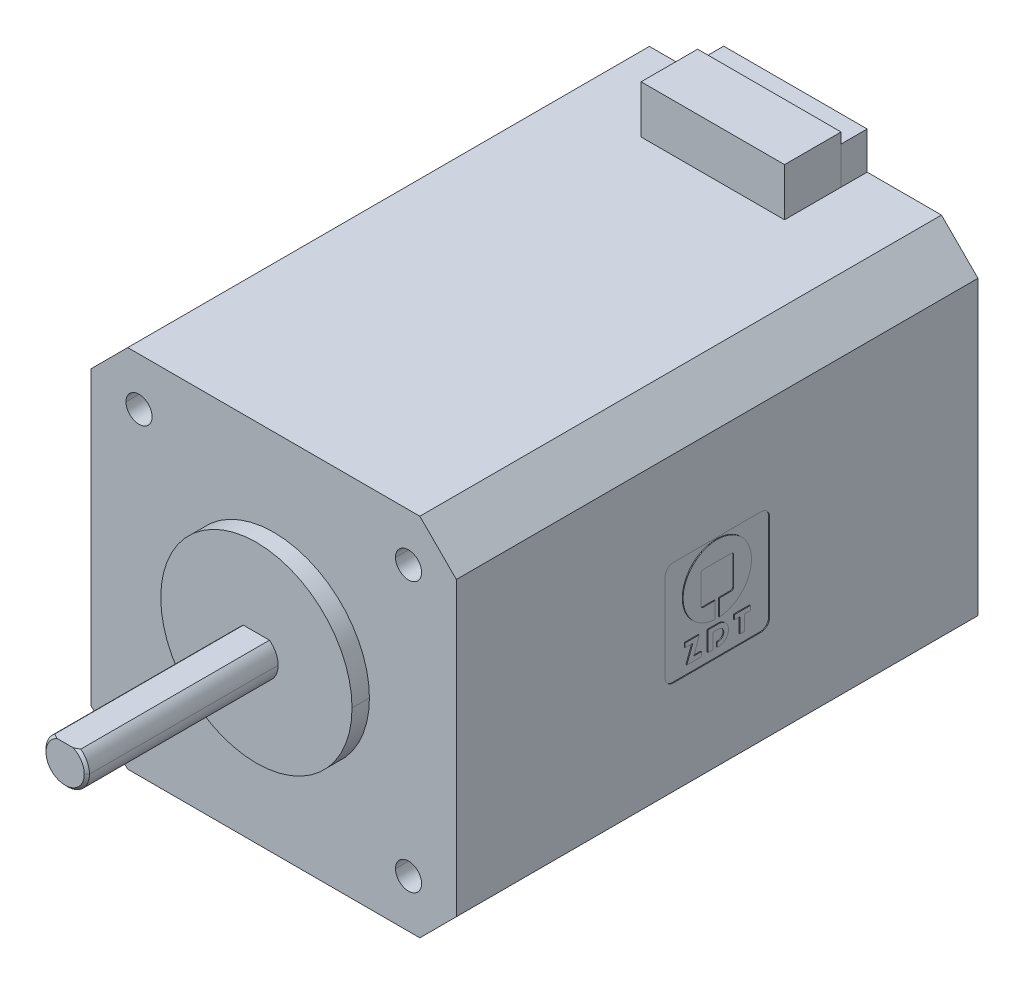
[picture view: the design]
ISO-10303-21;
HEADER;
FILE_DESCRIPTION(('STEP AP214'),'2;1');
FILE_NAME('part.step','',(''),(''),'','','');
FILE_SCHEMA(('AUTOMOTIVE_DESIGN { 1 0 10303 214 1 1 1 1 }'));
ENDSEC;
DATA;
#1=APPLICATION_CONTEXT('core data for automotive mechanical design processes');
#2=APPLICATION_PROTOCOL_DEFINITION('international standard','automotive_design',2000,#1);
#3=PRODUCT_CONTEXT('',#1,'mechanical');
#4=PRODUCT('Part','Part','',(#3));
#5=PRODUCT_RELATED_PRODUCT_CATEGORY('part','',(#4));
#6=PRODUCT_DEFINITION_FORMATION('','',#4);
#7=PRODUCT_DEFINITION_CONTEXT('part definition',#1,'design');
#8=PRODUCT_DEFINITION('design','',#6,#7);
#9=PRODUCT_DEFINITION_SHAPE('','',#8);
#10=(LENGTH_UNIT() NAMED_UNIT(*) SI_UNIT(.MILLI.,.METRE.));
#11=(NAMED_UNIT(*) PLANE_ANGLE_UNIT() SI_UNIT($,.RADIAN.));
#12=(NAMED_UNIT(*) SI_UNIT($,.STERADIAN.) SOLID_ANGLE_UNIT());
#13=UNCERTAINTY_MEASURE_WITH_UNIT(LENGTH_MEASURE(1.E-05),#10,'distance_accuracy_value','');
#14=(GEOMETRIC_REPRESENTATION_CONTEXT(3) GLOBAL_UNCERTAINTY_ASSIGNED_CONTEXT((#13)) GLOBAL_UNIT_ASSIGNED_CONTEXT((#10,
#11,#12)) REPRESENTATION_CONTEXT('',''));
#15=CARTESIAN_POINT('',(0.,0.,0.));
#16=DIRECTION('',(0.,0.,1.));
#17=DIRECTION('',(1.,0.,0.));
#18=AXIS2_PLACEMENT_3D('',#15,#16,#17);
#19=CARTESIAN_POINT('',(21.,16.8,60.));
#20=DIRECTION('',(-1.,0.,0.));
#21=DIRECTION('',(0.,1.,0.));
#22=AXIS2_PLACEMENT_3D('',#19,#20,#21);
#23=PLANE('',#22);
#24=DIRECTION('',(0.,0.,1.));
#25=VECTOR('',#24,1.);
#26=CARTESIAN_POINT('',(21.,-2.68631850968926,32.0616));
#27=LINE('',#26,#25);
#28=CARTESIAN_POINT('',(21.,-2.68631850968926,32.0616));
#29=VERTEX_POINT('',#28);
#30=CARTESIAN_POINT('',(21.,-2.68631850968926,33.6787));
#31=VERTEX_POINT('',#30);
#32=EDGE_CURVE('P0_E1623',#29,#31,#27,.T.);
#33=ORIENTED_EDGE('',*,*,#32,.T.);
#34=DIRECTION('',(0.,-1.,0.));
#35=VECTOR('',#34,1.);
#36=CARTESIAN_POINT('',(21.,-2.68631850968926,33.6787));
#37=LINE('',#36,#35);
#38=CARTESIAN_POINT('',(21.,-3.15601850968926,33.6787));
#39=VERTEX_POINT('',#38);
#40=EDGE_CURVE('P0_E11',#31,#39,#37,.T.);
#41=ORIENTED_EDGE('',*,*,#40,.T.);
#42=DIRECTION('',(0.,0.,-1.));
#43=VECTOR('',#42,1.);
#44=CARTESIAN_POINT('',(21.,-3.15601850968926,33.6787));
#45=LINE('',#44,#43);
#46=CARTESIAN_POINT('',(21.,-3.15601850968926,32.8051));
#47=VERTEX_POINT('',#46);
#48=EDGE_CURVE('P0_E48',#39,#47,#45,.T.);
#49=ORIENTED_EDGE('',*,*,#48,.T.);
#50=DIRECTION('',(0.,-0.936094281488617,0.351749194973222));
#51=VECTOR('',#50,1.);
#52=CARTESIAN_POINT('',(21.,-3.15601850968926,32.8051));
#53=LINE('',#52,#51);
#54=CARTESIAN_POINT('',(21.,-4.97551850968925,33.4888));
#55=VERTEX_POINT('',#54);
#56=EDGE_CURVE('P0_E1660',#47,#55,#53,.T.);
#57=ORIENTED_EDGE('',*,*,#56,.T.);
#58=DIRECTION('',(0.,0.,-1.));
#59=VECTOR('',#58,1.);
#60=CARTESIAN_POINT('',(21.,-4.97551850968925,33.4888));
#61=LINE('',#60,#59);
#62=CARTESIAN_POINT('',(21.,-4.97551850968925,31.8183));
#63=VERTEX_POINT('',#62);
#64=EDGE_CURVE('P0_E1654',#55,#63,#61,.T.);
#65=ORIENTED_EDGE('',*,*,#64,.T.);
#66=DIRECTION('',(0.,1.,0.));
#67=VECTOR('',#66,1.);
#68=CARTESIAN_POINT('',(21.,-4.97551850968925,31.8183));
#69=LINE('',#68,#67);
#70=CARTESIAN_POINT('',(21.,-4.48721850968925,31.8183));
#71=VERTEX_POINT('',#70);
#72=EDGE_CURVE('P0_E781',#63,#71,#69,.T.);
#73=ORIENTED_EDGE('',*,*,#72,.T.);
#74=DIRECTION('',(0.,0.,1.));
#75=VECTOR('',#74,1.);
#76=CARTESIAN_POINT('',(21.,-4.48721850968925,31.8183));
#77=LINE('',#76,#75);
#78=CARTESIAN_POINT('',(21.,-4.48721850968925,32.6607));
#79=VERTEX_POINT('',#78);
#80=EDGE_CURVE('P0_E785',#71,#79,#77,.T.);
#81=ORIENTED_EDGE('',*,*,#80,.T.);
#82=DIRECTION('',(0.,0.948882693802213,-0.315628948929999));
#83=VECTOR('',#82,1.);
#84=CARTESIAN_POINT('',(21.,-4.48721850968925,32.6607));
#85=LINE('',#84,#83);
#86=CARTESIAN_POINT('',(21.,-3.15601850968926,32.2179));
#87=VERTEX_POINT('',#86);
#88=EDGE_CURVE('P0_E752',#79,#87,#85,.T.);
#89=ORIENTED_EDGE('',*,*,#88,.T.);
#90=DIRECTION('',(0.,0.948844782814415,-0.315742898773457));
#91=VECTOR('',#90,1.);
#92=CARTESIAN_POINT('',(21.,-3.15601850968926,32.2179));
#93=LINE('',#92,#91);
#94=EDGE_CURVE('P0_E1636',#87,#29,#93,.T.);
#95=ORIENTED_EDGE('',*,*,#94,.T.);
#96=EDGE_LOOP('',(#33,#41,#49,#57,#65,#73,#81,#89,#95));
#97=FACE_BOUND('',#96,.T.);
#98=ADVANCED_FACE('P0_F18',(#97),#23,.F.);
#99=CARTESIAN_POINT('',(21.,16.8,60.));
#100=DIRECTION('',(-1.,0.,0.));
#101=DIRECTION('',(0.,1.,0.));
#102=AXIS2_PLACEMENT_3D('',#99,#100,#101);
#103=PLANE('',#102);
#104=CARTESIAN_POINT('',(21.,-3.21791850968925,29.8494));
#105=CARTESIAN_POINT('',(21.,-3.21791850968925,29.5131));
#106=CARTESIAN_POINT('',(21.,-3.49311850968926,29.2382));
#107=CARTESIAN_POINT('',(21.,-3.82921850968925,29.2382));
#108=(BOUNDED_CURVE() B_SPLINE_CURVE(3,(#104,#105,#106,#107),.UNSPECIFIED.,.F.,
.F.) B_SPLINE_CURVE_WITH_KNOTS((4,4),(0.4375,0.5),
.UNSPECIFIED.) CURVE() GEOMETRIC_REPRESENTATION_ITEM() RATIONAL_B_SPLINE_CURVE((1.,1.,1.,1.)) REPRESENTATION_ITEM(''));
#109=CARTESIAN_POINT('',(21.,-3.21791850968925,29.8494));
#110=VERTEX_POINT('',#109);
#111=CARTESIAN_POINT('',(21.,-3.82921850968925,29.2382));
#112=VERTEX_POINT('',#111);
#113=EDGE_CURVE('P0_E1344',#110,#112,#108,.T.);
#114=ORIENTED_EDGE('',*,*,#113,.T.);
#115=CARTESIAN_POINT('',(21.,-3.82921850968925,29.2382));
#116=CARTESIAN_POINT('',(21.,-4.16521850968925,29.2382));
#117=CARTESIAN_POINT('',(21.,-4.44041850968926,29.5131));
#118=CARTESIAN_POINT('',(21.,-4.44041850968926,29.8494));
#119=(BOUNDED_CURVE() B_SPLINE_CURVE(3,(#115,#116,#117,#118),.UNSPECIFIED.,.F.,
.F.) B_SPLINE_CURVE_WITH_KNOTS((4,4),(0.5,0.5625),
.UNSPECIFIED.) CURVE() GEOMETRIC_REPRESENTATION_ITEM() RATIONAL_B_SPLINE_CURVE((1.,1.,1.,1.)) REPRESENTATION_ITEM(''));
#120=CARTESIAN_POINT('',(21.,-4.44041850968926,29.8494));
#121=VERTEX_POINT('',#120);
#122=EDGE_CURVE('P0_E1440',#112,#121,#119,.T.);
#123=ORIENTED_EDGE('',*,*,#122,.T.);
#124=DIRECTION('',(0.,0.,1.));
#125=VECTOR('',#124,1.);
#126=CARTESIAN_POINT('',(21.,-4.44041850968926,29.8494));
#127=LINE('',#126,#125);
#128=CARTESIAN_POINT('',(21.,-4.44041850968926,30.));
#129=VERTEX_POINT('',#128);
#130=EDGE_CURVE('P0_E1434',#121,#129,#127,.T.);
#131=ORIENTED_EDGE('',*,*,#130,.T.);
#132=DIRECTION('',(0.,-1.,0.));
#133=VECTOR('',#132,1.);
#134=CARTESIAN_POINT('',(21.,-4.44041850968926,30.));
#135=LINE('',#134,#133);
#136=CARTESIAN_POINT('',(21.,-4.96361850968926,30.));
#137=VERTEX_POINT('',#136);
#138=EDGE_CURVE('P0_E1426',#129,#137,#135,.T.);
#139=ORIENTED_EDGE('',*,*,#138,.T.);
#140=DIRECTION('',(0.,0.,-1.));
#141=VECTOR('',#140,1.);
#142=CARTESIAN_POINT('',(21.,-4.96361850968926,30.));
#143=LINE('',#142,#141);
#144=CARTESIAN_POINT('',(21.,-4.96361850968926,29.8307));
#145=VERTEX_POINT('',#144);
#146=EDGE_CURVE('P0_E1417',#137,#145,#143,.T.);
#147=ORIENTED_EDGE('',*,*,#146,.T.);
#148=CARTESIAN_POINT('',(21.,-4.96361850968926,29.8307));
#149=CARTESIAN_POINT('',(21.,-4.96361850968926,29.2067));
#150=CARTESIAN_POINT('',(21.,-4.45321850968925,28.6962));
#151=CARTESIAN_POINT('',(21.,-3.82921850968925,28.6962));
#152=(BOUNDED_CURVE() B_SPLINE_CURVE(3,(#148,#149,#150,#151),.UNSPECIFIED.,.F.,
.F.) B_SPLINE_CURVE_WITH_KNOTS((4,4),(0.75,0.8125),
.UNSPECIFIED.) CURVE() GEOMETRIC_REPRESENTATION_ITEM() RATIONAL_B_SPLINE_CURVE((1.,1.,1.,1.)) REPRESENTATION_ITEM(''));
#153=CARTESIAN_POINT('',(21.,-3.82921850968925,28.6962));
#154=VERTEX_POINT('',#153);
#155=EDGE_CURVE('P0_E1407',#145,#154,#152,.T.);
#156=ORIENTED_EDGE('',*,*,#155,.T.);
#157=CARTESIAN_POINT('',(21.,-3.82921850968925,28.6962));
#158=CARTESIAN_POINT('',(21.,-3.20521850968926,28.6962));
#159=CARTESIAN_POINT('',(21.,-2.69471850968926,29.2067));
#160=CARTESIAN_POINT('',(21.,-2.69471850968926,29.8307));
#161=(BOUNDED_CURVE() B_SPLINE_CURVE(3,(#157,#158,#159,#160),.UNSPECIFIED.,.F.,
.F.) B_SPLINE_CURVE_WITH_KNOTS((4,4),(0.875,0.9375),
.UNSPECIFIED.) CURVE() GEOMETRIC_REPRESENTATION_ITEM() RATIONAL_B_SPLINE_CURVE((1.,1.,1.,1.)) REPRESENTATION_ITEM(''));
#162=CARTESIAN_POINT('',(21.,-2.69471850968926,29.8307));
#163=VERTEX_POINT('',#162);
#164=EDGE_CURVE('P0_E1394',#154,#163,#161,.T.);
#165=ORIENTED_EDGE('',*,*,#164,.T.);
#166=DIRECTION('',(0.,0.,1.));
#167=VECTOR('',#166,1.);
#168=CARTESIAN_POINT('',(21.,-2.69471850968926,29.8307));
#169=LINE('',#168,#167);
#170=CARTESIAN_POINT('',(21.,-2.69471850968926,31.0456));
#171=VERTEX_POINT('',#170);
#172=EDGE_CURVE('P0_E1388',#163,#171,#169,.T.);
#173=ORIENTED_EDGE('',*,*,#172,.T.);
#174=DIRECTION('',(0.,-1.,0.));
#175=VECTOR('',#174,1.);
#176=CARTESIAN_POINT('',(21.,-2.69471850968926,31.0456));
#177=LINE('',#176,#175);
#178=CARTESIAN_POINT('',(21.,-4.96361850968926,31.0456));
#179=VERTEX_POINT('',#178);
#180=EDGE_CURVE('P0_E1381',#171,#179,#177,.T.);
#181=ORIENTED_EDGE('',*,*,#180,.T.);
#182=DIRECTION('',(0.,0.,-1.));
#183=VECTOR('',#182,1.);
#184=CARTESIAN_POINT('',(21.,-4.96361850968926,31.0456));
#185=LINE('',#184,#183);
#186=CARTESIAN_POINT('',(21.,-4.96361850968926,30.5036));
#187=VERTEX_POINT('',#186);
#188=EDGE_CURVE('P0_E1373',#179,#187,#185,.T.);
#189=ORIENTED_EDGE('',*,*,#188,.T.);
#190=DIRECTION('',(0.,1.,0.));
#191=VECTOR('',#190,1.);
#192=CARTESIAN_POINT('',(21.,-4.05351850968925,30.5036));
#193=LINE('',#192,#191);
#194=CARTESIAN_POINT('',(21.,-3.21791850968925,30.5036));
#195=VERTEX_POINT('',#194);
#196=EDGE_CURVE('P0_E1370',#187,#195,#193,.T.);
#197=ORIENTED_EDGE('',*,*,#196,.T.);
#198=DIRECTION('',(0.,0.,-1.));
#199=VECTOR('',#198,1.);
#200=CARTESIAN_POINT('',(21.,-3.21791850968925,30.5036));
#201=LINE('',#200,#199);
#202=EDGE_CURVE('P0_E956',#195,#110,#201,.T.);
#203=ORIENTED_EDGE('',*,*,#202,.T.);
#204=EDGE_LOOP('',(#114,#123,#131,#139,#147,#156,#165,#173,#181,#189,#197,#203));
#205=FACE_BOUND('',#204,.T.);
#206=ADVANCED_FACE('P0_F20',(#205),#103,.F.);
#207=CARTESIAN_POINT('',(21.,16.8,60.));
#208=DIRECTION('',(-1.,0.,0.));
#209=DIRECTION('',(0.,1.,0.));
#210=AXIS2_PLACEMENT_3D('',#207,#208,#209);
#211=PLANE('',#210);
#212=CARTESIAN_POINT('',(21.,-2.06441850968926,29.7418));
#213=CARTESIAN_POINT('',(21.,-1.93761850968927,27.6866));
#214=CARTESIAN_POINT('',(21.,-0.231118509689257,26.0587));
#215=CARTESIAN_POINT('',(21.,1.85608149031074,26.0587));
#216=(BOUNDED_CURVE() B_SPLINE_CURVE(3,(#212,#213,#214,#215),.UNSPECIFIED.,.F.,
.F.) B_SPLINE_CURVE_WITH_KNOTS((4,4),(0.125,0.1875),
.UNSPECIFIED.) CURVE() GEOMETRIC_REPRESENTATION_ITEM() RATIONAL_B_SPLINE_CURVE((1.,1.,1.,1.)) REPRESENTATION_ITEM(''));
#217=CARTESIAN_POINT('',(21.,-2.06441850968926,29.7418));
#218=VERTEX_POINT('',#217);
#219=CARTESIAN_POINT('',(21.,1.85608149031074,26.0587));
#220=VERTEX_POINT('',#219);
#221=EDGE_CURVE('P0_E1444',#218,#220,#216,.T.);
#222=ORIENTED_EDGE('',*,*,#221,.T.);
#223=CARTESIAN_POINT('',(21.,1.85608149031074,26.0587));
#224=CARTESIAN_POINT('',(21.,4.02578149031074,26.0587));
#225=CARTESIAN_POINT('',(21.,5.78458149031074,27.8178));
#226=CARTESIAN_POINT('',(21.,5.78458149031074,29.9874));
#227=(BOUNDED_CURVE() B_SPLINE_CURVE(3,(#223,#224,#225,#226),.UNSPECIFIED.,.F.,
.F.) B_SPLINE_CURVE_WITH_KNOTS((4,4),(0.1875,0.25),
.UNSPECIFIED.) CURVE() GEOMETRIC_REPRESENTATION_ITEM() RATIONAL_B_SPLINE_CURVE((1.,1.,1.,1.)) REPRESENTATION_ITEM(''));
#228=CARTESIAN_POINT('',(21.,5.78458149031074,29.9874));
#229=VERTEX_POINT('',#228);
#230=EDGE_CURVE('P0_E1568',#220,#229,#227,.T.);
#231=ORIENTED_EDGE('',*,*,#230,.T.);
#232=CARTESIAN_POINT('',(21.,5.78458149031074,29.9874));
#233=CARTESIAN_POINT('',(21.,5.78458149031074,32.1568));
#234=CARTESIAN_POINT('',(21.,4.02578149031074,33.9159));
#235=CARTESIAN_POINT('',(21.,1.85608149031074,33.9159));
#236=(BOUNDED_CURVE() B_SPLINE_CURVE(3,(#232,#233,#234,#235),.UNSPECIFIED.,.F.,
.F.) B_SPLINE_CURVE_WITH_KNOTS((4,4),(0.25,0.3125),
.UNSPECIFIED.) CURVE() GEOMETRIC_REPRESENTATION_ITEM() RATIONAL_B_SPLINE_CURVE((1.,1.,1.,1.)) REPRESENTATION_ITEM(''));
#237=CARTESIAN_POINT('',(21.,1.85608149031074,33.9159));
#238=VERTEX_POINT('',#237);
#239=EDGE_CURVE('P0_E1558',#229,#238,#236,.T.);
#240=ORIENTED_EDGE('',*,*,#239,.T.);
#241=CARTESIAN_POINT('',(21.,1.85608149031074,33.9159));
#242=CARTESIAN_POINT('',(21.,-0.231118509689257,33.9159));
#243=CARTESIAN_POINT('',(21.,-1.93761850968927,32.288));
#244=CARTESIAN_POINT('',(21.,-2.06441850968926,30.2328));
#245=(BOUNDED_CURVE() B_SPLINE_CURVE(3,(#241,#242,#243,#244),.UNSPECIFIED.,.F.,
.F.) B_SPLINE_CURVE_WITH_KNOTS((4,4),(0.3125,0.375),
.UNSPECIFIED.) CURVE() GEOMETRIC_REPRESENTATION_ITEM() RATIONAL_B_SPLINE_CURVE((1.,1.,1.,1.)) REPRESENTATION_ITEM(''));
#246=CARTESIAN_POINT('',(21.,-2.06441850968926,30.2328));
#247=VERTEX_POINT('',#246);
#248=EDGE_CURVE('P0_E1546',#238,#247,#245,.T.);
#249=ORIENTED_EDGE('',*,*,#248,.T.);
#250=DIRECTION('',(0.,1.,0.));
#251=VECTOR('',#250,1.);
#252=CARTESIAN_POINT('',(21.,-2.06441850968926,30.2328));
#253=LINE('',#252,#251);
#254=CARTESIAN_POINT('',(21.,-0.175218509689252,30.2328));
#255=VERTEX_POINT('',#254);
#256=EDGE_CURVE('P0_E1538',#247,#255,#253,.T.);
#257=ORIENTED_EDGE('',*,*,#256,.T.);
#258=DIRECTION('',(0.,0.,1.));
#259=VECTOR('',#258,1.);
#260=CARTESIAN_POINT('',(21.,-0.175218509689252,30.2328));
#261=LINE('',#260,#259);
#262=CARTESIAN_POINT('',(21.,-0.175218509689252,31.5695));
#263=VERTEX_POINT('',#262);
#264=EDGE_CURVE('P0_E1535',#255,#263,#261,.T.);
#265=ORIENTED_EDGE('',*,*,#264,.T.);
#266=CARTESIAN_POINT('',(21.,-0.175218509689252,31.5695));
#267=CARTESIAN_POINT('',(21.,-0.175218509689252,31.7375));
#268=CARTESIAN_POINT('',(21.,-0.0379185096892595,31.8747));
#269=CARTESIAN_POINT('',(21.,0.129781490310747,31.8747));
#270=(BOUNDED_CURVE() B_SPLINE_CURVE(3,(#266,#267,#268,#269),.UNSPECIFIED.,.F.,
.F.) B_SPLINE_CURVE_WITH_KNOTS((4,4),(0.5,0.5625),
.UNSPECIFIED.) CURVE() GEOMETRIC_REPRESENTATION_ITEM() RATIONAL_B_SPLINE_CURVE((1.,1.,1.,1.)) REPRESENTATION_ITEM(''));
#271=CARTESIAN_POINT('',(21.,0.129781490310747,31.8747));
#272=VERTEX_POINT('',#271);
#273=EDGE_CURVE('P0_E1519',#263,#272,#270,.T.);
#274=ORIENTED_EDGE('',*,*,#273,.T.);
#275=DIRECTION('',(0.,1.,0.));
#276=VECTOR('',#275,1.);
#277=CARTESIAN_POINT('',(21.,0.129781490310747,31.8747));
#278=LINE('',#277,#276);
#279=CARTESIAN_POINT('',(21.,3.29448149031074,31.8747));
#280=VERTEX_POINT('',#279);
#281=EDGE_CURVE('P0_E1514',#272,#280,#278,.T.);
#282=ORIENTED_EDGE('',*,*,#281,.T.);
#283=CARTESIAN_POINT('',(21.,3.29448149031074,31.8747));
#284=CARTESIAN_POINT('',(21.,3.46218149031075,31.8747));
#285=CARTESIAN_POINT('',(21.,3.59968149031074,31.7375));
#286=CARTESIAN_POINT('',(21.,3.59968149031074,31.5695));
#287=(BOUNDED_CURVE() B_SPLINE_CURVE(3,(#283,#284,#285,#286),.UNSPECIFIED.,.F.,
.F.) B_SPLINE_CURVE_WITH_KNOTS((4,4),(0.625,0.6875),
.UNSPECIFIED.) CURVE() GEOMETRIC_REPRESENTATION_ITEM() RATIONAL_B_SPLINE_CURVE((1.,1.,1.,1.)) REPRESENTATION_ITEM(''));
#288=CARTESIAN_POINT('',(21.,3.59968149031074,31.5695));
#289=VERTEX_POINT('',#288);
#290=EDGE_CURVE('P0_E735',#280,#289,#287,.T.);
#291=ORIENTED_EDGE('',*,*,#290,.T.);
#292=DIRECTION('',(0.,0.,-1.));
#293=VECTOR('',#292,1.);
#294=CARTESIAN_POINT('',(21.,3.59968149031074,31.5695));
#295=LINE('',#294,#293);
#296=CARTESIAN_POINT('',(21.,3.59968149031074,28.4051));
#297=VERTEX_POINT('',#296);
#298=EDGE_CURVE('P0_E1028',#289,#297,#295,.T.);
#299=ORIENTED_EDGE('',*,*,#298,.T.);
#300=CARTESIAN_POINT('',(21.,3.59968149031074,28.4051));
#301=CARTESIAN_POINT('',(21.,3.59968149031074,28.2371));
#302=CARTESIAN_POINT('',(21.,3.46218149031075,28.0999));
#303=CARTESIAN_POINT('',(21.,3.29448149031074,28.0999));
#304=(BOUNDED_CURVE() B_SPLINE_CURVE(3,(#300,#301,#302,#303),.UNSPECIFIED.,.F.,
.F.) B_SPLINE_CURVE_WITH_KNOTS((4,4),(0.75,0.8125),
.UNSPECIFIED.) CURVE() GEOMETRIC_REPRESENTATION_ITEM() RATIONAL_B_SPLINE_CURVE((1.,1.,1.,1.)) REPRESENTATION_ITEM(''));
#305=CARTESIAN_POINT('',(21.,3.29448149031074,28.0999));
#306=VERTEX_POINT('',#305);
#307=EDGE_CURVE('P0_E1030',#297,#306,#304,.T.);
#308=ORIENTED_EDGE('',*,*,#307,.T.);
#309=DIRECTION('',(0.,-1.,0.));
#310=VECTOR('',#309,1.);
#311=CARTESIAN_POINT('',(21.,3.29448149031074,28.0999));
#312=LINE('',#311,#310);
#313=CARTESIAN_POINT('',(21.,0.129781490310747,28.0999));
#314=VERTEX_POINT('',#313);
#315=EDGE_CURVE('P0_E1491',#306,#314,#312,.T.);
#316=ORIENTED_EDGE('',*,*,#315,.T.);
#317=CARTESIAN_POINT('',(21.,0.129781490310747,28.0999));
#318=CARTESIAN_POINT('',(21.,-0.0379185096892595,28.0999));
#319=CARTESIAN_POINT('',(21.,-0.175218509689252,28.2371));
#320=CARTESIAN_POINT('',(21.,-0.175218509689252,28.4051));
#321=(BOUNDED_CURVE() B_SPLINE_CURVE(3,(#317,#318,#319,#320),.UNSPECIFIED.,.F.,
.F.) B_SPLINE_CURVE_WITH_KNOTS((4,4),(0.875,0.9375),
.UNSPECIFIED.) CURVE() GEOMETRIC_REPRESENTATION_ITEM() RATIONAL_B_SPLINE_CURVE((1.,1.,1.,1.)) REPRESENTATION_ITEM(''));
#322=CARTESIAN_POINT('',(21.,-0.175218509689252,28.4051));
#323=VERTEX_POINT('',#322);
#324=EDGE_CURVE('P0_E1477',#314,#323,#321,.T.);
#325=ORIENTED_EDGE('',*,*,#324,.T.);
#326=DIRECTION('',(0.,0.,1.));
#327=VECTOR('',#326,1.);
#328=CARTESIAN_POINT('',(21.,-0.175218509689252,28.4051));
#329=LINE('',#328,#327);
#330=CARTESIAN_POINT('',(21.,-0.175218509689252,29.7418));
#331=VERTEX_POINT('',#330);
#332=EDGE_CURVE('P0_E1475',#323,#331,#329,.T.);
#333=ORIENTED_EDGE('',*,*,#332,.T.);
#334=DIRECTION('',(0.,-1.,0.));
#335=VECTOR('',#334,1.);
#336=CARTESIAN_POINT('',(21.,-0.175218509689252,29.7418));
#337=LINE('',#336,#335);
#338=EDGE_CURVE('P0_E1464',#331,#218,#337,.T.);
#339=ORIENTED_EDGE('',*,*,#338,.T.);
#340=EDGE_LOOP('',(#222,#231,#240,#249,#257,#265,#274,#282,#291,#299,#308,#316,#325,#333,#339));
#341=FACE_BOUND('',#340,.T.);
#342=ADVANCED_FACE('P0_F1847',(#341),#211,.F.);
#343=CARTESIAN_POINT('',(21.,16.8,60.));
#344=DIRECTION('',(-1.,0.,0.));
#345=DIRECTION('',(0.,1.,0.));
#346=AXIS2_PLACEMENT_3D('',#343,#344,#345);
#347=PLANE('',#346);
#348=DIRECTION('',(0.,0.,1.));
#349=VECTOR('',#348,1.);
#350=CARTESIAN_POINT('',(21.,-2.69881850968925,26.1943));
#351=LINE('',#350,#349);
#352=CARTESIAN_POINT('',(21.,-2.69881850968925,26.1943));
#353=VERTEX_POINT('',#352);
#354=CARTESIAN_POINT('',(21.,-2.69881850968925,28.0146));
#355=VERTEX_POINT('',#354);
#356=EDGE_CURVE('P0_E1574',#353,#355,#351,.T.);
#357=ORIENTED_EDGE('',*,*,#356,.T.);
#358=DIRECTION('',(0.,-1.,0.));
#359=VECTOR('',#358,1.);
#360=CARTESIAN_POINT('',(21.,-2.69881850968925,28.0146));
#361=LINE('',#360,#359);
#362=CARTESIAN_POINT('',(21.,-3.21521850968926,28.0146));
#363=VERTEX_POINT('',#362);
#364=EDGE_CURVE('P0_E1625',#355,#363,#361,.T.);
#365=ORIENTED_EDGE('',*,*,#364,.T.);
#366=DIRECTION('',(0.,0.,-1.));
#367=VECTOR('',#366,1.);
#368=CARTESIAN_POINT('',(21.,-3.21521850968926,28.0146));
#369=LINE('',#368,#367);
#370=CARTESIAN_POINT('',(21.,-3.21521850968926,27.3627));
#371=VERTEX_POINT('',#370);
#372=EDGE_CURVE('P0_E1614',#363,#371,#369,.T.);
#373=ORIENTED_EDGE('',*,*,#372,.T.);
#374=DIRECTION('',(0.,-1.,0.));
#375=VECTOR('',#374,1.);
#376=CARTESIAN_POINT('',(21.,-3.21521850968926,27.3627));
#377=LINE('',#376,#375);
#378=CARTESIAN_POINT('',(21.,-4.94241850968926,27.3627));
#379=VERTEX_POINT('',#378);
#380=EDGE_CURVE('P0_E1335',#371,#379,#377,.T.);
#381=ORIENTED_EDGE('',*,*,#380,.T.);
#382=DIRECTION('',(0.,0.,-1.));
#383=VECTOR('',#382,1.);
#384=CARTESIAN_POINT('',(21.,-4.94241850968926,27.3627));
#385=LINE('',#384,#383);
#386=CARTESIAN_POINT('',(21.,-4.94241850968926,26.8462));
#387=VERTEX_POINT('',#386);
#388=EDGE_CURVE('P0_E1606',#379,#387,#385,.T.);
#389=ORIENTED_EDGE('',*,*,#388,.T.);
#390=DIRECTION('',(0.,1.,0.));
#391=VECTOR('',#390,1.);
#392=CARTESIAN_POINT('',(21.,-4.94241850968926,26.8462));
#393=LINE('',#392,#391);
#394=CARTESIAN_POINT('',(21.,-3.21521850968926,26.8462));
#395=VERTEX_POINT('',#394);
#396=EDGE_CURVE('P0_E1596',#387,#395,#393,.T.);
#397=ORIENTED_EDGE('',*,*,#396,.T.);
#398=DIRECTION('',(0.,0.,-1.));
#399=VECTOR('',#398,1.);
#400=CARTESIAN_POINT('',(21.,-3.21521850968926,26.8462));
#401=LINE('',#400,#399);
#402=CARTESIAN_POINT('',(21.,-3.21521850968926,26.1943));
#403=VERTEX_POINT('',#402);
#404=EDGE_CURVE('P0_E1010',#395,#403,#401,.T.);
#405=ORIENTED_EDGE('',*,*,#404,.T.);
#406=DIRECTION('',(0.,1.,0.));
#407=VECTOR('',#406,1.);
#408=CARTESIAN_POINT('',(21.,-3.21521850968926,26.1943));
#409=LINE('',#408,#407);
#410=EDGE_CURVE('P0_E1589',#403,#353,#409,.T.);
#411=ORIENTED_EDGE('',*,*,#410,.T.);
#412=EDGE_LOOP('',(#357,#365,#373,#381,#389,#397,#405,#411));
#413=FACE_BOUND('',#412,.T.);
#414=ADVANCED_FACE('P0_F2117',(#413),#347,.F.);
#415=CARTESIAN_POINT('',(20.9,-2.68631850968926,33.6787));
#416=DIRECTION('',(0.,0.,1.));
#417=DIRECTION('',(1.,0.,0.));
#418=AXIS2_PLACEMENT_3D('',#415,#416,#417);
#419=PLANE('',#418);
#420=ORIENTED_EDGE('',*,*,#40,.F.);
#421=DIRECTION('',(1.,0.,0.));
#422=VECTOR('',#421,1.);
#423=CARTESIAN_POINT('',(20.9,-2.68631850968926,33.6787));
#424=LINE('',#423,#422);
#425=CARTESIAN_POINT('',(20.9,-2.68631850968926,33.6787));
#426=VERTEX_POINT('',#425);
#427=EDGE_CURVE('P0_E1635',#426,#31,#424,.T.);
#428=ORIENTED_EDGE('',*,*,#427,.F.);
#429=DIRECTION('',(0.,-1.,0.));
#430=VECTOR('',#429,1.);
#431=CARTESIAN_POINT('',(20.9,-2.68631850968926,33.6787));
#432=LINE('',#431,#430);
#433=CARTESIAN_POINT('',(20.9,-3.15601850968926,33.6787));
#434=VERTEX_POINT('',#433);
#435=EDGE_CURVE('P0_E955',#426,#434,#432,.T.);
#436=ORIENTED_EDGE('',*,*,#435,.T.);
#437=DIRECTION('',(1.,0.,0.));
#438=VECTOR('',#437,1.);
#439=CARTESIAN_POINT('',(20.9,-3.15601850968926,33.6787));
#440=LINE('',#439,#438);
#441=EDGE_CURVE('P0_E29',#434,#39,#440,.T.);
#442=ORIENTED_EDGE('',*,*,#441,.T.);
#443=EDGE_LOOP('',(#420,#428,#436,#442));
#444=FACE_BOUND('',#443,.T.);
#445=ADVANCED_FACE('P0_F1779',(#444),#419,.T.);
#446=CARTESIAN_POINT('',(20.9,-3.15601850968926,33.6787));
#447=DIRECTION('',(0.,-1.,0.));
#448=DIRECTION('',(0.,0.,-1.));
#449=AXIS2_PLACEMENT_3D('',#446,#447,#448);
#450=PLANE('',#449);
#451=ORIENTED_EDGE('',*,*,#48,.F.);
#452=ORIENTED_EDGE('',*,*,#441,.F.);
#453=DIRECTION('',(0.,0.,-1.));
#454=VECTOR('',#453,1.);
#455=CARTESIAN_POINT('',(20.9,-3.15601850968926,33.6787));
#456=LINE('',#455,#454);
#457=CARTESIAN_POINT('',(20.9,-3.15601850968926,32.8051));
#458=VERTEX_POINT('',#457);
#459=EDGE_CURVE('P0_E954',#434,#458,#456,.T.);
#460=ORIENTED_EDGE('',*,*,#459,.T.);
#461=DIRECTION('',(1.,0.,0.));
#462=VECTOR('',#461,1.);
#463=CARTESIAN_POINT('',(20.9,-3.15601850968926,32.8051));
#464=LINE('',#463,#462);
#465=EDGE_CURVE('P0_E1210',#458,#47,#464,.T.);
#466=ORIENTED_EDGE('',*,*,#465,.T.);
#467=EDGE_LOOP('',(#451,#452,#460,#466));
#468=FACE_BOUND('',#467,.T.);
#469=ADVANCED_FACE('P0_F1780',(#468),#450,.T.);
#470=CARTESIAN_POINT('',(20.9,-3.15601850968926,32.8051));
#471=DIRECTION('',(0.,0.351749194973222,0.936094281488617));
#472=DIRECTION('',(1.,0.,0.));
#473=AXIS2_PLACEMENT_3D('',#470,#471,#472);
#474=PLANE('',#473);
#475=ORIENTED_EDGE('',*,*,#56,.F.);
#476=ORIENTED_EDGE('',*,*,#465,.F.);
#477=DIRECTION('',(0.,-0.936094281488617,0.351749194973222));
#478=VECTOR('',#477,1.);
#479=CARTESIAN_POINT('',(20.9,-3.15601850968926,32.8051));
#480=LINE('',#479,#478);
#481=CARTESIAN_POINT('',(20.9,-4.97551850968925,33.4888));
#482=VERTEX_POINT('',#481);
#483=EDGE_CURVE('P0_E931',#458,#482,#480,.T.);
#484=ORIENTED_EDGE('',*,*,#483,.T.);
#485=DIRECTION('',(1.,0.,0.));
#486=VECTOR('',#485,1.);
#487=CARTESIAN_POINT('',(20.9,-4.97551850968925,33.4888));
#488=LINE('',#487,#486);
#489=EDGE_CURVE('P0_E1656',#482,#55,#488,.T.);
#490=ORIENTED_EDGE('',*,*,#489,.T.);
#491=EDGE_LOOP('',(#475,#476,#484,#490));
#492=FACE_BOUND('',#491,.T.);
#493=ADVANCED_FACE('P0_F1777',(#492),#474,.T.);
#494=CARTESIAN_POINT('',(20.9,-4.97551850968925,33.4888));
#495=DIRECTION('',(0.,-1.,0.));
#496=DIRECTION('',(0.,0.,-1.));
#497=AXIS2_PLACEMENT_3D('',#494,#495,#496);
#498=PLANE('',#497);
#499=ORIENTED_EDGE('',*,*,#64,.F.);
#500=ORIENTED_EDGE('',*,*,#489,.F.);
#501=DIRECTION('',(0.,0.,-1.));
#502=VECTOR('',#501,1.);
#503=CARTESIAN_POINT('',(20.9,-4.97551850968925,33.4888));
#504=LINE('',#503,#502);
#505=CARTESIAN_POINT('',(20.9,-4.97551850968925,31.8183));
#506=VERTEX_POINT('',#505);
#507=EDGE_CURVE('P0_E930',#482,#506,#504,.T.);
#508=ORIENTED_EDGE('',*,*,#507,.T.);
#509=DIRECTION('',(1.,0.,0.));
#510=VECTOR('',#509,1.);
#511=CARTESIAN_POINT('',(20.9,-4.97551850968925,31.8183));
#512=LINE('',#511,#510);
#513=EDGE_CURVE('P0_E1648',#506,#63,#512,.T.);
#514=ORIENTED_EDGE('',*,*,#513,.T.);
#515=EDGE_LOOP('',(#499,#500,#508,#514));
#516=FACE_BOUND('',#515,.T.);
#517=ADVANCED_FACE('P0_F1977',(#516),#498,.T.);
#518=CARTESIAN_POINT('',(20.9,-4.97551850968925,31.8183));
#519=DIRECTION('',(0.,0.,-1.));
#520=DIRECTION('',(0.,-1.,0.));
#521=AXIS2_PLACEMENT_3D('',#518,#519,#520);
#522=PLANE('',#521);
#523=ORIENTED_EDGE('',*,*,#72,.F.);
#524=ORIENTED_EDGE('',*,*,#513,.F.);
#525=DIRECTION('',(0.,1.,0.));
#526=VECTOR('',#525,1.);
#527=CARTESIAN_POINT('',(20.9,-4.97551850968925,31.8183));
#528=LINE('',#527,#526);
#529=CARTESIAN_POINT('',(20.9,-4.48721850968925,31.8183));
#530=VERTEX_POINT('',#529);
#531=EDGE_CURVE('P0_E935',#506,#530,#528,.T.);
#532=ORIENTED_EDGE('',*,*,#531,.T.);
#533=DIRECTION('',(1.,0.,0.));
#534=VECTOR('',#533,1.);
#535=CARTESIAN_POINT('',(20.9,-4.48721850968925,31.8183));
#536=LINE('',#535,#534);
#537=EDGE_CURVE('P0_E777',#530,#71,#536,.T.);
#538=ORIENTED_EDGE('',*,*,#537,.T.);
#539=EDGE_LOOP('',(#523,#524,#532,#538));
#540=FACE_BOUND('',#539,.T.);
#541=ADVANCED_FACE('P0_F1986',(#540),#522,.T.);
#542=CARTESIAN_POINT('',(20.9,-4.48721850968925,31.8183));
#543=DIRECTION('',(0.,1.,0.));
#544=DIRECTION('',(1.,0.,0.));
#545=AXIS2_PLACEMENT_3D('',#542,#543,#544);
#546=PLANE('',#545);
#547=ORIENTED_EDGE('',*,*,#80,.F.);
#548=ORIENTED_EDGE('',*,*,#537,.F.);
#549=DIRECTION('',(0.,0.,1.));
#550=VECTOR('',#549,1.);
#551=CARTESIAN_POINT('',(20.9,-4.48721850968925,31.8183));
#552=LINE('',#551,#550);
#553=CARTESIAN_POINT('',(20.9,-4.48721850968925,32.6607));
#554=VERTEX_POINT('',#553);
#555=EDGE_CURVE('P0_E1097',#530,#554,#552,.T.);
#556=ORIENTED_EDGE('',*,*,#555,.T.);
#557=DIRECTION('',(1.,0.,0.));
#558=VECTOR('',#557,1.);
#559=CARTESIAN_POINT('',(20.9,-4.48721850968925,32.6607));
#560=LINE('',#559,#558);
#561=EDGE_CURVE('P0_E758',#554,#79,#560,.T.);
#562=ORIENTED_EDGE('',*,*,#561,.T.);
#563=EDGE_LOOP('',(#547,#548,#556,#562));
#564=FACE_BOUND('',#563,.T.);
#565=ADVANCED_FACE('P0_F2103',(#564),#546,.T.);
#566=CARTESIAN_POINT('',(20.9,-4.48721850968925,32.6607));
#567=DIRECTION('',(0.,-0.315628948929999,-0.948882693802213));
#568=DIRECTION('',(0.,-0.948882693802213,0.315628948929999));
#569=AXIS2_PLACEMENT_3D('',#566,#567,#568);
#570=PLANE('',#569);
#571=ORIENTED_EDGE('',*,*,#88,.F.);
#572=ORIENTED_EDGE('',*,*,#561,.F.);
#573=DIRECTION('',(0.,0.948882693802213,-0.315628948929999));
#574=VECTOR('',#573,1.);
#575=CARTESIAN_POINT('',(20.9,-4.48721850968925,32.6607));
#576=LINE('',#575,#574);
#577=CARTESIAN_POINT('',(20.9,-3.15601850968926,32.2179));
#578=VERTEX_POINT('',#577);
#579=EDGE_CURVE('P0_E1092',#554,#578,#576,.T.);
#580=ORIENTED_EDGE('',*,*,#579,.T.);
#581=DIRECTION('',(1.,0.,0.));
#582=VECTOR('',#581,1.);
#583=CARTESIAN_POINT('',(20.9,-3.15601850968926,32.2179));
#584=LINE('',#583,#582);
#585=EDGE_CURVE('P0_E757',#578,#87,#584,.T.);
#586=ORIENTED_EDGE('',*,*,#585,.T.);
#587=EDGE_LOOP('',(#571,#572,#580,#586));
#588=FACE_BOUND('',#587,.T.);
#589=ADVANCED_FACE('P0_F1807',(#588),#570,.T.);
#590=CARTESIAN_POINT('',(20.9,-3.15601850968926,32.2179));
#591=DIRECTION('',(0.,-0.315742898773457,-0.948844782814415));
#592=DIRECTION('',(0.,-0.948844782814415,0.315742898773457));
#593=AXIS2_PLACEMENT_3D('',#590,#591,#592);
#594=PLANE('',#593);
#595=ORIENTED_EDGE('',*,*,#94,.F.);
#596=ORIENTED_EDGE('',*,*,#585,.F.);
#597=DIRECTION('',(0.,0.948844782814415,-0.315742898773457));
#598=VECTOR('',#597,1.);
#599=CARTESIAN_POINT('',(20.9,-3.15601850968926,32.2179));
#600=LINE('',#599,#598);
#601=CARTESIAN_POINT('',(20.9,-2.68631850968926,32.0616));
#602=VERTEX_POINT('',#601);
#603=EDGE_CURVE('P0_E1052',#578,#602,#600,.T.);
#604=ORIENTED_EDGE('',*,*,#603,.T.);
#605=DIRECTION('',(1.,0.,0.));
#606=VECTOR('',#605,1.);
#607=CARTESIAN_POINT('',(20.9,-2.68631850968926,32.0616));
#608=LINE('',#607,#606);
#609=EDGE_CURVE('P0_E1626',#602,#29,#608,.T.);
#610=ORIENTED_EDGE('',*,*,#609,.T.);
#611=EDGE_LOOP('',(#595,#596,#604,#610));
#612=FACE_BOUND('',#611,.T.);
#613=ADVANCED_FACE('P0_F1804',(#612),#594,.T.);
#614=CARTESIAN_POINT('',(20.9,-2.68631850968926,32.0616));
#615=DIRECTION('',(0.,1.,0.));
#616=DIRECTION('',(1.,0.,0.));
#617=AXIS2_PLACEMENT_3D('',#614,#615,#616);
#618=PLANE('',#617);
#619=ORIENTED_EDGE('',*,*,#32,.F.);
#620=ORIENTED_EDGE('',*,*,#609,.F.);
#621=DIRECTION('',(0.,0.,1.));
#622=VECTOR('',#621,1.);
#623=CARTESIAN_POINT('',(20.9,-2.68631850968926,32.0616));
#624=LINE('',#623,#622);
#625=EDGE_CURVE('P0_E843',#602,#426,#624,.T.);
#626=ORIENTED_EDGE('',*,*,#625,.T.);
#627=ORIENTED_EDGE('',*,*,#427,.T.);
#628=EDGE_LOOP('',(#619,#620,#626,#627));
#629=FACE_BOUND('',#628,.T.);
#630=ADVANCED_FACE('P0_F1808',(#629),#618,.T.);
#631=CARTESIAN_POINT('',(20.9,-2.69881850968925,28.0146));
#632=DIRECTION('',(0.,0.,1.));
#633=DIRECTION('',(1.,0.,0.));
#634=AXIS2_PLACEMENT_3D('',#631,#632,#633);
#635=PLANE('',#634);
#636=ORIENTED_EDGE('',*,*,#364,.F.);
#637=DIRECTION('',(1.,0.,0.));
#638=VECTOR('',#637,1.);
#639=CARTESIAN_POINT('',(20.9,-2.69881850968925,28.0146));
#640=LINE('',#639,#638);
#641=CARTESIAN_POINT('',(20.9,-2.69881850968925,28.0146));
#642=VERTEX_POINT('',#641);
#643=EDGE_CURVE('P0_E1586',#642,#355,#640,.T.);
#644=ORIENTED_EDGE('',*,*,#643,.F.);
#645=DIRECTION('',(0.,-1.,0.));
#646=VECTOR('',#645,1.);
#647=CARTESIAN_POINT('',(20.9,-2.69881850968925,28.0146));
#648=LINE('',#647,#646);
#649=CARTESIAN_POINT('',(20.9,-3.21521850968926,28.0146));
#650=VERTEX_POINT('',#649);
#651=EDGE_CURVE('P0_E1193',#642,#650,#648,.T.);
#652=ORIENTED_EDGE('',*,*,#651,.T.);
#653=DIRECTION('',(1.,0.,0.));
#654=VECTOR('',#653,1.);
#655=CARTESIAN_POINT('',(20.9,-3.21521850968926,28.0146));
#656=LINE('',#655,#654);
#657=EDGE_CURVE('P0_E1617',#650,#363,#656,.T.);
#658=ORIENTED_EDGE('',*,*,#657,.T.);
#659=EDGE_LOOP('',(#636,#644,#652,#658));
#660=FACE_BOUND('',#659,.T.);
#661=ADVANCED_FACE('P0_F1965',(#660),#635,.T.);
#662=CARTESIAN_POINT('',(20.9,-3.21521850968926,28.0146));
#663=DIRECTION('',(0.,-1.,0.));
#664=DIRECTION('',(0.,0.,-1.));
#665=AXIS2_PLACEMENT_3D('',#662,#663,#664);
#666=PLANE('',#665);
#667=ORIENTED_EDGE('',*,*,#372,.F.);
#668=ORIENTED_EDGE('',*,*,#657,.F.);
#669=DIRECTION('',(0.,0.,-1.));
#670=VECTOR('',#669,1.);
#671=CARTESIAN_POINT('',(20.9,-3.21521850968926,28.0146));
#672=LINE('',#671,#670);
#673=CARTESIAN_POINT('',(20.9,-3.21521850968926,27.3627));
#674=VERTEX_POINT('',#673);
#675=EDGE_CURVE('P0_E1187',#650,#674,#672,.T.);
#676=ORIENTED_EDGE('',*,*,#675,.T.);
#677=DIRECTION('',(1.,0.,0.));
#678=VECTOR('',#677,1.);
#679=CARTESIAN_POINT('',(20.9,-3.21521850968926,27.3627));
#680=LINE('',#679,#678);
#681=EDGE_CURVE('P0_E1338',#674,#371,#680,.T.);
#682=ORIENTED_EDGE('',*,*,#681,.T.);
#683=EDGE_LOOP('',(#667,#668,#676,#682));
#684=FACE_BOUND('',#683,.T.);
#685=ADVANCED_FACE('P0_F1962',(#684),#666,.T.);
#686=CARTESIAN_POINT('',(20.9,-3.21521850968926,27.3627));
#687=DIRECTION('',(0.,0.,1.));
#688=DIRECTION('',(1.,0.,0.));
#689=AXIS2_PLACEMENT_3D('',#686,#687,#688);
#690=PLANE('',#689);
#691=ORIENTED_EDGE('',*,*,#380,.F.);
#692=ORIENTED_EDGE('',*,*,#681,.F.);
#693=DIRECTION('',(0.,-1.,0.));
#694=VECTOR('',#693,1.);
#695=CARTESIAN_POINT('',(20.9,-3.21521850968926,27.3627));
#696=LINE('',#695,#694);
#697=CARTESIAN_POINT('',(20.9,-4.94241850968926,27.3627));
#698=VERTEX_POINT('',#697);
#699=EDGE_CURVE('P0_E1195',#674,#698,#696,.T.);
#700=ORIENTED_EDGE('',*,*,#699,.T.);
#701=DIRECTION('',(1.,0.,0.));
#702=VECTOR('',#701,1.);
#703=CARTESIAN_POINT('',(20.9,-4.94241850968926,27.3627));
#704=LINE('',#703,#702);
#705=EDGE_CURVE('P0_E1337',#698,#379,#704,.T.);
#706=ORIENTED_EDGE('',*,*,#705,.T.);
#707=EDGE_LOOP('',(#691,#692,#700,#706));
#708=FACE_BOUND('',#707,.T.);
#709=ADVANCED_FACE('P0_F1733',(#708),#690,.T.);
#710=CARTESIAN_POINT('',(20.9,-4.94241850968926,27.3627));
#711=DIRECTION('',(0.,-1.,0.));
#712=DIRECTION('',(0.,0.,-1.));
#713=AXIS2_PLACEMENT_3D('',#710,#711,#712);
#714=PLANE('',#713);
#715=ORIENTED_EDGE('',*,*,#388,.F.);
#716=ORIENTED_EDGE('',*,*,#705,.F.);
#717=DIRECTION('',(0.,0.,-1.));
#718=VECTOR('',#717,1.);
#719=CARTESIAN_POINT('',(20.9,-4.94241850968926,27.3627));
#720=LINE('',#719,#718);
#721=CARTESIAN_POINT('',(20.9,-4.94241850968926,26.8462));
#722=VERTEX_POINT('',#721);
#723=EDGE_CURVE('P0_E884',#698,#722,#720,.T.);
#724=ORIENTED_EDGE('',*,*,#723,.T.);
#725=DIRECTION('',(1.,0.,0.));
#726=VECTOR('',#725,1.);
#727=CARTESIAN_POINT('',(20.9,-4.94241850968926,26.8462));
#728=LINE('',#727,#726);
#729=EDGE_CURVE('P0_E1602',#722,#387,#728,.T.);
#730=ORIENTED_EDGE('',*,*,#729,.T.);
#731=EDGE_LOOP('',(#715,#716,#724,#730));
#732=FACE_BOUND('',#731,.T.);
#733=ADVANCED_FACE('P0_F1732',(#732),#714,.T.);
#734=CARTESIAN_POINT('',(20.9,-4.94241850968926,26.8462));
#735=DIRECTION('',(0.,0.,-1.));
#736=DIRECTION('',(0.,-1.,0.));
#737=AXIS2_PLACEMENT_3D('',#734,#735,#736);
#738=PLANE('',#737);
#739=ORIENTED_EDGE('',*,*,#396,.F.);
#740=ORIENTED_EDGE('',*,*,#729,.F.);
#741=DIRECTION('',(0.,1.,0.));
#742=VECTOR('',#741,1.);
#743=CARTESIAN_POINT('',(20.9,-4.94241850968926,26.8462));
#744=LINE('',#743,#742);
#745=CARTESIAN_POINT('',(20.9,-3.21521850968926,26.8462));
#746=VERTEX_POINT('',#745);
#747=EDGE_CURVE('P0_E878',#722,#746,#744,.T.);
#748=ORIENTED_EDGE('',*,*,#747,.T.);
#749=DIRECTION('',(1.,0.,0.));
#750=VECTOR('',#749,1.);
#751=CARTESIAN_POINT('',(20.9,-3.21521850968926,26.8462));
#752=LINE('',#751,#750);
#753=EDGE_CURVE('P0_E1007',#746,#395,#752,.T.);
#754=ORIENTED_EDGE('',*,*,#753,.T.);
#755=EDGE_LOOP('',(#739,#740,#748,#754));
#756=FACE_BOUND('',#755,.T.);
#757=ADVANCED_FACE('P0_F1731',(#756),#738,.T.);
#758=CARTESIAN_POINT('',(20.9,-3.21521850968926,26.8462));
#759=DIRECTION('',(0.,-1.,0.));
#760=DIRECTION('',(0.,0.,-1.));
#761=AXIS2_PLACEMENT_3D('',#758,#759,#760);
#762=PLANE('',#761);
#763=ORIENTED_EDGE('',*,*,#404,.F.);
#764=ORIENTED_EDGE('',*,*,#753,.F.);
#765=DIRECTION('',(0.,0.,-1.));
#766=VECTOR('',#765,1.);
#767=CARTESIAN_POINT('',(20.9,-3.21521850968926,26.8462));
#768=LINE('',#767,#766);
#769=CARTESIAN_POINT('',(20.9,-3.21521850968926,26.1943));
#770=VERTEX_POINT('',#769);
#771=EDGE_CURVE('P0_E841',#746,#770,#768,.T.);
#772=ORIENTED_EDGE('',*,*,#771,.T.);
#773=DIRECTION('',(1.,0.,0.));
#774=VECTOR('',#773,1.);
#775=CARTESIAN_POINT('',(20.9,-3.21521850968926,26.1943));
#776=LINE('',#775,#774);
#777=EDGE_CURVE('P0_E1009',#770,#403,#776,.T.);
#778=ORIENTED_EDGE('',*,*,#777,.T.);
#779=EDGE_LOOP('',(#763,#764,#772,#778));
#780=FACE_BOUND('',#779,.T.);
#781=ADVANCED_FACE('P0_F1947',(#780),#762,.T.);
#782=CARTESIAN_POINT('',(20.9,-3.21521850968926,26.1943));
#783=DIRECTION('',(0.,0.,-1.));
#784=DIRECTION('',(0.,-1.,0.));
#785=AXIS2_PLACEMENT_3D('',#782,#783,#784);
#786=PLANE('',#785);
#787=ORIENTED_EDGE('',*,*,#410,.F.);
#788=ORIENTED_EDGE('',*,*,#777,.F.);
#789=DIRECTION('',(0.,1.,0.));
#790=VECTOR('',#789,1.);
#791=CARTESIAN_POINT('',(20.9,-3.21521850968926,26.1943));
#792=LINE('',#791,#790);
#793=CARTESIAN_POINT('',(20.9,-2.69881850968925,26.1943));
#794=VERTEX_POINT('',#793);
#795=EDGE_CURVE('P0_E838',#770,#794,#792,.T.);
#796=ORIENTED_EDGE('',*,*,#795,.T.);
#797=DIRECTION('',(1.,0.,0.));
#798=VECTOR('',#797,1.);
#799=CARTESIAN_POINT('',(20.9,-2.69881850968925,26.1943));
#800=LINE('',#799,#798);
#801=EDGE_CURVE('P0_E1585',#794,#353,#800,.T.);
#802=ORIENTED_EDGE('',*,*,#801,.T.);
#803=EDGE_LOOP('',(#787,#788,#796,#802));
#804=FACE_BOUND('',#803,.T.);
#805=ADVANCED_FACE('P0_F1944',(#804),#786,.T.);
#806=CARTESIAN_POINT('',(20.9,-2.69881850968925,26.1943));
#807=DIRECTION('',(0.,1.,0.));
#808=DIRECTION('',(1.,0.,0.));
#809=AXIS2_PLACEMENT_3D('',#806,#807,#808);
#810=PLANE('',#809);
#811=ORIENTED_EDGE('',*,*,#356,.F.);
#812=ORIENTED_EDGE('',*,*,#801,.F.);
#813=DIRECTION('',(0.,0.,1.));
#814=VECTOR('',#813,1.);
#815=CARTESIAN_POINT('',(20.9,-2.69881850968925,26.1943));
#816=LINE('',#815,#814);
#817=EDGE_CURVE('P0_E1211',#794,#642,#816,.T.);
#818=ORIENTED_EDGE('',*,*,#817,.T.);
#819=ORIENTED_EDGE('',*,*,#643,.T.);
#820=EDGE_LOOP('',(#811,#812,#818,#819));
#821=FACE_BOUND('',#820,.T.);
#822=ADVANCED_FACE('P0_F1892',(#821),#810,.T.);
#823=CARTESIAN_POINT('',(20.9,1.85608149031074,26.0587));
#824=CARTESIAN_POINT('',(21.,1.85608149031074,26.0587));
#825=CARTESIAN_POINT('',(20.9,4.02578149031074,26.0587));
#826=CARTESIAN_POINT('',(21.,4.02578149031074,26.0587));
#827=CARTESIAN_POINT('',(20.9,5.78458149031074,27.8178));
#828=CARTESIAN_POINT('',(21.,5.78458149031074,27.8178));
#829=CARTESIAN_POINT('',(20.9,5.78458149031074,29.9874));
#830=CARTESIAN_POINT('',(21.,5.78458149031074,29.9874));
#831=(BOUNDED_SURFACE() B_SPLINE_SURFACE(3,1,((#823,#824),(#825,#826),(#827,#828),(#829,#830)),
.UNSPECIFIED.,.F.,.F.,.F.) B_SPLINE_SURFACE_WITH_KNOTS((4,4),(2,2),(0.1875,0.25),(0.,1.),
.UNSPECIFIED.) GEOMETRIC_REPRESENTATION_ITEM() RATIONAL_B_SPLINE_SURFACE(((1.,1.),(1.,1.),(1.,
1.),(1.,1.))) REPRESENTATION_ITEM('') SURFACE());
#832=DIRECTION('',(1.,0.,0.));
#833=VECTOR('',#832,1.);
#834=CARTESIAN_POINT('',(20.9,1.85608149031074,26.0587));
#835=LINE('',#834,#833);
#836=CARTESIAN_POINT('',(20.9,1.85608149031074,26.0587));
#837=VERTEX_POINT('',#836);
#838=EDGE_CURVE('P0_E1463',#837,#220,#835,.T.);
#839=CARTESIAN_POINT('',(20.9,1.85608149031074,26.0587));
#840=CARTESIAN_POINT('',(20.9,4.02578149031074,26.0587));
#841=CARTESIAN_POINT('',(20.9,5.78458149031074,27.8178));
#842=CARTESIAN_POINT('',(20.9,5.78458149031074,29.9874));
#843=(BOUNDED_CURVE() B_SPLINE_CURVE(3,(#839,#840,#841,#842),.UNSPECIFIED.,.F.,
.F.) B_SPLINE_CURVE_WITH_KNOTS((4,4),(0.1875,0.25),
.UNSPECIFIED.) CURVE() GEOMETRIC_REPRESENTATION_ITEM() RATIONAL_B_SPLINE_CURVE((1.,1.,1.,1.)) REPRESENTATION_ITEM(''));
#844=CARTESIAN_POINT('',(20.9,5.78458149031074,29.9874));
#845=VERTEX_POINT('',#844);
#846=EDGE_CURVE('P0_E1268',#837,#845,#843,.T.);
#847=DIRECTION('',(1.,0.,0.));
#848=VECTOR('',#847,1.);
#849=CARTESIAN_POINT('',(20.9,5.78458149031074,29.9874));
#850=LINE('',#849,#848);
#851=EDGE_CURVE('P0_E1562',#845,#229,#850,.T.);
#852=ORIENTED_EDGE('',*,*,#230,.F.);
#853=ORIENTED_EDGE('',*,*,#838,.F.);
#854=ORIENTED_EDGE('',*,*,#846,.T.);
#855=ORIENTED_EDGE('',*,*,#851,.T.);
#856=EDGE_LOOP('',(#852,#853,#854,#855));
#857=FACE_BOUND('',#856,.T.);
#858=ADVANCED_FACE('P0_F1886',(#857),#831,.T.);
#859=CARTESIAN_POINT('',(20.9,5.78458149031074,29.9874));
#860=CARTESIAN_POINT('',(21.,5.78458149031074,29.9874));
#861=CARTESIAN_POINT('',(20.9,5.78458149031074,32.1568));
#862=CARTESIAN_POINT('',(21.,5.78458149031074,32.1568));
#863=CARTESIAN_POINT('',(20.9,4.02578149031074,33.9159));
#864=CARTESIAN_POINT('',(21.,4.02578149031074,33.9159));
#865=CARTESIAN_POINT('',(20.9,1.85608149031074,33.9159));
#866=CARTESIAN_POINT('',(21.,1.85608149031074,33.9159));
#867=(BOUNDED_SURFACE() B_SPLINE_SURFACE(3,1,((#859,#860),(#861,#862),(#863,#864),(#865,#866)),
.UNSPECIFIED.,.F.,.F.,.F.) B_SPLINE_SURFACE_WITH_KNOTS((4,4),(2,2),(0.25,0.3125),(0.,1.),
.UNSPECIFIED.) GEOMETRIC_REPRESENTATION_ITEM() RATIONAL_B_SPLINE_SURFACE(((1.,1.),(1.,1.),(1.,
1.),(1.,1.))) REPRESENTATION_ITEM('') SURFACE());
#868=CARTESIAN_POINT('',(20.9,5.78458149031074,29.9874));
#869=CARTESIAN_POINT('',(20.9,5.78458149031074,32.1568));
#870=CARTESIAN_POINT('',(20.9,4.02578149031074,33.9159));
#871=CARTESIAN_POINT('',(20.9,1.85608149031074,33.9159));
#872=(BOUNDED_CURVE() B_SPLINE_CURVE(3,(#868,#869,#870,#871),.UNSPECIFIED.,.F.,
.F.) B_SPLINE_CURVE_WITH_KNOTS((4,4),(0.25,0.3125),
.UNSPECIFIED.) CURVE() GEOMETRIC_REPRESENTATION_ITEM() RATIONAL_B_SPLINE_CURVE((1.,1.,1.,1.)) REPRESENTATION_ITEM(''));
#873=CARTESIAN_POINT('',(20.9,1.85608149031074,33.9159));
#874=VERTEX_POINT('',#873);
#875=EDGE_CURVE('P0_E1261',#845,#874,#872,.T.);
#876=DIRECTION('',(1.,0.,0.));
#877=VECTOR('',#876,1.);
#878=CARTESIAN_POINT('',(20.9,1.85608149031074,33.9159));
#879=LINE('',#878,#877);
#880=EDGE_CURVE('P0_E1551',#874,#238,#879,.T.);
#881=ORIENTED_EDGE('',*,*,#239,.F.);
#882=ORIENTED_EDGE('',*,*,#851,.F.);
#883=ORIENTED_EDGE('',*,*,#875,.T.);
#884=ORIENTED_EDGE('',*,*,#880,.T.);
#885=EDGE_LOOP('',(#881,#882,#883,#884));
#886=FACE_BOUND('',#885,.T.);
#887=ADVANCED_FACE('P0_F1895',(#886),#867,.T.);
#888=CARTESIAN_POINT('',(20.9,1.85608149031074,33.9159));
#889=CARTESIAN_POINT('',(21.,1.85608149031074,33.9159));
#890=CARTESIAN_POINT('',(20.9,-0.231118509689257,33.9159));
#891=CARTESIAN_POINT('',(21.,-0.231118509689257,33.9159));
#892=CARTESIAN_POINT('',(20.9,-1.93761850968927,32.288));
#893=CARTESIAN_POINT('',(21.,-1.93761850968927,32.288));
#894=CARTESIAN_POINT('',(20.9,-2.06441850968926,30.2328));
#895=CARTESIAN_POINT('',(21.,-2.06441850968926,30.2328));
#896=(BOUNDED_SURFACE() B_SPLINE_SURFACE(3,1,((#888,#889),(#890,#891),(#892,#893),(#894,#895)),
.UNSPECIFIED.,.F.,.F.,.F.) B_SPLINE_SURFACE_WITH_KNOTS((4,4),(2,2),(0.3125,0.375),(0.,1.),
.UNSPECIFIED.) GEOMETRIC_REPRESENTATION_ITEM() RATIONAL_B_SPLINE_SURFACE(((1.,1.),(1.,1.),(1.,
1.),(1.,1.))) REPRESENTATION_ITEM('') SURFACE());
#897=CARTESIAN_POINT('',(20.9,1.85608149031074,33.9159));
#898=CARTESIAN_POINT('',(20.9,-0.231118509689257,33.9159));
#899=CARTESIAN_POINT('',(20.9,-1.93761850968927,32.288));
#900=CARTESIAN_POINT('',(20.9,-2.06441850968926,30.2328));
#901=(BOUNDED_CURVE() B_SPLINE_CURVE(3,(#897,#898,#899,#900),.UNSPECIFIED.,.F.,
.F.) B_SPLINE_CURVE_WITH_KNOTS((4,4),(0.3125,0.375),
.UNSPECIFIED.) CURVE() GEOMETRIC_REPRESENTATION_ITEM() RATIONAL_B_SPLINE_CURVE((1.,1.,1.,1.)) REPRESENTATION_ITEM(''));
#902=CARTESIAN_POINT('',(20.9,-2.06441850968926,30.2328));
#903=VERTEX_POINT('',#902);
#904=EDGE_CURVE('P0_E1254',#874,#903,#901,.T.);
#905=DIRECTION('',(1.,0.,0.));
#906=VECTOR('',#905,1.);
#907=CARTESIAN_POINT('',(20.9,-2.06441850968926,30.2328));
#908=LINE('',#907,#906);
#909=EDGE_CURVE('P0_E1545',#903,#247,#908,.T.);
#910=ORIENTED_EDGE('',*,*,#248,.F.);
#911=ORIENTED_EDGE('',*,*,#880,.F.);
#912=ORIENTED_EDGE('',*,*,#904,.T.);
#913=ORIENTED_EDGE('',*,*,#909,.T.);
#914=EDGE_LOOP('',(#910,#911,#912,#913));
#915=FACE_BOUND('',#914,.T.);
#916=ADVANCED_FACE('P0_F1922',(#915),#896,.T.);
#917=CARTESIAN_POINT('',(20.9,-2.06441850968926,30.2328));
#918=DIRECTION('',(0.,0.,-1.));
#919=DIRECTION('',(0.,-1.,0.));
#920=AXIS2_PLACEMENT_3D('',#917,#918,#919);
#921=PLANE('',#920);
#922=ORIENTED_EDGE('',*,*,#256,.F.);
#923=ORIENTED_EDGE('',*,*,#909,.F.);
#924=DIRECTION('',(0.,1.,0.));
#925=VECTOR('',#924,1.);
#926=CARTESIAN_POINT('',(20.9,-2.06441850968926,30.2328));
#927=LINE('',#926,#925);
#928=CARTESIAN_POINT('',(20.9,-0.175218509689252,30.2328));
#929=VERTEX_POINT('',#928);
#930=EDGE_CURVE('P0_E1251',#903,#929,#927,.T.);
#931=ORIENTED_EDGE('',*,*,#930,.T.);
#932=DIRECTION('',(1.,0.,0.));
#933=VECTOR('',#932,1.);
#934=CARTESIAN_POINT('',(20.9,-0.175218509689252,30.2328));
#935=LINE('',#934,#933);
#936=EDGE_CURVE('P0_E1534',#929,#255,#935,.T.);
#937=ORIENTED_EDGE('',*,*,#936,.T.);
#938=EDGE_LOOP('',(#922,#923,#931,#937));
#939=FACE_BOUND('',#938,.T.);
#940=ADVANCED_FACE('P0_F1800',(#939),#921,.T.);
#941=CARTESIAN_POINT('',(20.9,-0.175218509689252,30.2328));
#942=DIRECTION('',(0.,1.,0.));
#943=DIRECTION('',(1.,0.,0.));
#944=AXIS2_PLACEMENT_3D('',#941,#942,#943);
#945=PLANE('',#944);
#946=ORIENTED_EDGE('',*,*,#264,.F.);
#947=ORIENTED_EDGE('',*,*,#936,.F.);
#948=DIRECTION('',(0.,0.,1.));
#949=VECTOR('',#948,1.);
#950=CARTESIAN_POINT('',(20.9,-0.175218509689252,30.2328));
#951=LINE('',#950,#949);
#952=CARTESIAN_POINT('',(20.9,-0.175218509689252,31.5695));
#953=VERTEX_POINT('',#952);
#954=EDGE_CURVE('P0_E1119',#929,#953,#951,.T.);
#955=ORIENTED_EDGE('',*,*,#954,.T.);
#956=DIRECTION('',(1.,0.,0.));
#957=VECTOR('',#956,1.);
#958=CARTESIAN_POINT('',(20.9,-0.175218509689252,31.5695));
#959=LINE('',#958,#957);
#960=EDGE_CURVE('P0_E1522',#953,#263,#959,.T.);
#961=ORIENTED_EDGE('',*,*,#960,.T.);
#962=EDGE_LOOP('',(#946,#947,#955,#961));
#963=FACE_BOUND('',#962,.T.);
#964=ADVANCED_FACE('P0_F1791',(#963),#945,.T.);
#965=CARTESIAN_POINT('',(20.9,-0.175218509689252,31.5695));
#966=CARTESIAN_POINT('',(21.,-0.175218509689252,31.5695));
#967=CARTESIAN_POINT('',(20.9,-0.175218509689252,31.7375));
#968=CARTESIAN_POINT('',(21.,-0.175218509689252,31.7375));
#969=CARTESIAN_POINT('',(20.9,-0.0379185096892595,31.8747));
#970=CARTESIAN_POINT('',(21.,-0.0379185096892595,31.8747));
#971=CARTESIAN_POINT('',(20.9,0.129781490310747,31.8747));
#972=CARTESIAN_POINT('',(21.,0.129781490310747,31.8747));
#973=(BOUNDED_SURFACE() B_SPLINE_SURFACE(3,1,((#965,#966),(#967,#968),(#969,#970),(#971,#972)),
.UNSPECIFIED.,.F.,.F.,.F.) B_SPLINE_SURFACE_WITH_KNOTS((4,4),(2,2),(0.5,0.5625),(0.,1.),
.UNSPECIFIED.) GEOMETRIC_REPRESENTATION_ITEM() RATIONAL_B_SPLINE_SURFACE(((1.,1.),(1.,1.),(1.,
1.),(1.,1.))) REPRESENTATION_ITEM('') SURFACE());
#974=CARTESIAN_POINT('',(20.9,-0.175218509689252,31.5695));
#975=CARTESIAN_POINT('',(20.9,-0.175218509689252,31.7375));
#976=CARTESIAN_POINT('',(20.9,-0.0379185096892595,31.8747));
#977=CARTESIAN_POINT('',(20.9,0.129781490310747,31.8747));
#978=(BOUNDED_CURVE() B_SPLINE_CURVE(3,(#974,#975,#976,#977),.UNSPECIFIED.,.F.,
.F.) B_SPLINE_CURVE_WITH_KNOTS((4,4),(0.5,0.5625),
.UNSPECIFIED.) CURVE() GEOMETRIC_REPRESENTATION_ITEM() RATIONAL_B_SPLINE_CURVE((1.,1.,1.,1.)) REPRESENTATION_ITEM(''));
#979=CARTESIAN_POINT('',(20.9,0.129781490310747,31.8747));
#980=VERTEX_POINT('',#979);
#981=EDGE_CURVE('P0_E1112',#953,#980,#978,.T.);
#982=DIRECTION('',(1.,0.,0.));
#983=VECTOR('',#982,1.);
#984=CARTESIAN_POINT('',(20.9,0.129781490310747,31.8747));
#985=LINE('',#984,#983);
#986=EDGE_CURVE('P0_E1518',#980,#272,#985,.T.);
#987=ORIENTED_EDGE('',*,*,#273,.F.);
#988=ORIENTED_EDGE('',*,*,#960,.F.);
#989=ORIENTED_EDGE('',*,*,#981,.T.);
#990=ORIENTED_EDGE('',*,*,#986,.T.);
#991=EDGE_LOOP('',(#987,#988,#989,#990));
#992=FACE_BOUND('',#991,.T.);
#993=ADVANCED_FACE('P0_F1798',(#992),#973,.T.);
#994=CARTESIAN_POINT('',(20.9,0.129781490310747,31.8747));
#995=DIRECTION('',(0.,0.,-1.));
#996=DIRECTION('',(0.,-1.,0.));
#997=AXIS2_PLACEMENT_3D('',#994,#995,#996);
#998=PLANE('',#997);
#999=ORIENTED_EDGE('',*,*,#281,.F.);
#1000=ORIENTED_EDGE('',*,*,#986,.F.);
#1001=DIRECTION('',(0.,1.,0.));
#1002=VECTOR('',#1001,1.);
#1003=CARTESIAN_POINT('',(20.9,0.129781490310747,31.8747));
#1004=LINE('',#1003,#1002);
#1005=CARTESIAN_POINT('',(20.9,3.29448149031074,31.8747));
#1006=VERTEX_POINT('',#1005);
#1007=EDGE_CURVE('P0_E909',#980,#1006,#1004,.T.);
#1008=ORIENTED_EDGE('',*,*,#1007,.T.);
#1009=DIRECTION('',(1.,0.,0.));
#1010=VECTOR('',#1009,1.);
#1011=CARTESIAN_POINT('',(20.9,3.29448149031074,31.8747));
#1012=LINE('',#1011,#1010);
#1013=EDGE_CURVE('P0_E734',#1006,#280,#1012,.T.);
#1014=ORIENTED_EDGE('',*,*,#1013,.T.);
#1015=EDGE_LOOP('',(#999,#1000,#1008,#1014));
#1016=FACE_BOUND('',#1015,.T.);
#1017=ADVANCED_FACE('P0_F2056',(#1016),#998,.T.);
#1018=CARTESIAN_POINT('',(20.9,3.29448149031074,31.8747));
#1019=CARTESIAN_POINT('',(21.,3.29448149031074,31.8747));
#1020=CARTESIAN_POINT('',(20.9,3.46218149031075,31.8747));
#1021=CARTESIAN_POINT('',(21.,3.46218149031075,31.8747));
#1022=CARTESIAN_POINT('',(20.9,3.59968149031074,31.7375));
#1023=CARTESIAN_POINT('',(21.,3.59968149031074,31.7375));
#1024=CARTESIAN_POINT('',(20.9,3.59968149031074,31.5695));
#1025=CARTESIAN_POINT('',(21.,3.59968149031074,31.5695));
#1026=(BOUNDED_SURFACE() B_SPLINE_SURFACE(3,1,((#1018,#1019),(#1020,#1021),(#1022,#1023),(#1024,
#1025)),.UNSPECIFIED.,.F.,.F.,.F.) B_SPLINE_SURFACE_WITH_KNOTS((4,4),(2,2),(0.625,0.6875),(0.,
1.),.UNSPECIFIED.) GEOMETRIC_REPRESENTATION_ITEM() RATIONAL_B_SPLINE_SURFACE(((1.,1.),(1.,1.),
(1.,1.),(1.,1.))) REPRESENTATION_ITEM('') SURFACE());
#1027=CARTESIAN_POINT('',(20.9,3.29448149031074,31.8747));
#1028=CARTESIAN_POINT('',(20.9,3.46218149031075,31.8747));
#1029=CARTESIAN_POINT('',(20.9,3.59968149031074,31.7375));
#1030=CARTESIAN_POINT('',(20.9,3.59968149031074,31.5695));
#1031=(BOUNDED_CURVE() B_SPLINE_CURVE(3,(#1027,#1028,#1029,#1030),.UNSPECIFIED.,.F.,
.F.) B_SPLINE_CURVE_WITH_KNOTS((4,4),(0.625,0.6875),
.UNSPECIFIED.) CURVE() GEOMETRIC_REPRESENTATION_ITEM() RATIONAL_B_SPLINE_CURVE((1.,1.,1.,1.)) REPRESENTATION_ITEM(''));
#1032=CARTESIAN_POINT('',(20.9,3.59968149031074,31.5695));
#1033=VERTEX_POINT('',#1032);
#1034=EDGE_CURVE('P0_E905',#1006,#1033,#1031,.T.);
#1035=DIRECTION('',(1.,0.,0.));
#1036=VECTOR('',#1035,1.);
#1037=CARTESIAN_POINT('',(20.9,3.59968149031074,31.5695));
#1038=LINE('',#1037,#1036);
#1039=EDGE_CURVE('P0_E736',#1033,#289,#1038,.T.);
#1040=ORIENTED_EDGE('',*,*,#290,.F.);
#1041=ORIENTED_EDGE('',*,*,#1013,.F.);
#1042=ORIENTED_EDGE('',*,*,#1034,.T.);
#1043=ORIENTED_EDGE('',*,*,#1039,.T.);
#1044=EDGE_LOOP('',(#1040,#1041,#1042,#1043));
#1045=FACE_BOUND('',#1044,.T.);
#1046=ADVANCED_FACE('P0_F2049',(#1045),#1026,.T.);
#1047=CARTESIAN_POINT('',(20.9,3.59968149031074,31.5695));
#1048=DIRECTION('',(0.,-1.,0.));
#1049=DIRECTION('',(0.,0.,-1.));
#1050=AXIS2_PLACEMENT_3D('',#1047,#1048,#1049);
#1051=PLANE('',#1050);
#1052=ORIENTED_EDGE('',*,*,#298,.F.);
#1053=ORIENTED_EDGE('',*,*,#1039,.F.);
#1054=DIRECTION('',(0.,0.,-1.));
#1055=VECTOR('',#1054,1.);
#1056=CARTESIAN_POINT('',(20.9,3.59968149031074,31.5695));
#1057=LINE('',#1056,#1055);
#1058=CARTESIAN_POINT('',(20.9,3.59968149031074,28.4051));
#1059=VERTEX_POINT('',#1058);
#1060=EDGE_CURVE('P0_E906',#1033,#1059,#1057,.T.);
#1061=ORIENTED_EDGE('',*,*,#1060,.T.);
#1062=DIRECTION('',(1.,0.,0.));
#1063=VECTOR('',#1062,1.);
#1064=CARTESIAN_POINT('',(20.9,3.59968149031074,28.4051));
#1065=LINE('',#1064,#1063);
#1066=EDGE_CURVE('P0_E1022',#1059,#297,#1065,.T.);
#1067=ORIENTED_EDGE('',*,*,#1066,.T.);
#1068=EDGE_LOOP('',(#1052,#1053,#1061,#1067));
#1069=FACE_BOUND('',#1068,.T.);
#1070=ADVANCED_FACE('P0_F2050',(#1069),#1051,.T.);
#1071=CARTESIAN_POINT('',(20.9,3.59968149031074,28.4051));
#1072=CARTESIAN_POINT('',(21.,3.59968149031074,28.4051));
#1073=CARTESIAN_POINT('',(20.9,3.59968149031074,28.2371));
#1074=CARTESIAN_POINT('',(21.,3.59968149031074,28.2371));
#1075=CARTESIAN_POINT('',(20.9,3.46218149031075,28.0999));
#1076=CARTESIAN_POINT('',(21.,3.46218149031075,28.0999));
#1077=CARTESIAN_POINT('',(20.9,3.29448149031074,28.0999));
#1078=CARTESIAN_POINT('',(21.,3.29448149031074,28.0999));
#1079=(BOUNDED_SURFACE() B_SPLINE_SURFACE(3,1,((#1071,#1072),(#1073,#1074),(#1075,#1076),(#1077,
#1078)),.UNSPECIFIED.,.F.,.F.,.F.) B_SPLINE_SURFACE_WITH_KNOTS((4,4),(2,2),(0.75,0.8125),(0.,
1.),.UNSPECIFIED.) GEOMETRIC_REPRESENTATION_ITEM() RATIONAL_B_SPLINE_SURFACE(((1.,1.),(1.,1.),
(1.,1.),(1.,1.))) REPRESENTATION_ITEM('') SURFACE());
#1080=CARTESIAN_POINT('',(20.9,3.59968149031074,28.4051));
#1081=CARTESIAN_POINT('',(20.9,3.59968149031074,28.2371));
#1082=CARTESIAN_POINT('',(20.9,3.46218149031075,28.0999));
#1083=CARTESIAN_POINT('',(20.9,3.29448149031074,28.0999));
#1084=(BOUNDED_CURVE() B_SPLINE_CURVE(3,(#1080,#1081,#1082,#1083),.UNSPECIFIED.,.F.,
.F.) B_SPLINE_CURVE_WITH_KNOTS((4,4),(0.75,0.8125),
.UNSPECIFIED.) CURVE() GEOMETRIC_REPRESENTATION_ITEM() RATIONAL_B_SPLINE_CURVE((1.,1.,1.,1.)) REPRESENTATION_ITEM(''));
#1085=CARTESIAN_POINT('',(20.9,3.29448149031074,28.0999));
#1086=VERTEX_POINT('',#1085);
#1087=EDGE_CURVE('P0_E1232',#1059,#1086,#1084,.T.);
#1088=DIRECTION('',(1.,0.,0.));
#1089=VECTOR('',#1088,1.);
#1090=CARTESIAN_POINT('',(20.9,3.29448149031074,28.0999));
#1091=LINE('',#1090,#1089);
#1092=EDGE_CURVE('P0_E1493',#1086,#306,#1091,.T.);
#1093=ORIENTED_EDGE('',*,*,#307,.F.);
#1094=ORIENTED_EDGE('',*,*,#1066,.F.);
#1095=ORIENTED_EDGE('',*,*,#1087,.T.);
#1096=ORIENTED_EDGE('',*,*,#1092,.T.);
#1097=EDGE_LOOP('',(#1093,#1094,#1095,#1096));
#1098=FACE_BOUND('',#1097,.T.);
#1099=ADVANCED_FACE('P0_F1689',(#1098),#1079,.T.);
#1100=CARTESIAN_POINT('',(20.9,3.29448149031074,28.0999));
#1101=DIRECTION('',(0.,0.,1.));
#1102=DIRECTION('',(1.,0.,0.));
#1103=AXIS2_PLACEMENT_3D('',#1100,#1101,#1102);
#1104=PLANE('',#1103);
#1105=ORIENTED_EDGE('',*,*,#315,.F.);
#1106=ORIENTED_EDGE('',*,*,#1092,.F.);
#1107=DIRECTION('',(0.,-1.,0.));
#1108=VECTOR('',#1107,1.);
#1109=CARTESIAN_POINT('',(20.9,3.29448149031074,28.0999));
#1110=LINE('',#1109,#1108);
#1111=CARTESIAN_POINT('',(20.9,0.129781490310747,28.0999));
#1112=VERTEX_POINT('',#1111);
#1113=EDGE_CURVE('P0_E1230',#1086,#1112,#1110,.T.);
#1114=ORIENTED_EDGE('',*,*,#1113,.T.);
#1115=DIRECTION('',(1.,0.,0.));
#1116=VECTOR('',#1115,1.);
#1117=CARTESIAN_POINT('',(20.9,0.129781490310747,28.0999));
#1118=LINE('',#1117,#1116);
#1119=EDGE_CURVE('P0_E1483',#1112,#314,#1118,.T.);
#1120=ORIENTED_EDGE('',*,*,#1119,.T.);
#1121=EDGE_LOOP('',(#1105,#1106,#1114,#1120));
#1122=FACE_BOUND('',#1121,.T.);
#1123=ADVANCED_FACE('P0_F2040',(#1122),#1104,.T.);
#1124=CARTESIAN_POINT('',(20.9,0.129781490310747,28.0999));
#1125=CARTESIAN_POINT('',(21.,0.129781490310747,28.0999));
#1126=CARTESIAN_POINT('',(20.9,-0.0379185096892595,28.0999));
#1127=CARTESIAN_POINT('',(21.,-0.0379185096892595,28.0999));
#1128=CARTESIAN_POINT('',(20.9,-0.175218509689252,28.2371));
#1129=CARTESIAN_POINT('',(21.,-0.175218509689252,28.2371));
#1130=CARTESIAN_POINT('',(20.9,-0.175218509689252,28.4051));
#1131=CARTESIAN_POINT('',(21.,-0.175218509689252,28.4051));
#1132=(BOUNDED_SURFACE() B_SPLINE_SURFACE(3,1,((#1124,#1125),(#1126,#1127),(#1128,#1129),(#1130,
#1131)),.UNSPECIFIED.,.F.,.F.,.F.) B_SPLINE_SURFACE_WITH_KNOTS((4,4),(2,2),(0.875,0.9375),(0.,
1.),.UNSPECIFIED.) GEOMETRIC_REPRESENTATION_ITEM() RATIONAL_B_SPLINE_SURFACE(((1.,1.),(1.,1.),
(1.,1.),(1.,1.))) REPRESENTATION_ITEM('') SURFACE());
#1133=CARTESIAN_POINT('',(20.9,0.129781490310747,28.0999));
#1134=CARTESIAN_POINT('',(20.9,-0.0379185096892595,28.0999));
#1135=CARTESIAN_POINT('',(20.9,-0.175218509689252,28.2371));
#1136=CARTESIAN_POINT('',(20.9,-0.175218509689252,28.4051));
#1137=(BOUNDED_CURVE() B_SPLINE_CURVE(3,(#1133,#1134,#1135,#1136),.UNSPECIFIED.,.F.,
.F.) B_SPLINE_CURVE_WITH_KNOTS((4,4),(0.875,0.9375),
.UNSPECIFIED.) CURVE() GEOMETRIC_REPRESENTATION_ITEM() RATIONAL_B_SPLINE_CURVE((1.,1.,1.,1.)) REPRESENTATION_ITEM(''));
#1138=CARTESIAN_POINT('',(20.9,-0.175218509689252,28.4051));
#1139=VERTEX_POINT('',#1138);
#1140=EDGE_CURVE('P0_E1036',#1112,#1139,#1137,.T.);
#1141=DIRECTION('',(1.,0.,0.));
#1142=VECTOR('',#1141,1.);
#1143=CARTESIAN_POINT('',(20.9,-0.175218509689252,28.4051));
#1144=LINE('',#1143,#1142);
#1145=EDGE_CURVE('P0_E1474',#1139,#323,#1144,.T.);
#1146=ORIENTED_EDGE('',*,*,#324,.F.);
#1147=ORIENTED_EDGE('',*,*,#1119,.F.);
#1148=ORIENTED_EDGE('',*,*,#1140,.T.);
#1149=ORIENTED_EDGE('',*,*,#1145,.T.);
#1150=EDGE_LOOP('',(#1146,#1147,#1148,#1149));
#1151=FACE_BOUND('',#1150,.T.);
#1152=ADVANCED_FACE('P0_F2031',(#1151),#1132,.T.);
#1153=CARTESIAN_POINT('',(20.9,-0.175218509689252,28.4051));
#1154=DIRECTION('',(0.,1.,0.));
#1155=DIRECTION('',(1.,0.,0.));
#1156=AXIS2_PLACEMENT_3D('',#1153,#1154,#1155);
#1157=PLANE('',#1156);
#1158=ORIENTED_EDGE('',*,*,#332,.F.);
#1159=ORIENTED_EDGE('',*,*,#1145,.F.);
#1160=DIRECTION('',(0.,0.,1.));
#1161=VECTOR('',#1160,1.);
#1162=CARTESIAN_POINT('',(20.9,-0.175218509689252,28.4051));
#1163=LINE('',#1162,#1161);
#1164=CARTESIAN_POINT('',(20.9,-0.175218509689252,29.7418));
#1165=VERTEX_POINT('',#1164);
#1166=EDGE_CURVE('P0_E1035',#1139,#1165,#1163,.T.);
#1167=ORIENTED_EDGE('',*,*,#1166,.T.);
#1168=DIRECTION('',(1.,0.,0.));
#1169=VECTOR('',#1168,1.);
#1170=CARTESIAN_POINT('',(20.9,-0.175218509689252,29.7418));
#1171=LINE('',#1170,#1169);
#1172=EDGE_CURVE('P0_E1466',#1165,#331,#1171,.T.);
#1173=ORIENTED_EDGE('',*,*,#1172,.T.);
#1174=EDGE_LOOP('',(#1158,#1159,#1167,#1173));
#1175=FACE_BOUND('',#1174,.T.);
#1176=ADVANCED_FACE('P0_F2022',(#1175),#1157,.T.);
#1177=CARTESIAN_POINT('',(20.9,-0.175218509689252,29.7418));
#1178=DIRECTION('',(0.,0.,1.));
#1179=DIRECTION('',(1.,0.,0.));
#1180=AXIS2_PLACEMENT_3D('',#1177,#1178,#1179);
#1181=PLANE('',#1180);
#1182=ORIENTED_EDGE('',*,*,#338,.F.);
#1183=ORIENTED_EDGE('',*,*,#1172,.F.);
#1184=DIRECTION('',(0.,-1.,0.));
#1185=VECTOR('',#1184,1.);
#1186=CARTESIAN_POINT('',(20.9,-0.175218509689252,29.7418));
#1187=LINE('',#1186,#1185);
#1188=CARTESIAN_POINT('',(20.9,-2.06441850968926,29.7418));
#1189=VERTEX_POINT('',#1188);
#1190=EDGE_CURVE('P0_E1040',#1165,#1189,#1187,.T.);
#1191=ORIENTED_EDGE('',*,*,#1190,.T.);
#1192=DIRECTION('',(1.,0.,0.));
#1193=VECTOR('',#1192,1.);
#1194=CARTESIAN_POINT('',(20.9,-2.06441850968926,29.7418));
#1195=LINE('',#1194,#1193);
#1196=EDGE_CURVE('P0_E1453',#1189,#218,#1195,.T.);
#1197=ORIENTED_EDGE('',*,*,#1196,.T.);
#1198=EDGE_LOOP('',(#1182,#1183,#1191,#1197));
#1199=FACE_BOUND('',#1198,.T.);
#1200=ADVANCED_FACE('P0_F2014',(#1199),#1181,.T.);
#1201=CARTESIAN_POINT('',(20.9,-2.06441850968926,29.7418));
#1202=CARTESIAN_POINT('',(21.,-2.06441850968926,29.7418));
#1203=CARTESIAN_POINT('',(20.9,-1.93761850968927,27.6866));
#1204=CARTESIAN_POINT('',(21.,-1.93761850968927,27.6866));
#1205=CARTESIAN_POINT('',(20.9,-0.231118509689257,26.0587));
#1206=CARTESIAN_POINT('',(21.,-0.231118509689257,26.0587));
#1207=CARTESIAN_POINT('',(20.9,1.85608149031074,26.0587));
#1208=CARTESIAN_POINT('',(21.,1.85608149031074,26.0587));
#1209=(BOUNDED_SURFACE() B_SPLINE_SURFACE(3,1,((#1201,#1202),(#1203,#1204),(#1205,#1206),(#1207,
#1208)),.UNSPECIFIED.,.F.,.F.,.F.) B_SPLINE_SURFACE_WITH_KNOTS((4,4),(2,2),(0.125,0.1875),(0.,
1.),.UNSPECIFIED.) GEOMETRIC_REPRESENTATION_ITEM() RATIONAL_B_SPLINE_SURFACE(((1.,1.),(1.,1.),
(1.,1.),(1.,1.))) REPRESENTATION_ITEM('') SURFACE());
#1210=CARTESIAN_POINT('',(20.9,-2.06441850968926,29.7418));
#1211=CARTESIAN_POINT('',(20.9,-1.93761850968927,27.6866));
#1212=CARTESIAN_POINT('',(20.9,-0.231118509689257,26.0587));
#1213=CARTESIAN_POINT('',(20.9,1.85608149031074,26.0587));
#1214=(BOUNDED_CURVE() B_SPLINE_CURVE(3,(#1210,#1211,#1212,#1213),.UNSPECIFIED.,.F.,
.F.) B_SPLINE_CURVE_WITH_KNOTS((4,4),(0.125,0.1875),
.UNSPECIFIED.) CURVE() GEOMETRIC_REPRESENTATION_ITEM() RATIONAL_B_SPLINE_CURVE((1.,1.,1.,1.)) REPRESENTATION_ITEM(''));
#1215=EDGE_CURVE('P0_E994',#1189,#837,#1214,.T.);
#1216=ORIENTED_EDGE('',*,*,#221,.F.);
#1217=ORIENTED_EDGE('',*,*,#1196,.F.);
#1218=ORIENTED_EDGE('',*,*,#1215,.T.);
#1219=ORIENTED_EDGE('',*,*,#838,.T.);
#1220=EDGE_LOOP('',(#1216,#1217,#1218,#1219));
#1221=FACE_BOUND('',#1220,.T.);
#1222=ADVANCED_FACE('P0_F2003',(#1221),#1209,.T.);
#1223=CARTESIAN_POINT('',(20.9,-3.82921850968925,29.2382));
#1224=CARTESIAN_POINT('',(21.,-3.82921850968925,29.2382));
#1225=CARTESIAN_POINT('',(20.9,-4.16521850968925,29.2382));
#1226=CARTESIAN_POINT('',(21.,-4.16521850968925,29.2382));
#1227=CARTESIAN_POINT('',(20.9,-4.44041850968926,29.5131));
#1228=CARTESIAN_POINT('',(21.,-4.44041850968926,29.5131));
#1229=CARTESIAN_POINT('',(20.9,-4.44041850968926,29.8494));
#1230=CARTESIAN_POINT('',(21.,-4.44041850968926,29.8494));
#1231=(BOUNDED_SURFACE() B_SPLINE_SURFACE(3,1,((#1223,#1224),(#1225,#1226),(#1227,#1228),(#1229,
#1230)),.UNSPECIFIED.,.F.,.F.,.F.) B_SPLINE_SURFACE_WITH_KNOTS((4,4),(2,2),(0.5,0.5625),(0.,1.),
.UNSPECIFIED.) GEOMETRIC_REPRESENTATION_ITEM() RATIONAL_B_SPLINE_SURFACE(((1.,1.),(1.,1.),(1.,
1.),(1.,1.))) REPRESENTATION_ITEM('') SURFACE());
#1232=DIRECTION('',(1.,0.,0.));
#1233=VECTOR('',#1232,1.);
#1234=CARTESIAN_POINT('',(20.9,-3.82921850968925,29.2382));
#1235=LINE('',#1234,#1233);
#1236=CARTESIAN_POINT('',(20.9,-3.82921850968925,29.2382));
#1237=VERTEX_POINT('',#1236);
#1238=EDGE_CURVE('P0_E959',#1237,#112,#1235,.T.);
#1239=CARTESIAN_POINT('',(20.9,-3.82921850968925,29.2382));
#1240=CARTESIAN_POINT('',(20.9,-4.16521850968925,29.2382));
#1241=CARTESIAN_POINT('',(20.9,-4.44041850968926,29.5131));
#1242=CARTESIAN_POINT('',(20.9,-4.44041850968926,29.8494));
#1243=(BOUNDED_CURVE() B_SPLINE_CURVE(3,(#1239,#1240,#1241,#1242),.UNSPECIFIED.,.F.,
.F.) B_SPLINE_CURVE_WITH_KNOTS((4,4),(0.5,0.5625),
.UNSPECIFIED.) CURVE() GEOMETRIC_REPRESENTATION_ITEM() RATIONAL_B_SPLINE_CURVE((1.,1.,1.,1.)) REPRESENTATION_ITEM(''));
#1244=CARTESIAN_POINT('',(20.9,-4.44041850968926,29.8494));
#1245=VERTEX_POINT('',#1244);
#1246=EDGE_CURVE('P0_E1323',#1237,#1245,#1243,.T.);
#1247=DIRECTION('',(1.,0.,0.));
#1248=VECTOR('',#1247,1.);
#1249=CARTESIAN_POINT('',(20.9,-4.44041850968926,29.8494));
#1250=LINE('',#1249,#1248);
#1251=EDGE_CURVE('P0_E1436',#1245,#121,#1250,.T.);
#1252=ORIENTED_EDGE('',*,*,#122,.F.);
#1253=ORIENTED_EDGE('',*,*,#1238,.F.);
#1254=ORIENTED_EDGE('',*,*,#1246,.T.);
#1255=ORIENTED_EDGE('',*,*,#1251,.T.);
#1256=EDGE_LOOP('',(#1252,#1253,#1254,#1255));
#1257=FACE_BOUND('',#1256,.T.);
#1258=ADVANCED_FACE('P0_F1998',(#1257),#1231,.T.);
#1259=CARTESIAN_POINT('',(20.9,-4.44041850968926,29.8494));
#1260=DIRECTION('',(0.,1.,0.));
#1261=DIRECTION('',(1.,0.,0.));
#1262=AXIS2_PLACEMENT_3D('',#1259,#1260,#1261);
#1263=PLANE('',#1262);
#1264=ORIENTED_EDGE('',*,*,#130,.F.);
#1265=ORIENTED_EDGE('',*,*,#1251,.F.);
#1266=DIRECTION('',(0.,0.,1.));
#1267=VECTOR('',#1266,1.);
#1268=CARTESIAN_POINT('',(20.9,-4.44041850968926,29.8494));
#1269=LINE('',#1268,#1267);
#1270=CARTESIAN_POINT('',(20.9,-4.44041850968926,30.));
#1271=VERTEX_POINT('',#1270);
#1272=EDGE_CURVE('P0_E1322',#1245,#1271,#1269,.T.);
#1273=ORIENTED_EDGE('',*,*,#1272,.T.);
#1274=DIRECTION('',(1.,0.,0.));
#1275=VECTOR('',#1274,1.);
#1276=CARTESIAN_POINT('',(20.9,-4.44041850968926,30.));
#1277=LINE('',#1276,#1275);
#1278=EDGE_CURVE('P0_E1428',#1271,#129,#1277,.T.);
#1279=ORIENTED_EDGE('',*,*,#1278,.T.);
#1280=EDGE_LOOP('',(#1264,#1265,#1273,#1279));
#1281=FACE_BOUND('',#1280,.T.);
#1282=ADVANCED_FACE('P0_F1992',(#1281),#1263,.T.);
#1283=CARTESIAN_POINT('',(20.9,-4.44041850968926,30.));
#1284=DIRECTION('',(0.,0.,1.));
#1285=DIRECTION('',(1.,0.,0.));
#1286=AXIS2_PLACEMENT_3D('',#1283,#1284,#1285);
#1287=PLANE('',#1286);
#1288=ORIENTED_EDGE('',*,*,#138,.F.);
#1289=ORIENTED_EDGE('',*,*,#1278,.F.);
#1290=DIRECTION('',(0.,-1.,0.));
#1291=VECTOR('',#1290,1.);
#1292=CARTESIAN_POINT('',(20.9,-4.44041850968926,30.));
#1293=LINE('',#1292,#1291);
#1294=CARTESIAN_POINT('',(20.9,-4.96361850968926,30.));
#1295=VERTEX_POINT('',#1294);
#1296=EDGE_CURVE('P0_E1320',#1271,#1295,#1293,.T.);
#1297=ORIENTED_EDGE('',*,*,#1296,.T.);
#1298=DIRECTION('',(1.,0.,0.));
#1299=VECTOR('',#1298,1.);
#1300=CARTESIAN_POINT('',(20.9,-4.96361850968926,30.));
#1301=LINE('',#1300,#1299);
#1302=EDGE_CURVE('P0_E1425',#1295,#137,#1301,.T.);
#1303=ORIENTED_EDGE('',*,*,#1302,.T.);
#1304=EDGE_LOOP('',(#1288,#1289,#1297,#1303));
#1305=FACE_BOUND('',#1304,.T.);
#1306=ADVANCED_FACE('P0_F1990',(#1305),#1287,.T.);
#1307=CARTESIAN_POINT('',(20.9,-4.96361850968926,30.));
#1308=DIRECTION('',(0.,-1.,0.));
#1309=DIRECTION('',(0.,0.,-1.));
#1310=AXIS2_PLACEMENT_3D('',#1307,#1308,#1309);
#1311=PLANE('',#1310);
#1312=ORIENTED_EDGE('',*,*,#146,.F.);
#1313=ORIENTED_EDGE('',*,*,#1302,.F.);
#1314=DIRECTION('',(0.,0.,-1.));
#1315=VECTOR('',#1314,1.);
#1316=CARTESIAN_POINT('',(20.9,-4.96361850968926,30.));
#1317=LINE('',#1316,#1315);
#1318=CARTESIAN_POINT('',(20.9,-4.96361850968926,29.8307));
#1319=VERTEX_POINT('',#1318);
#1320=EDGE_CURVE('P0_E1309',#1295,#1319,#1317,.T.);
#1321=ORIENTED_EDGE('',*,*,#1320,.T.);
#1322=DIRECTION('',(1.,0.,0.));
#1323=VECTOR('',#1322,1.);
#1324=CARTESIAN_POINT('',(20.9,-4.96361850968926,29.8307));
#1325=LINE('',#1324,#1323);
#1326=EDGE_CURVE('P0_E1415',#1319,#145,#1325,.T.);
#1327=ORIENTED_EDGE('',*,*,#1326,.T.);
#1328=EDGE_LOOP('',(#1312,#1313,#1321,#1327));
#1329=FACE_BOUND('',#1328,.T.);
#1330=ADVANCED_FACE('P0_F1976',(#1329),#1311,.T.);
#1331=CARTESIAN_POINT('',(20.9,-4.96361850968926,29.8307));
#1332=CARTESIAN_POINT('',(21.,-4.96361850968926,29.8307));
#1333=CARTESIAN_POINT('',(20.9,-4.96361850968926,29.2067));
#1334=CARTESIAN_POINT('',(21.,-4.96361850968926,29.2067));
#1335=CARTESIAN_POINT('',(20.9,-4.45321850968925,28.6962));
#1336=CARTESIAN_POINT('',(21.,-4.45321850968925,28.6962));
#1337=CARTESIAN_POINT('',(20.9,-3.82921850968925,28.6962));
#1338=CARTESIAN_POINT('',(21.,-3.82921850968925,28.6962));
#1339=(BOUNDED_SURFACE() B_SPLINE_SURFACE(3,1,((#1331,#1332),(#1333,#1334),(#1335,#1336),(#1337,
#1338)),.UNSPECIFIED.,.F.,.F.,.F.) B_SPLINE_SURFACE_WITH_KNOTS((4,4),(2,2),(0.75,0.8125),(0.,
1.),.UNSPECIFIED.) GEOMETRIC_REPRESENTATION_ITEM() RATIONAL_B_SPLINE_SURFACE(((1.,1.),(1.,1.),
(1.,1.),(1.,1.))) REPRESENTATION_ITEM('') SURFACE());
#1340=CARTESIAN_POINT('',(20.9,-4.96361850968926,29.8307));
#1341=CARTESIAN_POINT('',(20.9,-4.96361850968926,29.2067));
#1342=CARTESIAN_POINT('',(20.9,-4.45321850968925,28.6962));
#1343=CARTESIAN_POINT('',(20.9,-3.82921850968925,28.6962));
#1344=(BOUNDED_CURVE() B_SPLINE_CURVE(3,(#1340,#1341,#1342,#1343),.UNSPECIFIED.,.F.,
.F.) B_SPLINE_CURVE_WITH_KNOTS((4,4),(0.75,0.8125),
.UNSPECIFIED.) CURVE() GEOMETRIC_REPRESENTATION_ITEM() RATIONAL_B_SPLINE_CURVE((1.,1.,1.,1.)) REPRESENTATION_ITEM(''));
#1345=CARTESIAN_POINT('',(20.9,-3.82921850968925,28.6962));
#1346=VERTEX_POINT('',#1345);
#1347=EDGE_CURVE('P0_E1303',#1319,#1346,#1344,.T.);
#1348=DIRECTION('',(1.,0.,0.));
#1349=VECTOR('',#1348,1.);
#1350=CARTESIAN_POINT('',(20.9,-3.82921850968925,28.6962));
#1351=LINE('',#1350,#1349);
#1352=EDGE_CURVE('P0_E1399',#1346,#154,#1351,.T.);
#1353=ORIENTED_EDGE('',*,*,#155,.F.);
#1354=ORIENTED_EDGE('',*,*,#1326,.F.);
#1355=ORIENTED_EDGE('',*,*,#1347,.T.);
#1356=ORIENTED_EDGE('',*,*,#1352,.T.);
#1357=EDGE_LOOP('',(#1353,#1354,#1355,#1356));
#1358=FACE_BOUND('',#1357,.T.);
#1359=ADVANCED_FACE('P0_F1971',(#1358),#1339,.T.);
#1360=CARTESIAN_POINT('',(20.9,-3.82921850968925,28.6962));
#1361=CARTESIAN_POINT('',(21.,-3.82921850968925,28.6962));
#1362=CARTESIAN_POINT('',(20.9,-3.20521850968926,28.6962));
#1363=CARTESIAN_POINT('',(21.,-3.20521850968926,28.6962));
#1364=CARTESIAN_POINT('',(20.9,-2.69471850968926,29.2067));
#1365=CARTESIAN_POINT('',(21.,-2.69471850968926,29.2067));
#1366=CARTESIAN_POINT('',(20.9,-2.69471850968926,29.8307));
#1367=CARTESIAN_POINT('',(21.,-2.69471850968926,29.8307));
#1368=(BOUNDED_SURFACE() B_SPLINE_SURFACE(3,1,((#1360,#1361),(#1362,#1363),(#1364,#1365),(#1366,
#1367)),.UNSPECIFIED.,.F.,.F.,.F.) B_SPLINE_SURFACE_WITH_KNOTS((4,4),(2,2),(0.875,0.9375),(0.,
1.),.UNSPECIFIED.) GEOMETRIC_REPRESENTATION_ITEM() RATIONAL_B_SPLINE_SURFACE(((1.,1.),(1.,1.),
(1.,1.),(1.,1.))) REPRESENTATION_ITEM('') SURFACE());
#1369=CARTESIAN_POINT('',(20.9,-3.82921850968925,28.6962));
#1370=CARTESIAN_POINT('',(20.9,-3.20521850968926,28.6962));
#1371=CARTESIAN_POINT('',(20.9,-2.69471850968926,29.2067));
#1372=CARTESIAN_POINT('',(20.9,-2.69471850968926,29.8307));
#1373=(BOUNDED_CURVE() B_SPLINE_CURVE(3,(#1369,#1370,#1371,#1372),.UNSPECIFIED.,.F.,
.F.) B_SPLINE_CURVE_WITH_KNOTS((4,4),(0.875,0.9375),
.UNSPECIFIED.) CURVE() GEOMETRIC_REPRESENTATION_ITEM() RATIONAL_B_SPLINE_CURVE((1.,1.,1.,1.)) REPRESENTATION_ITEM(''));
#1374=CARTESIAN_POINT('',(20.9,-2.69471850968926,29.8307));
#1375=VERTEX_POINT('',#1374);
#1376=EDGE_CURVE('P0_E1082',#1346,#1375,#1373,.T.);
#1377=DIRECTION('',(1.,0.,0.));
#1378=VECTOR('',#1377,1.);
#1379=CARTESIAN_POINT('',(20.9,-2.69471850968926,29.8307));
#1380=LINE('',#1379,#1378);
#1381=EDGE_CURVE('P0_E1395',#1375,#163,#1380,.T.);
#1382=ORIENTED_EDGE('',*,*,#164,.F.);
#1383=ORIENTED_EDGE('',*,*,#1352,.F.);
#1384=ORIENTED_EDGE('',*,*,#1376,.T.);
#1385=ORIENTED_EDGE('',*,*,#1381,.T.);
#1386=EDGE_LOOP('',(#1382,#1383,#1384,#1385));
#1387=FACE_BOUND('',#1386,.T.);
#1388=ADVANCED_FACE('P0_F1967',(#1387),#1368,.T.);
#1389=CARTESIAN_POINT('',(20.9,-2.69471850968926,29.8307));
#1390=DIRECTION('',(0.,1.,0.));
#1391=DIRECTION('',(1.,0.,0.));
#1392=AXIS2_PLACEMENT_3D('',#1389,#1390,#1391);
#1393=PLANE('',#1392);
#1394=ORIENTED_EDGE('',*,*,#172,.F.);
#1395=ORIENTED_EDGE('',*,*,#1381,.F.);
#1396=DIRECTION('',(0.,0.,1.));
#1397=VECTOR('',#1396,1.);
#1398=CARTESIAN_POINT('',(20.9,-2.69471850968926,29.8307));
#1399=LINE('',#1398,#1397);
#1400=CARTESIAN_POINT('',(20.9,-2.69471850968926,31.0456));
#1401=VERTEX_POINT('',#1400);
#1402=EDGE_CURVE('P0_E1083',#1375,#1401,#1399,.T.);
#1403=ORIENTED_EDGE('',*,*,#1402,.T.);
#1404=DIRECTION('',(1.,0.,0.));
#1405=VECTOR('',#1404,1.);
#1406=CARTESIAN_POINT('',(20.9,-2.69471850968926,31.0456));
#1407=LINE('',#1406,#1405);
#1408=EDGE_CURVE('P0_E1383',#1401,#171,#1407,.T.);
#1409=ORIENTED_EDGE('',*,*,#1408,.T.);
#1410=EDGE_LOOP('',(#1394,#1395,#1403,#1409));
#1411=FACE_BOUND('',#1410,.T.);
#1412=ADVANCED_FACE('P0_F1959',(#1411),#1393,.T.);
#1413=CARTESIAN_POINT('',(20.9,-2.69471850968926,31.0456));
#1414=DIRECTION('',(0.,0.,1.));
#1415=DIRECTION('',(1.,0.,0.));
#1416=AXIS2_PLACEMENT_3D('',#1413,#1414,#1415);
#1417=PLANE('',#1416);
#1418=ORIENTED_EDGE('',*,*,#180,.F.);
#1419=ORIENTED_EDGE('',*,*,#1408,.F.);
#1420=DIRECTION('',(0.,-1.,0.));
#1421=VECTOR('',#1420,1.);
#1422=CARTESIAN_POINT('',(20.9,-2.69471850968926,31.0456));
#1423=LINE('',#1422,#1421);
#1424=CARTESIAN_POINT('',(20.9,-4.96361850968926,31.0456));
#1425=VERTEX_POINT('',#1424);
#1426=EDGE_CURVE('P0_E1086',#1401,#1425,#1423,.T.);
#1427=ORIENTED_EDGE('',*,*,#1426,.T.);
#1428=DIRECTION('',(1.,0.,0.));
#1429=VECTOR('',#1428,1.);
#1430=CARTESIAN_POINT('',(20.9,-4.96361850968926,31.0456));
#1431=LINE('',#1430,#1429);
#1432=EDGE_CURVE('P0_E1380',#1425,#179,#1431,.T.);
#1433=ORIENTED_EDGE('',*,*,#1432,.T.);
#1434=EDGE_LOOP('',(#1418,#1419,#1427,#1433));
#1435=FACE_BOUND('',#1434,.T.);
#1436=ADVANCED_FACE('P0_F1958',(#1435),#1417,.T.);
#1437=CARTESIAN_POINT('',(20.9,-4.96361850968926,31.0456));
#1438=DIRECTION('',(0.,-1.,0.));
#1439=DIRECTION('',(0.,0.,-1.));
#1440=AXIS2_PLACEMENT_3D('',#1437,#1438,#1439);
#1441=PLANE('',#1440);
#1442=ORIENTED_EDGE('',*,*,#188,.F.);
#1443=ORIENTED_EDGE('',*,*,#1432,.F.);
#1444=DIRECTION('',(0.,0.,-1.));
#1445=VECTOR('',#1444,1.);
#1446=CARTESIAN_POINT('',(20.9,-4.96361850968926,31.0456));
#1447=LINE('',#1446,#1445);
#1448=CARTESIAN_POINT('',(20.9,-4.96361850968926,30.5036));
#1449=VERTEX_POINT('',#1448);
#1450=EDGE_CURVE('P0_E726',#1425,#1449,#1447,.T.);
#1451=ORIENTED_EDGE('',*,*,#1450,.T.);
#1452=DIRECTION('',(1.,0.,0.));
#1453=VECTOR('',#1452,1.);
#1454=CARTESIAN_POINT('',(20.9,-4.96361850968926,30.5036));
#1455=LINE('',#1454,#1453);
#1456=EDGE_CURVE('P0_E1369',#1449,#187,#1455,.T.);
#1457=ORIENTED_EDGE('',*,*,#1456,.T.);
#1458=EDGE_LOOP('',(#1442,#1443,#1451,#1457));
#1459=FACE_BOUND('',#1458,.T.);
#1460=ADVANCED_FACE('P0_F1955',(#1459),#1441,.T.);
#1461=CARTESIAN_POINT('',(20.9,-4.05351850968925,30.5036));
#1462=DIRECTION('',(0.,0.,-1.));
#1463=DIRECTION('',(0.,-1.,0.));
#1464=AXIS2_PLACEMENT_3D('',#1461,#1462,#1463);
#1465=PLANE('',#1464);
#1466=ORIENTED_EDGE('',*,*,#196,.F.);
#1467=ORIENTED_EDGE('',*,*,#1456,.F.);
#1468=DIRECTION('',(0.,1.,0.));
#1469=VECTOR('',#1468,1.);
#1470=CARTESIAN_POINT('',(20.9,-4.96361850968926,30.5036));
#1471=LINE('',#1470,#1469);
#1472=CARTESIAN_POINT('',(20.9,-3.21791850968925,30.5036));
#1473=VERTEX_POINT('',#1472);
#1474=EDGE_CURVE('P0_E995',#1449,#1473,#1471,.T.);
#1475=ORIENTED_EDGE('',*,*,#1474,.T.);
#1476=DIRECTION('',(1.,0.,0.));
#1477=VECTOR('',#1476,1.);
#1478=CARTESIAN_POINT('',(20.9,-3.21791850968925,30.5036));
#1479=LINE('',#1478,#1477);
#1480=EDGE_CURVE('P0_E958',#1473,#195,#1479,.T.);
#1481=ORIENTED_EDGE('',*,*,#1480,.T.);
#1482=EDGE_LOOP('',(#1466,#1467,#1475,#1481));
#1483=FACE_BOUND('',#1482,.T.);
#1484=ADVANCED_FACE('P0_F1943',(#1483),#1465,.T.);
#1485=CARTESIAN_POINT('',(20.9,-3.21791850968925,30.5036));
#1486=DIRECTION('',(0.,-1.,0.));
#1487=DIRECTION('',(0.,0.,-1.));
#1488=AXIS2_PLACEMENT_3D('',#1485,#1486,#1487);
#1489=PLANE('',#1488);
#1490=ORIENTED_EDGE('',*,*,#202,.F.);
#1491=ORIENTED_EDGE('',*,*,#1480,.F.);
#1492=DIRECTION('',(0.,0.,-1.));
#1493=VECTOR('',#1492,1.);
#1494=CARTESIAN_POINT('',(20.9,-3.21791850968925,30.5036));
#1495=LINE('',#1494,#1493);
#1496=CARTESIAN_POINT('',(20.9,-3.21791850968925,29.8494));
#1497=VERTEX_POINT('',#1496);
#1498=EDGE_CURVE('P0_E987',#1473,#1497,#1495,.T.);
#1499=ORIENTED_EDGE('',*,*,#1498,.T.);
#1500=DIRECTION('',(1.,0.,0.));
#1501=VECTOR('',#1500,1.);
#1502=CARTESIAN_POINT('',(20.9,-3.21791850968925,29.8494));
#1503=LINE('',#1502,#1501);
#1504=EDGE_CURVE('P0_E1355',#1497,#110,#1503,.T.);
#1505=ORIENTED_EDGE('',*,*,#1504,.T.);
#1506=EDGE_LOOP('',(#1490,#1491,#1499,#1505));
#1507=FACE_BOUND('',#1506,.T.);
#1508=ADVANCED_FACE('P0_F1933',(#1507),#1489,.T.);
#1509=CARTESIAN_POINT('',(20.9,-3.21791850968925,29.8494));
#1510=CARTESIAN_POINT('',(21.,-3.21791850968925,29.8494));
#1511=CARTESIAN_POINT('',(20.9,-3.21791850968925,29.5131));
#1512=CARTESIAN_POINT('',(21.,-3.21791850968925,29.5131));
#1513=CARTESIAN_POINT('',(20.9,-3.49311850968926,29.2382));
#1514=CARTESIAN_POINT('',(21.,-3.49311850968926,29.2382));
#1515=CARTESIAN_POINT('',(20.9,-3.82921850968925,29.2382));
#1516=CARTESIAN_POINT('',(21.,-3.82921850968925,29.2382));
#1517=(BOUNDED_SURFACE() B_SPLINE_SURFACE(3,1,((#1509,#1510),(#1511,#1512),(#1513,#1514),(#1515,
#1516)),.UNSPECIFIED.,.F.,.F.,.F.) B_SPLINE_SURFACE_WITH_KNOTS((4,4),(2,2),(0.4375,0.5),(0.,1.),
.UNSPECIFIED.) GEOMETRIC_REPRESENTATION_ITEM() RATIONAL_B_SPLINE_SURFACE(((1.,1.),(1.,1.),(1.,
1.),(1.,1.))) REPRESENTATION_ITEM('') SURFACE());
#1518=CARTESIAN_POINT('',(20.9,-3.21791850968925,29.8494));
#1519=CARTESIAN_POINT('',(20.9,-3.21791850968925,29.5131));
#1520=CARTESIAN_POINT('',(20.9,-3.49311850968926,29.2382));
#1521=CARTESIAN_POINT('',(20.9,-3.82921850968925,29.2382));
#1522=(BOUNDED_CURVE() B_SPLINE_CURVE(3,(#1518,#1519,#1520,#1521),.UNSPECIFIED.,.F.,
.F.) B_SPLINE_CURVE_WITH_KNOTS((4,4),(0.4375,0.5),
.UNSPECIFIED.) CURVE() GEOMETRIC_REPRESENTATION_ITEM() RATIONAL_B_SPLINE_CURVE((1.,1.,1.,1.)) REPRESENTATION_ITEM(''));
#1523=EDGE_CURVE('P0_E1331',#1497,#1237,#1522,.T.);
#1524=ORIENTED_EDGE('',*,*,#113,.F.);
#1525=ORIENTED_EDGE('',*,*,#1504,.F.);
#1526=ORIENTED_EDGE('',*,*,#1523,.T.);
#1527=ORIENTED_EDGE('',*,*,#1238,.T.);
#1528=EDGE_LOOP('',(#1524,#1525,#1526,#1527));
#1529=FACE_BOUND('',#1528,.T.);
#1530=ADVANCED_FACE('P0_F1920',(#1529),#1517,.T.);
#1531=CARTESIAN_POINT('',(20.9,5.73659399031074,24.2697125));
#1532=DIRECTION('',(1.,0.,0.));
#1533=DIRECTION('',(0.,1.,0.));
#1534=AXIS2_PLACEMENT_3D('',#1531,#1532,#1533);
#1535=PLANE('',#1534);
#1536=ORIENTED_EDGE('',*,*,#1498,.F.);
#1537=ORIENTED_EDGE('',*,*,#1474,.F.);
#1538=ORIENTED_EDGE('',*,*,#1450,.F.);
#1539=ORIENTED_EDGE('',*,*,#1426,.F.);
#1540=ORIENTED_EDGE('',*,*,#1402,.F.);
#1541=ORIENTED_EDGE('',*,*,#1376,.F.);
#1542=ORIENTED_EDGE('',*,*,#1347,.F.);
#1543=ORIENTED_EDGE('',*,*,#1320,.F.);
#1544=ORIENTED_EDGE('',*,*,#1296,.F.);
#1545=ORIENTED_EDGE('',*,*,#1272,.F.);
#1546=ORIENTED_EDGE('',*,*,#1246,.F.);
#1547=ORIENTED_EDGE('',*,*,#1523,.F.);
#1548=EDGE_LOOP('',(#1536,#1537,#1538,#1539,#1540,#1541,#1542,#1543,#1544,#1545,#1546,#1547));
#1549=FACE_BOUND('',#1548,.T.);
#1550=ORIENTED_EDGE('',*,*,#1190,.F.);
#1551=ORIENTED_EDGE('',*,*,#1166,.F.);
#1552=ORIENTED_EDGE('',*,*,#1140,.F.);
#1553=ORIENTED_EDGE('',*,*,#1113,.F.);
#1554=ORIENTED_EDGE('',*,*,#1087,.F.);
#1555=ORIENTED_EDGE('',*,*,#1060,.F.);
#1556=ORIENTED_EDGE('',*,*,#1034,.F.);
#1557=ORIENTED_EDGE('',*,*,#1007,.F.);
#1558=ORIENTED_EDGE('',*,*,#981,.F.);
#1559=ORIENTED_EDGE('',*,*,#954,.F.);
#1560=ORIENTED_EDGE('',*,*,#930,.F.);
#1561=ORIENTED_EDGE('',*,*,#904,.F.);
#1562=ORIENTED_EDGE('',*,*,#875,.F.);
#1563=ORIENTED_EDGE('',*,*,#846,.F.);
#1564=ORIENTED_EDGE('',*,*,#1215,.F.);
#1565=EDGE_LOOP('',(#1550,#1551,#1552,#1553,#1554,#1555,#1556,#1557,#1558,#1559,#1560,#1561,
#1562,#1563,#1564));
#1566=FACE_BOUND('',#1565,.T.);
#1567=ORIENTED_EDGE('',*,*,#795,.F.);
#1568=ORIENTED_EDGE('',*,*,#771,.F.);
#1569=ORIENTED_EDGE('',*,*,#747,.F.);
#1570=ORIENTED_EDGE('',*,*,#723,.F.);
#1571=ORIENTED_EDGE('',*,*,#699,.F.);
#1572=ORIENTED_EDGE('',*,*,#675,.F.);
#1573=ORIENTED_EDGE('',*,*,#651,.F.);
#1574=ORIENTED_EDGE('',*,*,#817,.F.);
#1575=EDGE_LOOP('',(#1567,#1568,#1569,#1570,#1571,#1572,#1573,#1574));
#1576=FACE_BOUND('',#1575,.T.);
#1577=ORIENTED_EDGE('',*,*,#603,.F.);
#1578=ORIENTED_EDGE('',*,*,#579,.F.);
#1579=ORIENTED_EDGE('',*,*,#555,.F.);
#1580=ORIENTED_EDGE('',*,*,#531,.F.);
#1581=ORIENTED_EDGE('',*,*,#507,.F.);
#1582=ORIENTED_EDGE('',*,*,#483,.F.);
#1583=ORIENTED_EDGE('',*,*,#459,.F.);
#1584=ORIENTED_EDGE('',*,*,#435,.F.);
#1585=ORIENTED_EDGE('',*,*,#625,.F.);
#1586=EDGE_LOOP('',(#1577,#1578,#1579,#1580,#1581,#1582,#1583,#1584,#1585));
#1587=FACE_BOUND('',#1586,.T.);
#1588=CARTESIAN_POINT('',(20.9,5.05098149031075,23.9846));
#1589=CARTESIAN_POINT('',(20.9,5.58488149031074,23.9846));
#1590=CARTESIAN_POINT('',(20.9,6.02178149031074,24.4214));
#1591=CARTESIAN_POINT('',(20.9,6.02178149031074,24.9551));
#1592=(BOUNDED_CURVE() B_SPLINE_CURVE(3,(#1588,#1589,#1590,#1591),.UNSPECIFIED.,.F.,
.F.) B_SPLINE_CURVE_WITH_KNOTS((4,4),(0.125,0.25),
.UNSPECIFIED.) CURVE() GEOMETRIC_REPRESENTATION_ITEM() RATIONAL_B_SPLINE_CURVE((1.,1.,1.,1.)) REPRESENTATION_ITEM(''));
#1593=CARTESIAN_POINT('',(20.9,5.05098149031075,23.9846));
#1594=VERTEX_POINT('',#1593);
#1595=CARTESIAN_POINT('',(20.9,6.02178149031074,24.9551));
#1596=VERTEX_POINT('',#1595);
#1597=EDGE_CURVE('P0_E1150',#1594,#1596,#1592,.T.);
#1598=ORIENTED_EDGE('',*,*,#1597,.T.);
#1599=DIRECTION('',(0.,0.,1.));
#1600=VECTOR('',#1599,1.);
#1601=CARTESIAN_POINT('',(20.9,6.02178149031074,35.0195));
#1602=LINE('',#1601,#1600);
#1603=CARTESIAN_POINT('',(20.9,6.02178149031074,35.0195));
#1604=VERTEX_POINT('',#1603);
#1605=EDGE_CURVE('P0_E1046',#1596,#1604,#1602,.T.);
#1606=ORIENTED_EDGE('',*,*,#1605,.T.);
#1607=CARTESIAN_POINT('',(20.9,6.02178149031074,35.0195));
#1608=CARTESIAN_POINT('',(20.9,6.02178149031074,35.5532));
#1609=CARTESIAN_POINT('',(20.9,5.58488149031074,35.9903));
#1610=CARTESIAN_POINT('',(20.9,5.05098149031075,35.9903));
#1611=(BOUNDED_CURVE() B_SPLINE_CURVE(3,(#1607,#1608,#1609,#1610),.UNSPECIFIED.,.F.,
.F.) B_SPLINE_CURVE_WITH_KNOTS((4,4),(0.875,1.),
.UNSPECIFIED.) CURVE() GEOMETRIC_REPRESENTATION_ITEM() RATIONAL_B_SPLINE_CURVE((1.,1.,1.,1.)) REPRESENTATION_ITEM(''));
#1612=CARTESIAN_POINT('',(20.9,5.05098149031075,35.9903));
#1613=VERTEX_POINT('',#1612);
#1614=EDGE_CURVE('P0_E1154',#1604,#1613,#1611,.T.);
#1615=ORIENTED_EDGE('',*,*,#1614,.T.);
#1616=DIRECTION('',(0.,-1.,0.));
#1617=VECTOR('',#1616,1.);
#1618=CARTESIAN_POINT('',(20.9,-5.01321850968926,35.9903));
#1619=LINE('',#1618,#1617);
#1620=CARTESIAN_POINT('',(20.9,-5.01321850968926,35.9903));
#1621=VERTEX_POINT('',#1620);
#1622=EDGE_CURVE('P0_E1018',#1613,#1621,#1619,.T.);
#1623=ORIENTED_EDGE('',*,*,#1622,.T.);
#1624=CARTESIAN_POINT('',(20.9,-5.01321850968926,35.9903));
#1625=CARTESIAN_POINT('',(20.9,-5.54711850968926,35.9903));
#1626=CARTESIAN_POINT('',(20.9,-5.98391850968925,35.5532));
#1627=CARTESIAN_POINT('',(20.9,-5.98391850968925,35.0195));
#1628=(BOUNDED_CURVE() B_SPLINE_CURVE(3,(#1624,#1625,#1626,#1627),.UNSPECIFIED.,.F.,
.F.) B_SPLINE_CURVE_WITH_KNOTS((4,4),(0.625,0.75),
.UNSPECIFIED.) CURVE() GEOMETRIC_REPRESENTATION_ITEM() RATIONAL_B_SPLINE_CURVE((1.,1.,1.,1.)) REPRESENTATION_ITEM(''));
#1629=CARTESIAN_POINT('',(20.9,-5.98391850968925,35.0195));
#1630=VERTEX_POINT('',#1629);
#1631=EDGE_CURVE('P0_E1023',#1621,#1630,#1628,.T.);
#1632=ORIENTED_EDGE('',*,*,#1631,.T.);
#1633=DIRECTION('',(0.,0.,-1.));
#1634=VECTOR('',#1633,1.);
#1635=CARTESIAN_POINT('',(20.9,-5.98391850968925,24.9551));
#1636=LINE('',#1635,#1634);
#1637=CARTESIAN_POINT('',(20.9,-5.98391850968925,24.9551));
#1638=VERTEX_POINT('',#1637);
#1639=EDGE_CURVE('P0_E1074',#1630,#1638,#1636,.T.);
#1640=ORIENTED_EDGE('',*,*,#1639,.T.);
#1641=CARTESIAN_POINT('',(20.9,-5.98391850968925,24.9551));
#1642=CARTESIAN_POINT('',(20.9,-5.98391850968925,24.4214));
#1643=CARTESIAN_POINT('',(20.9,-5.54711850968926,23.9846));
#1644=CARTESIAN_POINT('',(20.9,-5.01321850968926,23.9846));
#1645=(BOUNDED_CURVE() B_SPLINE_CURVE(3,(#1641,#1642,#1643,#1644),.UNSPECIFIED.,.F.,
.F.) B_SPLINE_CURVE_WITH_KNOTS((4,4),(0.375,0.5),
.UNSPECIFIED.) CURVE() GEOMETRIC_REPRESENTATION_ITEM() RATIONAL_B_SPLINE_CURVE((1.,1.,1.,1.)) REPRESENTATION_ITEM(''));
#1646=CARTESIAN_POINT('',(20.9,-5.01321850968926,23.9846));
#1647=VERTEX_POINT('',#1646);
#1648=EDGE_CURVE('P0_E990',#1638,#1647,#1645,.T.);
#1649=ORIENTED_EDGE('',*,*,#1648,.T.);
#1650=DIRECTION('',(0.,1.,0.));
#1651=VECTOR('',#1650,1.);
#1652=CARTESIAN_POINT('',(20.9,5.05098149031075,23.9846));
#1653=LINE('',#1652,#1651);
#1654=EDGE_CURVE('P0_E775',#1647,#1594,#1653,.T.);
#1655=ORIENTED_EDGE('',*,*,#1654,.T.);
#1656=EDGE_LOOP('',(#1598,#1606,#1615,#1623,#1632,#1640,#1649,#1655));
#1657=FACE_BOUND('',#1656,.T.);
#1658=ADVANCED_FACE('P0_F1913',(#1549,#1566,#1576,#1587,#1657),#1535,.T.);
#1659=CARTESIAN_POINT('',(20.9,6.02178149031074,35.0195));
#1660=DIRECTION('',(0.,1.,0.));
#1661=DIRECTION('',(1.,0.,0.));
#1662=AXIS2_PLACEMENT_3D('',#1659,#1660,#1661);
#1663=PLANE('',#1662);
#1664=DIRECTION('',(0.,0.,1.));
#1665=VECTOR('',#1664,1.);
#1666=CARTESIAN_POINT('',(21.,6.02178149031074,35.0195));
#1667=LINE('',#1666,#1665);
#1668=CARTESIAN_POINT('',(21.,6.02178149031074,24.9551));
#1669=VERTEX_POINT('',#1668);
#1670=CARTESIAN_POINT('',(21.,6.02178149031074,35.0195));
#1671=VERTEX_POINT('',#1670);
#1672=EDGE_CURVE('P0_E1087',#1669,#1671,#1667,.T.);
#1673=ORIENTED_EDGE('',*,*,#1672,.T.);
#1674=DIRECTION('',(1.,0.,0.));
#1675=VECTOR('',#1674,1.);
#1676=CARTESIAN_POINT('',(20.9,6.02178149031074,35.0195));
#1677=LINE('',#1676,#1675);
#1678=EDGE_CURVE('P0_E1054',#1604,#1671,#1677,.T.);
#1679=ORIENTED_EDGE('',*,*,#1678,.F.);
#1680=ORIENTED_EDGE('',*,*,#1605,.F.);
#1681=DIRECTION('',(1.,0.,0.));
#1682=VECTOR('',#1681,1.);
#1683=CARTESIAN_POINT('',(20.9,6.02178149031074,24.9551));
#1684=LINE('',#1683,#1682);
#1685=EDGE_CURVE('P0_E1134',#1596,#1669,#1684,.T.);
#1686=ORIENTED_EDGE('',*,*,#1685,.T.);
#1687=EDGE_LOOP('',(#1673,#1679,#1680,#1686));
#1688=FACE_BOUND('',#1687,.T.);
#1689=ADVANCED_FACE('P0_F1905',(#1688),#1663,.F.);
#1690=CARTESIAN_POINT('',(20.9,6.02178149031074,35.0195));
#1691=CARTESIAN_POINT('',(21.,6.02178149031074,35.0195));
#1692=CARTESIAN_POINT('',(20.9,6.02178149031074,35.5532));
#1693=CARTESIAN_POINT('',(21.,6.02178149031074,35.5532));
#1694=CARTESIAN_POINT('',(20.9,5.58488149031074,35.9903));
#1695=CARTESIAN_POINT('',(21.,5.58488149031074,35.9903));
#1696=CARTESIAN_POINT('',(20.9,5.05098149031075,35.9903));
#1697=CARTESIAN_POINT('',(21.,5.05098149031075,35.9903));
#1698=(BOUNDED_SURFACE() B_SPLINE_SURFACE(3,1,((#1690,#1691),(#1692,#1693),(#1694,#1695),(#1696,
#1697)),.UNSPECIFIED.,.F.,.F.,.F.) B_SPLINE_SURFACE_WITH_KNOTS((4,4),(2,2),(0.875,1.),(0.,1.),
.UNSPECIFIED.) GEOMETRIC_REPRESENTATION_ITEM() RATIONAL_B_SPLINE_SURFACE(((1.,1.),(1.,1.),(1.,
1.),(1.,1.))) REPRESENTATION_ITEM('') SURFACE());
#1699=CARTESIAN_POINT('',(21.,6.02178149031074,35.0195));
#1700=CARTESIAN_POINT('',(21.,6.02178149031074,35.5532));
#1701=CARTESIAN_POINT('',(21.,5.58488149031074,35.9903));
#1702=CARTESIAN_POINT('',(21.,5.05098149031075,35.9903));
#1703=(BOUNDED_CURVE() B_SPLINE_CURVE(3,(#1699,#1700,#1701,#1702),.UNSPECIFIED.,.F.,
.F.) B_SPLINE_CURVE_WITH_KNOTS((4,4),(0.875,1.),
.UNSPECIFIED.) CURVE() GEOMETRIC_REPRESENTATION_ITEM() RATIONAL_B_SPLINE_CURVE((1.,1.,1.,1.)) REPRESENTATION_ITEM(''));
#1704=CARTESIAN_POINT('',(21.,5.05098149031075,35.9903));
#1705=VERTEX_POINT('',#1704);
#1706=EDGE_CURVE('P0_E945',#1671,#1705,#1703,.T.);
#1707=DIRECTION('',(1.,0.,0.));
#1708=VECTOR('',#1707,1.);
#1709=CARTESIAN_POINT('',(20.9,5.05098149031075,35.9903));
#1710=LINE('',#1709,#1708);
#1711=EDGE_CURVE('P0_E1069',#1613,#1705,#1710,.T.);
#1712=ORIENTED_EDGE('',*,*,#1706,.T.);
#1713=ORIENTED_EDGE('',*,*,#1711,.F.);
#1714=ORIENTED_EDGE('',*,*,#1614,.F.);
#1715=ORIENTED_EDGE('',*,*,#1678,.T.);
#1716=EDGE_LOOP('',(#1712,#1713,#1714,#1715));
#1717=FACE_BOUND('',#1716,.T.);
#1718=ADVANCED_FACE('P0_F1753',(#1717),#1698,.F.);
#1719=CARTESIAN_POINT('',(20.9,-5.01321850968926,35.9903));
#1720=DIRECTION('',(0.,0.,1.));
#1721=DIRECTION('',(1.,0.,0.));
#1722=AXIS2_PLACEMENT_3D('',#1719,#1720,#1721);
#1723=PLANE('',#1722);
#1724=DIRECTION('',(0.,-1.,0.));
#1725=VECTOR('',#1724,1.);
#1726=CARTESIAN_POINT('',(21.,-5.01321850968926,35.9903));
#1727=LINE('',#1726,#1725);
#1728=CARTESIAN_POINT('',(21.,-5.01321850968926,35.9903));
#1729=VERTEX_POINT('',#1728);
#1730=EDGE_CURVE('P0_E859',#1705,#1729,#1727,.T.);
#1731=ORIENTED_EDGE('',*,*,#1730,.T.);
#1732=DIRECTION('',(1.,0.,0.));
#1733=VECTOR('',#1732,1.);
#1734=CARTESIAN_POINT('',(20.9,-5.01321850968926,35.9903));
#1735=LINE('',#1734,#1733);
#1736=EDGE_CURVE('P0_E1020',#1621,#1729,#1735,.T.);
#1737=ORIENTED_EDGE('',*,*,#1736,.F.);
#1738=ORIENTED_EDGE('',*,*,#1622,.F.);
#1739=ORIENTED_EDGE('',*,*,#1711,.T.);
#1740=EDGE_LOOP('',(#1731,#1737,#1738,#1739));
#1741=FACE_BOUND('',#1740,.T.);
#1742=ADVANCED_FACE('P0_F1747',(#1741),#1723,.F.);
#1743=CARTESIAN_POINT('',(20.9,-5.01321850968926,35.9903));
#1744=CARTESIAN_POINT('',(21.,-5.01321850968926,35.9903));
#1745=CARTESIAN_POINT('',(20.9,-5.54711850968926,35.9903));
#1746=CARTESIAN_POINT('',(21.,-5.54711850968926,35.9903));
#1747=CARTESIAN_POINT('',(20.9,-5.98391850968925,35.5532));
#1748=CARTESIAN_POINT('',(21.,-5.98391850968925,35.5532));
#1749=CARTESIAN_POINT('',(20.9,-5.98391850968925,35.0195));
#1750=CARTESIAN_POINT('',(21.,-5.98391850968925,35.0195));
#1751=(BOUNDED_SURFACE() B_SPLINE_SURFACE(3,1,((#1743,#1744),(#1745,#1746),(#1747,#1748),(#1749,
#1750)),.UNSPECIFIED.,.F.,.F.,.F.) B_SPLINE_SURFACE_WITH_KNOTS((4,4),(2,2),(0.625,0.75),(0.,1.),
.UNSPECIFIED.) GEOMETRIC_REPRESENTATION_ITEM() RATIONAL_B_SPLINE_SURFACE(((1.,1.),(1.,1.),(1.,
1.),(1.,1.))) REPRESENTATION_ITEM('') SURFACE());
#1752=CARTESIAN_POINT('',(21.,-5.01321850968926,35.9903));
#1753=CARTESIAN_POINT('',(21.,-5.54711850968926,35.9903));
#1754=CARTESIAN_POINT('',(21.,-5.98391850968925,35.5532));
#1755=CARTESIAN_POINT('',(21.,-5.98391850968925,35.0195));
#1756=(BOUNDED_CURVE() B_SPLINE_CURVE(3,(#1752,#1753,#1754,#1755),.UNSPECIFIED.,.F.,
.F.) B_SPLINE_CURVE_WITH_KNOTS((4,4),(0.625,0.75),
.UNSPECIFIED.) CURVE() GEOMETRIC_REPRESENTATION_ITEM() RATIONAL_B_SPLINE_CURVE((1.,1.,1.,1.)) REPRESENTATION_ITEM(''));
#1757=CARTESIAN_POINT('',(21.,-5.98391850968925,35.0195));
#1758=VERTEX_POINT('',#1757);
#1759=EDGE_CURVE('P0_E851',#1729,#1758,#1756,.T.);
#1760=DIRECTION('',(1.,0.,0.));
#1761=VECTOR('',#1760,1.);
#1762=CARTESIAN_POINT('',(20.9,-5.98391850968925,35.0195));
#1763=LINE('',#1762,#1761);
#1764=EDGE_CURVE('P0_E1078',#1630,#1758,#1763,.T.);
#1765=ORIENTED_EDGE('',*,*,#1759,.T.);
#1766=ORIENTED_EDGE('',*,*,#1764,.F.);
#1767=ORIENTED_EDGE('',*,*,#1631,.F.);
#1768=ORIENTED_EDGE('',*,*,#1736,.T.);
#1769=EDGE_LOOP('',(#1765,#1766,#1767,#1768));
#1770=FACE_BOUND('',#1769,.T.);
#1771=ADVANCED_FACE('P0_F1755',(#1770),#1751,.F.);
#1772=CARTESIAN_POINT('',(20.9,-5.98391850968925,24.9551));
#1773=DIRECTION('',(0.,-1.,0.));
#1774=DIRECTION('',(0.,0.,-1.));
#1775=AXIS2_PLACEMENT_3D('',#1772,#1773,#1774);
#1776=PLANE('',#1775);
#1777=DIRECTION('',(0.,0.,-1.));
#1778=VECTOR('',#1777,1.);
#1779=CARTESIAN_POINT('',(21.,-5.98391850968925,24.9551));
#1780=LINE('',#1779,#1778);
#1781=CARTESIAN_POINT('',(21.,-5.98391850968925,24.9551));
#1782=VERTEX_POINT('',#1781);
#1783=EDGE_CURVE('P0_E863',#1758,#1782,#1780,.T.);
#1784=ORIENTED_EDGE('',*,*,#1783,.T.);
#1785=DIRECTION('',(1.,0.,0.));
#1786=VECTOR('',#1785,1.);
#1787=CARTESIAN_POINT('',(20.9,-5.98391850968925,24.9551));
#1788=LINE('',#1787,#1786);
#1789=EDGE_CURVE('P0_E1077',#1638,#1782,#1788,.T.);
#1790=ORIENTED_EDGE('',*,*,#1789,.F.);
#1791=ORIENTED_EDGE('',*,*,#1639,.F.);
#1792=ORIENTED_EDGE('',*,*,#1764,.T.);
#1793=EDGE_LOOP('',(#1784,#1790,#1791,#1792));
#1794=FACE_BOUND('',#1793,.T.);
#1795=ADVANCED_FACE('P0_F1877',(#1794),#1776,.F.);
#1796=CARTESIAN_POINT('',(20.9,-5.98391850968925,24.9551));
#1797=CARTESIAN_POINT('',(21.,-5.98391850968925,24.9551));
#1798=CARTESIAN_POINT('',(20.9,-5.98391850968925,24.4214));
#1799=CARTESIAN_POINT('',(21.,-5.98391850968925,24.4214));
#1800=CARTESIAN_POINT('',(20.9,-5.54711850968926,23.9846));
#1801=CARTESIAN_POINT('',(21.,-5.54711850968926,23.9846));
#1802=CARTESIAN_POINT('',(20.9,-5.01321850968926,23.9846));
#1803=CARTESIAN_POINT('',(21.,-5.01321850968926,23.9846));
#1804=(BOUNDED_SURFACE() B_SPLINE_SURFACE(3,1,((#1796,#1797),(#1798,#1799),(#1800,#1801),(#1802,
#1803)),.UNSPECIFIED.,.F.,.F.,.F.) B_SPLINE_SURFACE_WITH_KNOTS((4,4),(2,2),(0.375,0.5),(0.,1.),
.UNSPECIFIED.) GEOMETRIC_REPRESENTATION_ITEM() RATIONAL_B_SPLINE_SURFACE(((1.,1.),(1.,1.),(1.,
1.),(1.,1.))) REPRESENTATION_ITEM('') SURFACE());
#1805=CARTESIAN_POINT('',(21.,-5.98391850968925,24.9551));
#1806=CARTESIAN_POINT('',(21.,-5.98391850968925,24.4214));
#1807=CARTESIAN_POINT('',(21.,-5.54711850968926,23.9846));
#1808=CARTESIAN_POINT('',(21.,-5.01321850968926,23.9846));
#1809=(BOUNDED_CURVE() B_SPLINE_CURVE(3,(#1805,#1806,#1807,#1808),.UNSPECIFIED.,.F.,
.F.) B_SPLINE_CURVE_WITH_KNOTS((4,4),(0.375,0.5),
.UNSPECIFIED.) CURVE() GEOMETRIC_REPRESENTATION_ITEM() RATIONAL_B_SPLINE_CURVE((1.,1.,1.,1.)) REPRESENTATION_ITEM(''));
#1810=CARTESIAN_POINT('',(21.,-5.01321850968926,23.9846));
#1811=VERTEX_POINT('',#1810);
#1812=EDGE_CURVE('P0_E1113',#1782,#1811,#1809,.T.);
#1813=DIRECTION('',(1.,0.,0.));
#1814=VECTOR('',#1813,1.);
#1815=CARTESIAN_POINT('',(20.9,-5.01321850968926,23.9846));
#1816=LINE('',#1815,#1814);
#1817=EDGE_CURVE('P0_E773',#1647,#1811,#1816,.T.);
#1818=ORIENTED_EDGE('',*,*,#1812,.T.);
#1819=ORIENTED_EDGE('',*,*,#1817,.F.);
#1820=ORIENTED_EDGE('',*,*,#1648,.F.);
#1821=ORIENTED_EDGE('',*,*,#1789,.T.);
#1822=EDGE_LOOP('',(#1818,#1819,#1820,#1821));
#1823=FACE_BOUND('',#1822,.T.);
#1824=ADVANCED_FACE('P0_F1872',(#1823),#1804,.F.);
#1825=CARTESIAN_POINT('',(20.9,5.05098149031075,23.9846));
#1826=DIRECTION('',(0.,0.,-1.));
#1827=DIRECTION('',(0.,-1.,0.));
#1828=AXIS2_PLACEMENT_3D('',#1825,#1826,#1827);
#1829=PLANE('',#1828);
#1830=DIRECTION('',(0.,1.,0.));
#1831=VECTOR('',#1830,1.);
#1832=CARTESIAN_POINT('',(21.,5.05098149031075,23.9846));
#1833=LINE('',#1832,#1831);
#1834=CARTESIAN_POINT('',(21.,5.05098149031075,23.9846));
#1835=VERTEX_POINT('',#1834);
#1836=EDGE_CURVE('P0_E1106',#1811,#1835,#1833,.T.);
#1837=ORIENTED_EDGE('',*,*,#1836,.T.);
#1838=DIRECTION('',(1.,0.,0.));
#1839=VECTOR('',#1838,1.);
#1840=CARTESIAN_POINT('',(20.9,5.05098149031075,23.9846));
#1841=LINE('',#1840,#1839);
#1842=EDGE_CURVE('P0_E776',#1594,#1835,#1841,.T.);
#1843=ORIENTED_EDGE('',*,*,#1842,.F.);
#1844=ORIENTED_EDGE('',*,*,#1654,.F.);
#1845=ORIENTED_EDGE('',*,*,#1817,.T.);
#1846=EDGE_LOOP('',(#1837,#1843,#1844,#1845));
#1847=FACE_BOUND('',#1846,.T.);
#1848=ADVANCED_FACE('P0_F1865',(#1847),#1829,.F.);
#1849=CARTESIAN_POINT('',(20.9,5.05098149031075,23.9846));
#1850=CARTESIAN_POINT('',(21.,5.05098149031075,23.9846));
#1851=CARTESIAN_POINT('',(20.9,5.58488149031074,23.9846));
#1852=CARTESIAN_POINT('',(21.,5.58488149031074,23.9846));
#1853=CARTESIAN_POINT('',(20.9,6.02178149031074,24.4214));
#1854=CARTESIAN_POINT('',(21.,6.02178149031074,24.4214));
#1855=CARTESIAN_POINT('',(20.9,6.02178149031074,24.9551));
#1856=CARTESIAN_POINT('',(21.,6.02178149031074,24.9551));
#1857=(BOUNDED_SURFACE() B_SPLINE_SURFACE(3,1,((#1849,#1850),(#1851,#1852),(#1853,#1854),(#1855,
#1856)),.UNSPECIFIED.,.F.,.F.,.F.) B_SPLINE_SURFACE_WITH_KNOTS((4,4),(2,2),(0.125,0.25),(0.,1.),
.UNSPECIFIED.) GEOMETRIC_REPRESENTATION_ITEM() RATIONAL_B_SPLINE_SURFACE(((1.,1.),(1.,1.),(1.,
1.),(1.,1.))) REPRESENTATION_ITEM('') SURFACE());
#1858=CARTESIAN_POINT('',(21.,5.05098149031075,23.9846));
#1859=CARTESIAN_POINT('',(21.,5.58488149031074,23.9846));
#1860=CARTESIAN_POINT('',(21.,6.02178149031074,24.4214));
#1861=CARTESIAN_POINT('',(21.,6.02178149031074,24.9551));
#1862=(BOUNDED_CURVE() B_SPLINE_CURVE(3,(#1858,#1859,#1860,#1861),.UNSPECIFIED.,.F.,
.F.) B_SPLINE_CURVE_WITH_KNOTS((4,4),(0.125,0.25),
.UNSPECIFIED.) CURVE() GEOMETRIC_REPRESENTATION_ITEM() RATIONAL_B_SPLINE_CURVE((1.,1.,1.,1.)) REPRESENTATION_ITEM(''));
#1863=EDGE_CURVE('P0_E1093',#1835,#1669,#1862,.T.);
#1864=ORIENTED_EDGE('',*,*,#1863,.T.);
#1865=ORIENTED_EDGE('',*,*,#1685,.F.);
#1866=ORIENTED_EDGE('',*,*,#1597,.F.);
#1867=ORIENTED_EDGE('',*,*,#1842,.T.);
#1868=EDGE_LOOP('',(#1864,#1865,#1866,#1867));
#1869=FACE_BOUND('',#1868,.T.);
#1870=ADVANCED_FACE('P0_F1856',(#1869),#1857,.F.);
#1871=CARTESIAN_POINT('',(0.,25.3,0.));
#1872=DIRECTION('',(0.,1.,0.));
#1873=DIRECTION('',(1.,0.,0.));
#1874=AXIS2_PLACEMENT_3D('',#1871,#1872,#1873);
#1875=PLANE('',#1874);
#1876=DIRECTION('',(0.,0.,1.));
#1877=VECTOR('',#1876,1.);
#1878=CARTESIAN_POINT('',(-8.25,25.3,0.));
#1879=LINE('',#1878,#1877);
#1880=CARTESIAN_POINT('',(-8.25,25.3,0.));
#1881=VERTEX_POINT('',#1880);
#1882=CARTESIAN_POINT('',(-8.25,25.3,3.));
#1883=VERTEX_POINT('',#1882);
#1884=EDGE_CURVE('P0_E967',#1881,#1883,#1879,.T.);
#1885=ORIENTED_EDGE('',*,*,#1884,.T.);
#1886=DIRECTION('',(1.,0.,0.));
#1887=VECTOR('',#1886,1.);
#1888=CARTESIAN_POINT('',(0.,25.3,3.));
#1889=LINE('',#1888,#1887);
#1890=CARTESIAN_POINT('',(8.25,25.3,3.));
#1891=VERTEX_POINT('',#1890);
#1892=EDGE_CURVE('P0_E1138',#1883,#1891,#1889,.T.);
#1893=ORIENTED_EDGE('',*,*,#1892,.T.);
#1894=DIRECTION('',(0.,0.,1.));
#1895=VECTOR('',#1894,1.);
#1896=CARTESIAN_POINT('',(8.25,25.3,0.));
#1897=LINE('',#1896,#1895);
#1898=CARTESIAN_POINT('',(8.25,25.3,0.));
#1899=VERTEX_POINT('',#1898);
#1900=EDGE_CURVE('P0_E1126',#1899,#1891,#1897,.T.);
#1901=ORIENTED_EDGE('',*,*,#1900,.F.);
#1902=DIRECTION('',(-1.,0.,0.));
#1903=VECTOR('',#1902,1.);
#1904=CARTESIAN_POINT('',(0.,25.3,0.));
#1905=LINE('',#1904,#1903);
#1906=EDGE_CURVE('P0_E919',#1899,#1881,#1905,.T.);
#1907=ORIENTED_EDGE('',*,*,#1906,.T.);
#1908=EDGE_LOOP('',(#1885,#1893,#1901,#1907));
#1909=FACE_BOUND('',#1908,.T.);
#1910=ADVANCED_FACE('P0_F1851',(#1909),#1875,.T.);
#1911=CARTESIAN_POINT('',(8.25,25.3,0.));
#1912=DIRECTION('',(1.,0.,0.));
#1913=DIRECTION('',(0.,1.,0.));
#1914=AXIS2_PLACEMENT_3D('',#1911,#1912,#1913);
#1915=PLANE('',#1914);
#1916=DIRECTION('',(0.,0.,1.));
#1917=VECTOR('',#1916,1.);
#1918=CARTESIAN_POINT('',(8.25,21.,0.));
#1919=LINE('',#1918,#1917);
#1920=CARTESIAN_POINT('',(8.25,21.,0.));
#1921=VERTEX_POINT('',#1920);
#1922=CARTESIAN_POINT('',(8.25,21.,3.));
#1923=VERTEX_POINT('',#1922);
#1924=EDGE_CURVE('P0_E848',#1921,#1923,#1919,.T.);
#1925=ORIENTED_EDGE('',*,*,#1924,.F.);
#1926=DIRECTION('',(0.,-1.,0.));
#1927=VECTOR('',#1926,1.);
#1928=CARTESIAN_POINT('',(8.25,25.3,0.));
#1929=LINE('',#1928,#1927);
#1930=EDGE_CURVE('P0_E918',#1899,#1921,#1929,.T.);
#1931=ORIENTED_EDGE('',*,*,#1930,.F.);
#1932=ORIENTED_EDGE('',*,*,#1900,.T.);
#1933=DIRECTION('',(0.,-1.,0.));
#1934=VECTOR('',#1933,1.);
#1935=CARTESIAN_POINT('',(8.25,25.3,3.));
#1936=LINE('',#1935,#1934);
#1937=EDGE_CURVE('P0_E1004',#1891,#1923,#1936,.T.);
#1938=ORIENTED_EDGE('',*,*,#1937,.T.);
#1939=EDGE_LOOP('',(#1925,#1931,#1932,#1938));
#1940=FACE_BOUND('',#1939,.T.);
#1941=ADVANCED_FACE('P0_F1853',(#1940),#1915,.T.);
#1942=CARTESIAN_POINT('',(0.,25.3,3.));
#1943=DIRECTION('',(0.,0.,-1.));
#1944=DIRECTION('',(-1.,0.,0.));
#1945=AXIS2_PLACEMENT_3D('',#1942,#1943,#1944);
#1946=PLANE('',#1945);
#1947=DIRECTION('',(1.,0.,0.));
#1948=VECTOR('',#1947,1.);
#1949=CARTESIAN_POINT('',(0.,21.,3.));
#1950=LINE('',#1949,#1948);
#1951=CARTESIAN_POINT('',(-8.25,21.,3.));
#1952=VERTEX_POINT('',#1951);
#1953=EDGE_CURVE('P0_E842',#1952,#1923,#1950,.T.);
#1954=ORIENTED_EDGE('',*,*,#1953,.T.);
#1955=ORIENTED_EDGE('',*,*,#1937,.F.);
#1956=ORIENTED_EDGE('',*,*,#1892,.F.);
#1957=DIRECTION('',(0.,-1.,0.));
#1958=VECTOR('',#1957,1.);
#1959=CARTESIAN_POINT('',(-8.25,25.3,3.));
#1960=LINE('',#1959,#1958);
#1961=EDGE_CURVE('P0_E961',#1883,#1952,#1960,.T.);
#1962=ORIENTED_EDGE('',*,*,#1961,.T.);
#1963=EDGE_LOOP('',(#1954,#1955,#1956,#1962));
#1964=FACE_BOUND('',#1963,.T.);
#1965=ADVANCED_FACE('P0_F3215',(#1964),#1946,.F.);
#1966=CARTESIAN_POINT('',(-8.25,25.3,0.));
#1967=DIRECTION('',(1.,0.,0.));
#1968=DIRECTION('',(0.,0.,-1.));
#1969=AXIS2_PLACEMENT_3D('',#1966,#1967,#1968);
#1970=PLANE('',#1969);
#1971=DIRECTION('',(0.,0.,1.));
#1972=VECTOR('',#1971,1.);
#1973=CARTESIAN_POINT('',(-8.25,21.,0.));
#1974=LINE('',#1973,#1972);
#1975=CARTESIAN_POINT('',(-8.25,21.,0.));
#1976=VERTEX_POINT('',#1975);
#1977=EDGE_CURVE('P0_E865',#1976,#1952,#1974,.T.);
#1978=ORIENTED_EDGE('',*,*,#1977,.T.);
#1979=ORIENTED_EDGE('',*,*,#1961,.F.);
#1980=ORIENTED_EDGE('',*,*,#1884,.F.);
#1981=DIRECTION('',(0.,-1.,0.));
#1982=VECTOR('',#1981,1.);
#1983=CARTESIAN_POINT('',(-8.25,25.3,0.));
#1984=LINE('',#1983,#1982);
#1985=EDGE_CURVE('P0_E813',#1881,#1976,#1984,.T.);
#1986=ORIENTED_EDGE('',*,*,#1985,.T.);
#1987=EDGE_LOOP('',(#1978,#1979,#1980,#1986));
#1988=FACE_BOUND('',#1987,.T.);
#1989=ADVANCED_FACE('P0_F3203',(#1988),#1970,.F.);
#1990=CARTESIAN_POINT('',(0.,0.,84.));
#1991=DIRECTION('',(0.,0.,-1.));
#1992=DIRECTION('',(-1.,0.,0.));
#1993=AXIS2_PLACEMENT_3D('',#1990,#1991,#1992);
#1994=CONICAL_SURFACE('',#1993,2.2,0.785398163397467);
#1995=DIRECTION('',(-0.707106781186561,0.,-0.707106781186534));
#1996=VECTOR('',#1995,1.);
#1997=CARTESIAN_POINT('',(-2.2,0.,84.));
#1998=LINE('',#1997,#1996);
#1999=CARTESIAN_POINT('',(-2.2,0.,84.));
#2000=VERTEX_POINT('',#1999);
#2001=CARTESIAN_POINT('',(-2.5,0.,83.7));
#2002=VERTEX_POINT('',#2001);
#2003=EDGE_CURVE('P0_E722',#2000,#2002,#1998,.T.);
#2004=ORIENTED_EDGE('',*,*,#2003,.F.);
#2005=CARTESIAN_POINT('',(0.,0.,84.));
#2006=DIRECTION('',(0.,0.,1.));
#2007=DIRECTION('',(1.,0.,0.));
#2008=AXIS2_PLACEMENT_3D('',#2005,#2006,#2007);
#2009=CIRCLE('',#2008,2.2);
#2010=CARTESIAN_POINT('',(-0.91651513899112,2.,84.));
#2011=VERTEX_POINT('',#2010);
#2012=EDGE_CURVE('P0_E966',#2011,#2000,#2009,.T.);
#2013=ORIENTED_EDGE('',*,*,#2012,.F.);
#2014=CARTESIAN_POINT('',(-1.5,2.,83.6999999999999));
#2015=CARTESIAN_POINT('',(-1.18963571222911,2.,83.8862185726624));
#2016=CARTESIAN_POINT('',(-0.91651513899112,2.,83.9999999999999));
#2017=B_SPLINE_CURVE_WITH_KNOTS('',2,(#2014,#2015,#2016),.UNSPECIFIED.,.F.,.F.,(3,3),(0.,1.),.UNSPECIFIED.);
#2018=CARTESIAN_POINT('',(-1.5,2.,83.7));
#2019=VERTEX_POINT('',#2018);
#2020=EDGE_CURVE('P0_E1669',#2019,#2011,#2017,.T.);
#2021=ORIENTED_EDGE('',*,*,#2020,.F.);
#2022=CARTESIAN_POINT('',(0.,0.,83.7));
#2023=DIRECTION('',(0.,0.,-1.));
#2024=DIRECTION('',(1.,0.,0.));
#2025=AXIS2_PLACEMENT_3D('',#2022,#2023,#2024);
#2026=CIRCLE('',#2025,2.5);
#2027=EDGE_CURVE('P0_E2505',#2002,#2019,#2026,.T.);
#2028=ORIENTED_EDGE('',*,*,#2027,.F.);
#2029=EDGE_LOOP('',(#2004,#2013,#2021,#2028));
#2030=FACE_BOUND('',#2029,.T.);
#2031=ADVANCED_FACE('P0_F3190',(#2030),#1994,.T.);
#2032=CARTESIAN_POINT('',(0.,0.,84.));
#2033=DIRECTION('',(0.,0.,1.));
#2034=DIRECTION('',(1.,0.,0.));
#2035=AXIS2_PLACEMENT_3D('',#2032,#2033,#2034);
#2036=PLANE('',#2035);
#2037=DIRECTION('',(1.,0.,0.));
#2038=VECTOR('',#2037,1.);
#2039=CARTESIAN_POINT('',(0.,2.,84.));
#2040=LINE('',#2039,#2038);
#2041=CARTESIAN_POINT('',(0.91651513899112,2.,84.));
#2042=VERTEX_POINT('',#2041);
#2043=EDGE_CURVE('P0_E1145',#2011,#2042,#2040,.T.);
#2044=ORIENTED_EDGE('',*,*,#2043,.F.);
#2045=ORIENTED_EDGE('',*,*,#2012,.T.);
#2046=CARTESIAN_POINT('',(0.,0.,84.));
#2047=DIRECTION('',(0.,0.,1.));
#2048=DIRECTION('',(1.,0.,0.));
#2049=AXIS2_PLACEMENT_3D('',#2046,#2047,#2048);
#2050=CIRCLE('',#2049,2.2);
#2051=CARTESIAN_POINT('',(2.2,0.,84.));
#2052=VERTEX_POINT('',#2051);
#2053=EDGE_CURVE('P0_E727',#2000,#2052,#2050,.T.);
#2054=ORIENTED_EDGE('',*,*,#2053,.T.);
#2055=CARTESIAN_POINT('',(0.,0.,84.));
#2056=DIRECTION('',(0.,0.,1.));
#2057=DIRECTION('',(1.,0.,0.));
#2058=AXIS2_PLACEMENT_3D('',#2055,#2056,#2057);
#2059=CIRCLE('',#2058,2.2);
#2060=EDGE_CURVE('P0_E1720',#2052,#2042,#2059,.T.);
#2061=ORIENTED_EDGE('',*,*,#2060,.T.);
#2062=EDGE_LOOP('',(#2044,#2045,#2054,#2061));
#2063=FACE_BOUND('',#2062,.T.);
#2064=ADVANCED_FACE('P0_F3177',(#2063),#2036,.T.);
#2065=CARTESIAN_POINT('',(0.,0.,112.726812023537));
#2066=DIRECTION('',(0.,0.,-1.));
#2067=DIRECTION('',(-1.,0.,0.));
#2068=AXIS2_PLACEMENT_3D('',#2065,#2066,#2067);
#2069=CYLINDRICAL_SURFACE('',#2068,2.5);
#2070=DIRECTION('',(0.,0.,-1.));
#2071=VECTOR('',#2070,1.);
#2072=CARTESIAN_POINT('',(-2.5,0.,112.726812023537));
#2073=LINE('',#2072,#2071);
#2074=CARTESIAN_POINT('',(-2.5,0.,62.));
#2075=VERTEX_POINT('',#2074);
#2076=EDGE_CURVE('P0_E692',#2002,#2075,#2073,.T.);
#2077=ORIENTED_EDGE('',*,*,#2076,.F.);
#2078=ORIENTED_EDGE('',*,*,#2027,.T.);
#2079=DIRECTION('',(0.,0.,-1.));
#2080=VECTOR('',#2079,1.);
#2081=CARTESIAN_POINT('',(-1.5,2.,112.726812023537));
#2082=LINE('',#2081,#2080);
#2083=CARTESIAN_POINT('',(-1.5,2.,62.));
#2084=VERTEX_POINT('',#2083);
#2085=EDGE_CURVE('P0_E2504',#2019,#2084,#2082,.T.);
#2086=ORIENTED_EDGE('',*,*,#2085,.T.);
#2087=CARTESIAN_POINT('',(0.,0.,62.));
#2088=DIRECTION('',(0.,0.,1.));
#2089=DIRECTION('',(1.,0.,0.));
#2090=AXIS2_PLACEMENT_3D('',#2087,#2088,#2089);
#2091=CIRCLE('',#2090,2.5);
#2092=EDGE_CURVE('P0_E802',#2084,#2075,#2091,.T.);
#2093=ORIENTED_EDGE('',*,*,#2092,.T.);
#2094=EDGE_LOOP('',(#2077,#2078,#2086,#2093));
#2095=FACE_BOUND('',#2094,.T.);
#2096=ADVANCED_FACE('P0_F1686',(#2095),#2069,.T.);
#2097=CARTESIAN_POINT('',(0.,2.,112.726812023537));
#2098=DIRECTION('',(0.,1.,0.));
#2099=DIRECTION('',(1.,0.,0.));
#2100=AXIS2_PLACEMENT_3D('',#2097,#2098,#2099);
#2101=PLANE('',#2100);
#2102=ORIENTED_EDGE('',*,*,#2043,.T.);
#2103=CARTESIAN_POINT('',(0.91651513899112,2.,83.9999999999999));
#2104=CARTESIAN_POINT('',(1.18963571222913,2.,83.8862185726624));
#2105=CARTESIAN_POINT('',(1.5,2.,83.6999999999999));
#2106=B_SPLINE_CURVE_WITH_KNOTS('',2,(#2103,#2104,#2105),.UNSPECIFIED.,.F.,.F.,(3,3),(0.,1.),.UNSPECIFIED.);
#2107=CARTESIAN_POINT('',(1.5,2.,83.7));
#2108=VERTEX_POINT('',#2107);
#2109=EDGE_CURVE('P0_E1711',#2042,#2108,#2106,.T.);
#2110=ORIENTED_EDGE('',*,*,#2109,.T.);
#2111=DIRECTION('',(0.,0.,-1.));
#2112=VECTOR('',#2111,1.);
#2113=CARTESIAN_POINT('',(1.5,2.,112.726812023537));
#2114=LINE('',#2113,#2112);
#2115=CARTESIAN_POINT('',(1.5,2.,62.));
#2116=VERTEX_POINT('',#2115);
#2117=EDGE_CURVE('P0_E710',#2108,#2116,#2114,.T.);
#2118=ORIENTED_EDGE('',*,*,#2117,.T.);
#2119=DIRECTION('',(-1.,0.,0.));
#2120=VECTOR('',#2119,1.);
#2121=CARTESIAN_POINT('',(-1.5,2.,62.));
#2122=LINE('',#2121,#2120);
#2123=EDGE_CURVE('P0_E703',#2116,#2084,#2122,.T.);
#2124=ORIENTED_EDGE('',*,*,#2123,.T.);
#2125=ORIENTED_EDGE('',*,*,#2085,.F.);
#2126=ORIENTED_EDGE('',*,*,#2020,.T.);
#2127=EDGE_LOOP('',(#2102,#2110,#2118,#2124,#2125,#2126));
#2128=FACE_BOUND('',#2127,.T.);
#2129=ADVANCED_FACE('P0_F1680',(#2128),#2101,.T.);
#2130=CARTESIAN_POINT('',(0.,0.,62.));
#2131=DIRECTION('',(0.,0.,-1.));
#2132=DIRECTION('',(-1.,0.,0.));
#2133=AXIS2_PLACEMENT_3D('',#2130,#2131,#2132);
#2134=CYLINDRICAL_SURFACE('',#2133,11.);
#2135=DIRECTION('',(0.,0.,-1.));
#2136=VECTOR('',#2135,1.);
#2137=CARTESIAN_POINT('',(11.,0.,62.));
#2138=LINE('',#2137,#2136);
#2139=CARTESIAN_POINT('',(11.,0.,62.));
#2140=VERTEX_POINT('',#2139);
#2141=CARTESIAN_POINT('',(11.,0.,60.));
#2142=VERTEX_POINT('',#2141);
#2143=EDGE_CURVE('P0_E741',#2140,#2142,#2138,.T.);
#2144=ORIENTED_EDGE('',*,*,#2143,.F.);
#2145=CARTESIAN_POINT('',(0.,0.,62.));
#2146=DIRECTION('',(0.,0.,1.));
#2147=DIRECTION('',(1.,0.,0.));
#2148=AXIS2_PLACEMENT_3D('',#2145,#2146,#2147);
#2149=CIRCLE('',#2148,11.);
#2150=CARTESIAN_POINT('',(-11.,0.,62.));
#2151=VERTEX_POINT('',#2150);
#2152=EDGE_CURVE('P0_E801',#2151,#2140,#2149,.T.);
#2153=ORIENTED_EDGE('',*,*,#2152,.F.);
#2154=DIRECTION('',(0.,0.,-1.));
#2155=VECTOR('',#2154,1.);
#2156=CARTESIAN_POINT('',(-11.,0.,62.));
#2157=LINE('',#2156,#2155);
#2158=CARTESIAN_POINT('',(-11.,0.,60.));
#2159=VERTEX_POINT('',#2158);
#2160=EDGE_CURVE('P0_E754',#2151,#2159,#2157,.T.);
#2161=ORIENTED_EDGE('',*,*,#2160,.T.);
#2162=CARTESIAN_POINT('',(0.,0.,60.));
#2163=DIRECTION('',(0.,0.,1.));
#2164=DIRECTION('',(1.,0.,0.));
#2165=AXIS2_PLACEMENT_3D('',#2162,#2163,#2164);
#2166=CIRCLE('',#2165,11.);
#2167=EDGE_CURVE('P0_E982',#2159,#2142,#2166,.T.);
#2168=ORIENTED_EDGE('',*,*,#2167,.T.);
#2169=EDGE_LOOP('',(#2144,#2153,#2161,#2168));
#2170=FACE_BOUND('',#2169,.T.);
#2171=ADVANCED_FACE('P0_F1690',(#2170),#2134,.T.);
#2172=CARTESIAN_POINT('',(0.,0.,62.));
#2173=DIRECTION('',(0.,0.,1.));
#2174=DIRECTION('',(1.,0.,0.));
#2175=AXIS2_PLACEMENT_3D('',#2172,#2173,#2174);
#2176=PLANE('',#2175);
#2177=ORIENTED_EDGE('',*,*,#2123,.F.);
#2178=CARTESIAN_POINT('',(0.,0.,62.));
#2179=DIRECTION('',(0.,0.,1.));
#2180=DIRECTION('',(1.,0.,0.));
#2181=AXIS2_PLACEMENT_3D('',#2178,#2179,#2180);
#2182=CIRCLE('',#2181,2.5);
#2183=CARTESIAN_POINT('',(2.5,0.,62.));
#2184=VERTEX_POINT('',#2183);
#2185=EDGE_CURVE('P0_E699',#2184,#2116,#2182,.T.);
#2186=ORIENTED_EDGE('',*,*,#2185,.F.);
#2187=CARTESIAN_POINT('',(0.,0.,62.));
#2188=DIRECTION('',(0.,0.,1.));
#2189=DIRECTION('',(1.,0.,0.));
#2190=AXIS2_PLACEMENT_3D('',#2187,#2188,#2189);
#2191=CIRCLE('',#2190,2.5);
#2192=EDGE_CURVE('P0_E683',#2075,#2184,#2191,.T.);
#2193=ORIENTED_EDGE('',*,*,#2192,.F.);
#2194=ORIENTED_EDGE('',*,*,#2092,.F.);
#2195=EDGE_LOOP('',(#2177,#2186,#2193,#2194));
#2196=FACE_BOUND('',#2195,.T.);
#2197=ORIENTED_EDGE('',*,*,#2152,.T.);
#2198=CARTESIAN_POINT('',(0.,0.,62.));
#2199=DIRECTION('',(0.,0.,1.));
#2200=DIRECTION('',(1.,0.,0.));
#2201=AXIS2_PLACEMENT_3D('',#2198,#2199,#2200);
#2202=CIRCLE('',#2201,11.);
#2203=EDGE_CURVE('P0_E698',#2140,#2151,#2202,.T.);
#2204=ORIENTED_EDGE('',*,*,#2203,.T.);
#2205=EDGE_LOOP('',(#2197,#2204));
#2206=FACE_BOUND('',#2205,.T.);
#2207=ADVANCED_FACE('P0_F697',(#2196,#2206),#2176,.T.);
#2208=CARTESIAN_POINT('',(-15.5,-15.5,60.));
#2209=DIRECTION('',(0.,0.,-1.));
#2210=DIRECTION('',(-1.,0.,0.));
#2211=AXIS2_PLACEMENT_3D('',#2208,#2209,#2210);
#2212=CYLINDRICAL_SURFACE('',#2211,1.5);
#2213=DIRECTION('',(0.,0.,-1.));
#2214=VECTOR('',#2213,1.);
#2215=CARTESIAN_POINT('',(-14.,-15.5,60.));
#2216=LINE('',#2215,#2214);
#2217=CARTESIAN_POINT('',(-14.,-15.5,60.));
#2218=VERTEX_POINT('',#2217);
#2219=CARTESIAN_POINT('',(-14.,-15.5,0.));
#2220=VERTEX_POINT('',#2219);
#2221=EDGE_CURVE('P0_E751',#2218,#2220,#2216,.T.);
#2222=ORIENTED_EDGE('',*,*,#2221,.F.);
#2223=CARTESIAN_POINT('',(-15.5,-15.5,60.));
#2224=DIRECTION('',(0.,0.,1.));
#2225=DIRECTION('',(1.,0.,0.));
#2226=AXIS2_PLACEMENT_3D('',#2223,#2224,#2225);
#2227=CIRCLE('',#2226,1.5);
#2228=CARTESIAN_POINT('',(-17.,-15.5,60.));
#2229=VERTEX_POINT('',#2228);
#2230=EDGE_CURVE('P0_E981',#2218,#2229,#2227,.T.);
#2231=ORIENTED_EDGE('',*,*,#2230,.T.);
#2232=DIRECTION('',(0.,0.,-1.));
#2233=VECTOR('',#2232,1.);
#2234=CARTESIAN_POINT('',(-17.,-15.5,60.));
#2235=LINE('',#2234,#2233);
#2236=CARTESIAN_POINT('',(-17.,-15.5,0.));
#2237=VERTEX_POINT('',#2236);
#2238=EDGE_CURVE('P0_E770',#2229,#2237,#2235,.T.);
#2239=ORIENTED_EDGE('',*,*,#2238,.T.);
#2240=CARTESIAN_POINT('',(-15.5,-15.5,0.));
#2241=DIRECTION('',(0.,0.,1.));
#2242=DIRECTION('',(1.,0.,0.));
#2243=AXIS2_PLACEMENT_3D('',#2240,#2241,#2242);
#2244=CIRCLE('',#2243,1.5);
#2245=EDGE_CURVE('P0_E970',#2220,#2237,#2244,.T.);
#2246=ORIENTED_EDGE('',*,*,#2245,.F.);
#2247=EDGE_LOOP('',(#2222,#2231,#2239,#2246));
#2248=FACE_BOUND('',#2247,.T.);
#2249=ADVANCED_FACE('P0_F1775',(#2248),#2212,.F.);
#2250=CARTESIAN_POINT('',(15.5,-15.5,60.));
#2251=DIRECTION('',(0.,0.,-1.));
#2252=DIRECTION('',(-1.,0.,0.));
#2253=AXIS2_PLACEMENT_3D('',#2250,#2251,#2252);
#2254=CYLINDRICAL_SURFACE('',#2253,1.5);
#2255=DIRECTION('',(0.,0.,-1.));
#2256=VECTOR('',#2255,1.);
#2257=CARTESIAN_POINT('',(17.,-15.5,60.));
#2258=LINE('',#2257,#2256);
#2259=CARTESIAN_POINT('',(17.,-15.5,60.));
#2260=VERTEX_POINT('',#2259);
#2261=CARTESIAN_POINT('',(17.,-15.5,0.));
#2262=VERTEX_POINT('',#2261);
#2263=EDGE_CURVE('P0_E795',#2260,#2262,#2258,.T.);
#2264=ORIENTED_EDGE('',*,*,#2263,.F.);
#2265=CARTESIAN_POINT('',(15.5,-15.5,60.));
#2266=DIRECTION('',(0.,0.,1.));
#2267=DIRECTION('',(1.,0.,0.));
#2268=AXIS2_PLACEMENT_3D('',#2265,#2266,#2267);
#2269=CIRCLE('',#2268,1.5);
#2270=CARTESIAN_POINT('',(14.,-15.5,60.));
#2271=VERTEX_POINT('',#2270);
#2272=EDGE_CURVE('P0_E978',#2260,#2271,#2269,.T.);
#2273=ORIENTED_EDGE('',*,*,#2272,.T.);
#2274=DIRECTION('',(0.,0.,-1.));
#2275=VECTOR('',#2274,1.);
#2276=CARTESIAN_POINT('',(14.,-15.5,60.));
#2277=LINE('',#2276,#2275);
#2278=CARTESIAN_POINT('',(14.,-15.5,0.));
#2279=VERTEX_POINT('',#2278);
#2280=EDGE_CURVE('P0_E788',#2271,#2279,#2277,.T.);
#2281=ORIENTED_EDGE('',*,*,#2280,.T.);
#2282=CARTESIAN_POINT('',(15.5,-15.5,0.));
#2283=DIRECTION('',(0.,0.,1.));
#2284=DIRECTION('',(1.,0.,0.));
#2285=AXIS2_PLACEMENT_3D('',#2282,#2283,#2284);
#2286=CIRCLE('',#2285,1.5);
#2287=EDGE_CURVE('P0_E872',#2262,#2279,#2286,.T.);
#2288=ORIENTED_EDGE('',*,*,#2287,.F.);
#2289=EDGE_LOOP('',(#2264,#2273,#2281,#2288));
#2290=FACE_BOUND('',#2289,.T.);
#2291=ADVANCED_FACE('P0_F1831',(#2290),#2254,.F.);
#2292=CARTESIAN_POINT('',(15.5,15.5,60.));
#2293=DIRECTION('',(0.,0.,-1.));
#2294=DIRECTION('',(-1.,0.,0.));
#2295=AXIS2_PLACEMENT_3D('',#2292,#2293,#2294);
#2296=CYLINDRICAL_SURFACE('',#2295,1.5);
#2297=DIRECTION('',(0.,0.,-1.));
#2298=VECTOR('',#2297,1.);
#2299=CARTESIAN_POINT('',(17.,15.5,60.));
#2300=LINE('',#2299,#2298);
#2301=CARTESIAN_POINT('',(17.,15.5,60.));
#2302=VERTEX_POINT('',#2301);
#2303=CARTESIAN_POINT('',(17.,15.5,0.));
#2304=VERTEX_POINT('',#2303);
#2305=EDGE_CURVE('P0_E786',#2302,#2304,#2300,.T.);
#2306=ORIENTED_EDGE('',*,*,#2305,.F.);
#2307=CARTESIAN_POINT('',(15.5,15.5,60.));
#2308=DIRECTION('',(0.,0.,1.));
#2309=DIRECTION('',(1.,0.,0.));
#2310=AXIS2_PLACEMENT_3D('',#2307,#2308,#2309);
#2311=CIRCLE('',#2310,1.5);
#2312=CARTESIAN_POINT('',(14.,15.5,60.));
#2313=VERTEX_POINT('',#2312);
#2314=EDGE_CURVE('P0_E972',#2302,#2313,#2311,.T.);
#2315=ORIENTED_EDGE('',*,*,#2314,.T.);
#2316=DIRECTION('',(0.,0.,-1.));
#2317=VECTOR('',#2316,1.);
#2318=CARTESIAN_POINT('',(14.,15.5,60.));
#2319=LINE('',#2318,#2317);
#2320=CARTESIAN_POINT('',(14.,15.5,0.));
#2321=VERTEX_POINT('',#2320);
#2322=EDGE_CURVE('P0_E831',#2313,#2321,#2319,.T.);
#2323=ORIENTED_EDGE('',*,*,#2322,.T.);
#2324=CARTESIAN_POINT('',(15.5,15.5,0.));
#2325=DIRECTION('',(0.,0.,1.));
#2326=DIRECTION('',(1.,0.,0.));
#2327=AXIS2_PLACEMENT_3D('',#2324,#2325,#2326);
#2328=CIRCLE('',#2327,1.5);
#2329=EDGE_CURVE('P0_E873',#2304,#2321,#2328,.T.);
#2330=ORIENTED_EDGE('',*,*,#2329,.F.);
#2331=EDGE_LOOP('',(#2306,#2315,#2323,#2330));
#2332=FACE_BOUND('',#2331,.T.);
#2333=ADVANCED_FACE('P0_F1822',(#2332),#2296,.F.);
#2334=CARTESIAN_POINT('',(-15.5,15.5,60.));
#2335=DIRECTION('',(0.,0.,-1.));
#2336=DIRECTION('',(-1.,0.,0.));
#2337=AXIS2_PLACEMENT_3D('',#2334,#2335,#2336);
#2338=CYLINDRICAL_SURFACE('',#2337,1.5);
#2339=DIRECTION('',(0.,0.,-1.));
#2340=VECTOR('',#2339,1.);
#2341=CARTESIAN_POINT('',(-14.,15.5,60.));
#2342=LINE('',#2341,#2340);
#2343=CARTESIAN_POINT('',(-14.,15.5,60.));
#2344=VERTEX_POINT('',#2343);
#2345=CARTESIAN_POINT('',(-14.,15.5,0.));
#2346=VERTEX_POINT('',#2345);
#2347=EDGE_CURVE('P0_E814',#2344,#2346,#2342,.T.);
#2348=ORIENTED_EDGE('',*,*,#2347,.F.);
#2349=CARTESIAN_POINT('',(-15.5,15.5,60.));
#2350=DIRECTION('',(0.,0.,1.));
#2351=DIRECTION('',(1.,0.,0.));
#2352=AXIS2_PLACEMENT_3D('',#2349,#2350,#2351);
#2353=CIRCLE('',#2352,1.5);
#2354=CARTESIAN_POINT('',(-17.,15.5,60.));
#2355=VERTEX_POINT('',#2354);
#2356=EDGE_CURVE('P0_E964',#2344,#2355,#2353,.T.);
#2357=ORIENTED_EDGE('',*,*,#2356,.T.);
#2358=DIRECTION('',(0.,0.,-1.));
#2359=VECTOR('',#2358,1.);
#2360=CARTESIAN_POINT('',(-17.,15.5,60.));
#2361=LINE('',#2360,#2359);
#2362=CARTESIAN_POINT('',(-17.,15.5,0.));
#2363=VERTEX_POINT('',#2362);
#2364=EDGE_CURVE('P0_E854',#2355,#2363,#2361,.T.);
#2365=ORIENTED_EDGE('',*,*,#2364,.T.);
#2366=CARTESIAN_POINT('',(-15.5,15.5,0.));
#2367=DIRECTION('',(0.,0.,1.));
#2368=DIRECTION('',(1.,0.,0.));
#2369=AXIS2_PLACEMENT_3D('',#2366,#2367,#2368);
#2370=CIRCLE('',#2369,1.5);
#2371=EDGE_CURVE('P0_E869',#2346,#2363,#2370,.T.);
#2372=ORIENTED_EDGE('',*,*,#2371,.F.);
#2373=EDGE_LOOP('',(#2348,#2357,#2365,#2372));
#2374=FACE_BOUND('',#2373,.T.);
#2375=ADVANCED_FACE('P0_F1819',(#2374),#2338,.F.);
#2376=CARTESIAN_POINT('',(16.8,21.,60.));
#2377=DIRECTION('',(-0.707106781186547,-0.707106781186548,0.));
#2378=DIRECTION('',(-0.707106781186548,0.707106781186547,0.));
#2379=AXIS2_PLACEMENT_3D('',#2376,#2377,#2378);
#2380=PLANE('',#2379);
#2381=DIRECTION('',(-0.707106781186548,0.707106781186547,0.));
#2382=VECTOR('',#2381,1.);
#2383=CARTESIAN_POINT('',(16.8,21.,0.));
#2384=LINE('',#2383,#2382);
#2385=CARTESIAN_POINT('',(21.,16.8,0.));
#2386=VERTEX_POINT('',#2385);
#2387=CARTESIAN_POINT('',(16.8,21.,0.));
#2388=VERTEX_POINT('',#2387);
#2389=EDGE_CURVE('P0_E998',#2386,#2388,#2384,.T.);
#2390=ORIENTED_EDGE('',*,*,#2389,.T.);
#2391=DIRECTION('',(0.,0.,-1.));
#2392=VECTOR('',#2391,1.);
#2393=CARTESIAN_POINT('',(16.8,21.,60.));
#2394=LINE('',#2393,#2392);
#2395=CARTESIAN_POINT('',(16.8,21.,60.));
#2396=VERTEX_POINT('',#2395);
#2397=EDGE_CURVE('P0_E896',#2396,#2388,#2394,.T.);
#2398=ORIENTED_EDGE('',*,*,#2397,.F.);
#2399=DIRECTION('',(-0.707106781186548,0.707106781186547,0.));
#2400=VECTOR('',#2399,1.);
#2401=CARTESIAN_POINT('',(16.8,21.,60.));
#2402=LINE('',#2401,#2400);
#2403=CARTESIAN_POINT('',(21.,16.8,60.));
#2404=VERTEX_POINT('',#2403);
#2405=EDGE_CURVE('P0_E949',#2404,#2396,#2402,.T.);
#2406=ORIENTED_EDGE('',*,*,#2405,.F.);
#2407=DIRECTION('',(0.,0.,-1.));
#2408=VECTOR('',#2407,1.);
#2409=CARTESIAN_POINT('',(21.,16.8,60.));
#2410=LINE('',#2409,#2408);
#2411=EDGE_CURVE('P0_E1079',#2404,#2386,#2410,.T.);
#2412=ORIENTED_EDGE('',*,*,#2411,.T.);
#2413=EDGE_LOOP('',(#2390,#2398,#2406,#2412));
#2414=FACE_BOUND('',#2413,.T.);
#2415=ADVANCED_FACE('P0_F1821',(#2414),#2380,.F.);
#2416=CARTESIAN_POINT('',(21.,16.8,60.));
#2417=DIRECTION('',(-1.,0.,0.));
#2418=DIRECTION('',(0.,1.,0.));
#2419=AXIS2_PLACEMENT_3D('',#2416,#2417,#2418);
#2420=PLANE('',#2419);
#2421=ORIENTED_EDGE('',*,*,#1672,.F.);
#2422=ORIENTED_EDGE('',*,*,#1863,.F.);
#2423=ORIENTED_EDGE('',*,*,#1836,.F.);
#2424=ORIENTED_EDGE('',*,*,#1812,.F.);
#2425=ORIENTED_EDGE('',*,*,#1783,.F.);
#2426=ORIENTED_EDGE('',*,*,#1759,.F.);
#2427=ORIENTED_EDGE('',*,*,#1730,.F.);
#2428=ORIENTED_EDGE('',*,*,#1706,.F.);
#2429=EDGE_LOOP('',(#2421,#2422,#2423,#2424,#2425,#2426,#2427,#2428));
#2430=FACE_BOUND('',#2429,.T.);
#2431=DIRECTION('',(0.,1.,0.));
#2432=VECTOR('',#2431,1.);
#2433=CARTESIAN_POINT('',(21.,16.8,0.));
#2434=LINE('',#2433,#2432);
#2435=CARTESIAN_POINT('',(21.,-16.8,0.));
#2436=VERTEX_POINT('',#2435);
#2437=EDGE_CURVE('P0_E991',#2436,#2386,#2434,.T.);
#2438=ORIENTED_EDGE('',*,*,#2437,.T.);
#2439=ORIENTED_EDGE('',*,*,#2411,.F.);
#2440=DIRECTION('',(0.,1.,0.));
#2441=VECTOR('',#2440,1.);
#2442=CARTESIAN_POINT('',(21.,16.8,60.));
#2443=LINE('',#2442,#2441);
#2444=CARTESIAN_POINT('',(21.,-16.8,60.));
#2445=VERTEX_POINT('',#2444);
#2446=EDGE_CURVE('P0_E946',#2445,#2404,#2443,.T.);
#2447=ORIENTED_EDGE('',*,*,#2446,.F.);
#2448=DIRECTION('',(0.,0.,-1.));
#2449=VECTOR('',#2448,1.);
#2450=CARTESIAN_POINT('',(21.,-16.8,60.));
#2451=LINE('',#2450,#2449);
#2452=EDGE_CURVE('P0_E888',#2445,#2436,#2451,.T.);
#2453=ORIENTED_EDGE('',*,*,#2452,.T.);
#2454=EDGE_LOOP('',(#2438,#2439,#2447,#2453));
#2455=FACE_BOUND('',#2454,.T.);
#2456=ADVANCED_FACE('P0_F1817',(#2430,#2455),#2420,.F.);
#2457=CARTESIAN_POINT('',(16.8,-21.,60.));
#2458=DIRECTION('',(-0.707106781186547,0.707106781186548,0.));
#2459=DIRECTION('',(0.,0.,1.));
#2460=AXIS2_PLACEMENT_3D('',#2457,#2458,#2459);
#2461=PLANE('',#2460);
#2462=DIRECTION('',(0.707106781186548,0.707106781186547,0.));
#2463=VECTOR('',#2462,1.);
#2464=CARTESIAN_POINT('',(16.8,-21.,0.));
#2465=LINE('',#2464,#2463);
#2466=CARTESIAN_POINT('',(16.8,-21.,0.));
#2467=VERTEX_POINT('',#2466);
#2468=EDGE_CURVE('P0_E999',#2467,#2436,#2465,.T.);
#2469=ORIENTED_EDGE('',*,*,#2468,.T.);
#2470=ORIENTED_EDGE('',*,*,#2452,.F.);
#2471=DIRECTION('',(0.707106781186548,0.707106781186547,0.));
#2472=VECTOR('',#2471,1.);
#2473=CARTESIAN_POINT('',(16.8,-21.,60.));
#2474=LINE('',#2473,#2472);
#2475=CARTESIAN_POINT('',(16.8,-21.,60.));
#2476=VERTEX_POINT('',#2475);
#2477=EDGE_CURVE('P0_E941',#2476,#2445,#2474,.T.);
#2478=ORIENTED_EDGE('',*,*,#2477,.F.);
#2479=DIRECTION('',(0.,0.,-1.));
#2480=VECTOR('',#2479,1.);
#2481=CARTESIAN_POINT('',(16.8,-21.,60.));
#2482=LINE('',#2481,#2480);
#2483=EDGE_CURVE('P0_E810',#2476,#2467,#2482,.T.);
#2484=ORIENTED_EDGE('',*,*,#2483,.T.);
#2485=EDGE_LOOP('',(#2469,#2470,#2478,#2484));
#2486=FACE_BOUND('',#2485,.T.);
#2487=ADVANCED_FACE('P0_F1789',(#2486),#2461,.F.);
#2488=CARTESIAN_POINT('',(-16.8,-21.,60.));
#2489=DIRECTION('',(0.,1.,0.));
#2490=DIRECTION('',(1.,0.,0.));
#2491=AXIS2_PLACEMENT_3D('',#2488,#2489,#2490);
#2492=PLANE('',#2491);
#2493=DIRECTION('',(1.,0.,0.));
#2494=VECTOR('',#2493,1.);
#2495=CARTESIAN_POINT('',(-16.8,-21.,0.));
#2496=LINE('',#2495,#2494);
#2497=CARTESIAN_POINT('',(-16.8,-21.,0.));
#2498=VERTEX_POINT('',#2497);
#2499=EDGE_CURVE('P0_E1017',#2498,#2467,#2496,.T.);
#2500=ORIENTED_EDGE('',*,*,#2499,.T.);
#2501=ORIENTED_EDGE('',*,*,#2483,.F.);
#2502=DIRECTION('',(1.,0.,0.));
#2503=VECTOR('',#2502,1.);
#2504=CARTESIAN_POINT('',(-16.8,-21.,60.));
#2505=LINE('',#2504,#2503);
#2506=CARTESIAN_POINT('',(-16.8,-21.,60.));
#2507=VERTEX_POINT('',#2506);
#2508=EDGE_CURVE('P0_E940',#2507,#2476,#2505,.T.);
#2509=ORIENTED_EDGE('',*,*,#2508,.F.);
#2510=DIRECTION('',(0.,0.,-1.));
#2511=VECTOR('',#2510,1.);
#2512=CARTESIAN_POINT('',(-16.8,-21.,60.));
#2513=LINE('',#2512,#2511);
#2514=EDGE_CURVE('P0_E805',#2507,#2498,#2513,.T.);
#2515=ORIENTED_EDGE('',*,*,#2514,.T.);
#2516=EDGE_LOOP('',(#2500,#2501,#2509,#2515));
#2517=FACE_BOUND('',#2516,.T.);
#2518=ADVANCED_FACE('P0_F1784',(#2517),#2492,.F.);
#2519=CARTESIAN_POINT('',(-21.,-16.8,60.));
#2520=DIRECTION('',(0.707106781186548,0.707106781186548,0.));
#2521=DIRECTION('',(0.,0.,-1.));
#2522=AXIS2_PLACEMENT_3D('',#2519,#2520,#2521);
#2523=PLANE('',#2522);
#2524=DIRECTION('',(0.707106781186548,-0.707106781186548,0.));
#2525=VECTOR('',#2524,1.);
#2526=CARTESIAN_POINT('',(-21.,-16.8,0.));
#2527=LINE('',#2526,#2525);
#2528=CARTESIAN_POINT('',(-21.,-16.8,0.));
#2529=VERTEX_POINT('',#2528);
#2530=EDGE_CURVE('P0_E1031',#2529,#2498,#2527,.T.);
#2531=ORIENTED_EDGE('',*,*,#2530,.T.);
#2532=ORIENTED_EDGE('',*,*,#2514,.F.);
#2533=DIRECTION('',(0.707106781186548,-0.707106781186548,0.));
#2534=VECTOR('',#2533,1.);
#2535=CARTESIAN_POINT('',(-21.,-16.8,60.));
#2536=LINE('',#2535,#2534);
#2537=CARTESIAN_POINT('',(-21.,-16.8,60.));
#2538=VERTEX_POINT('',#2537);
#2539=EDGE_CURVE('P0_E932',#2538,#2507,#2536,.T.);
#2540=ORIENTED_EDGE('',*,*,#2539,.F.);
#2541=DIRECTION('',(0.,0.,-1.));
#2542=VECTOR('',#2541,1.);
#2543=CARTESIAN_POINT('',(-21.,-16.8,60.));
#2544=LINE('',#2543,#2542);
#2545=EDGE_CURVE('P0_E806',#2538,#2529,#2544,.T.);
#2546=ORIENTED_EDGE('',*,*,#2545,.T.);
#2547=EDGE_LOOP('',(#2531,#2532,#2540,#2546));
#2548=FACE_BOUND('',#2547,.T.);
#2549=ADVANCED_FACE('P0_F1759',(#2548),#2523,.F.);
#2550=CARTESIAN_POINT('',(-21.,16.8,60.));
#2551=DIRECTION('',(1.,0.,0.));
#2552=DIRECTION('',(0.,1.,0.));
#2553=AXIS2_PLACEMENT_3D('',#2550,#2551,#2552);
#2554=PLANE('',#2553);
#2555=DIRECTION('',(0.,-1.,0.));
#2556=VECTOR('',#2555,1.);
#2557=CARTESIAN_POINT('',(-21.,16.8,0.));
#2558=LINE('',#2557,#2556);
#2559=CARTESIAN_POINT('',(-21.,16.8,0.));
#2560=VERTEX_POINT('',#2559);
#2561=EDGE_CURVE('P0_E812',#2560,#2529,#2558,.T.);
#2562=ORIENTED_EDGE('',*,*,#2561,.T.);
#2563=ORIENTED_EDGE('',*,*,#2545,.F.);
#2564=DIRECTION('',(0.,-1.,0.));
#2565=VECTOR('',#2564,1.);
#2566=CARTESIAN_POINT('',(-21.,16.8,60.));
#2567=LINE('',#2566,#2565);
#2568=CARTESIAN_POINT('',(-21.,16.8,60.));
#2569=VERTEX_POINT('',#2568);
#2570=EDGE_CURVE('P0_E926',#2569,#2538,#2567,.T.);
#2571=ORIENTED_EDGE('',*,*,#2570,.F.);
#2572=DIRECTION('',(0.,0.,-1.));
#2573=VECTOR('',#2572,1.);
#2574=CARTESIAN_POINT('',(-21.,16.8,60.));
#2575=LINE('',#2574,#2573);
#2576=EDGE_CURVE('P0_E975',#2569,#2560,#2575,.T.);
#2577=ORIENTED_EDGE('',*,*,#2576,.T.);
#2578=EDGE_LOOP('',(#2562,#2563,#2571,#2577));
#2579=FACE_BOUND('',#2578,.T.);
#2580=ADVANCED_FACE('P0_F1760',(#2579),#2554,.F.);
#2581=CARTESIAN_POINT('',(-21.,16.8,60.));
#2582=DIRECTION('',(0.707106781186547,-0.707106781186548,0.));
#2583=DIRECTION('',(0.,0.,-1.));
#2584=AXIS2_PLACEMENT_3D('',#2581,#2582,#2583);
#2585=PLANE('',#2584);
#2586=DIRECTION('',(-0.707106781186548,-0.707106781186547,0.));
#2587=VECTOR('',#2586,1.);
#2588=CARTESIAN_POINT('',(-21.,16.8,0.));
#2589=LINE('',#2588,#2587);
#2590=CARTESIAN_POINT('',(-16.8,21.,0.));
#2591=VERTEX_POINT('',#2590);
#2592=EDGE_CURVE('P0_E809',#2591,#2560,#2589,.T.);
#2593=ORIENTED_EDGE('',*,*,#2592,.T.);
#2594=ORIENTED_EDGE('',*,*,#2576,.F.);
#2595=DIRECTION('',(-0.707106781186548,-0.707106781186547,0.));
#2596=VECTOR('',#2595,1.);
#2597=CARTESIAN_POINT('',(-21.,16.8,60.));
#2598=LINE('',#2597,#2596);
#2599=CARTESIAN_POINT('',(-16.8,21.,60.));
#2600=VERTEX_POINT('',#2599);
#2601=EDGE_CURVE('P0_E847',#2600,#2569,#2598,.T.);
#2602=ORIENTED_EDGE('',*,*,#2601,.F.);
#2603=DIRECTION('',(0.,0.,-1.));
#2604=VECTOR('',#2603,1.);
#2605=CARTESIAN_POINT('',(-16.8,21.,60.));
#2606=LINE('',#2605,#2604);
#2607=EDGE_CURVE('P0_E877',#2600,#2591,#2606,.T.);
#2608=ORIENTED_EDGE('',*,*,#2607,.T.);
#2609=EDGE_LOOP('',(#2593,#2594,#2602,#2608));
#2610=FACE_BOUND('',#2609,.T.);
#2611=ADVANCED_FACE('P0_F1743',(#2610),#2585,.F.);
#2612=CARTESIAN_POINT('',(0.,0.,0.));
#2613=DIRECTION('',(0.,0.,-1.));
#2614=DIRECTION('',(0.,-1.,0.));
#2615=AXIS2_PLACEMENT_3D('',#2612,#2613,#2614);
#2616=PLANE('',#2615);
#2617=CARTESIAN_POINT('',(-15.5,-15.5,0.));
#2618=DIRECTION('',(0.,0.,1.));
#2619=DIRECTION('',(1.,0.,0.));
#2620=AXIS2_PLACEMENT_3D('',#2617,#2618,#2619);
#2621=CIRCLE('',#2620,1.5);
#2622=EDGE_CURVE('P0_E763',#2237,#2220,#2621,.T.);
#2623=ORIENTED_EDGE('',*,*,#2622,.T.);
#2624=ORIENTED_EDGE('',*,*,#2245,.T.);
#2625=EDGE_LOOP('',(#2623,#2624));
#2626=FACE_BOUND('',#2625,.T.);
#2627=CARTESIAN_POINT('',(15.5,15.5,0.));
#2628=DIRECTION('',(0.,0.,1.));
#2629=DIRECTION('',(1.,0.,0.));
#2630=AXIS2_PLACEMENT_3D('',#2627,#2628,#2629);
#2631=CIRCLE('',#2630,1.5);
#2632=EDGE_CURVE('P0_E830',#2321,#2304,#2631,.T.);
#2633=ORIENTED_EDGE('',*,*,#2632,.T.);
#2634=ORIENTED_EDGE('',*,*,#2329,.T.);
#2635=EDGE_LOOP('',(#2633,#2634));
#2636=FACE_BOUND('',#2635,.T.);
#2637=CARTESIAN_POINT('',(-15.5,15.5,0.));
#2638=DIRECTION('',(0.,0.,1.));
#2639=DIRECTION('',(1.,0.,0.));
#2640=AXIS2_PLACEMENT_3D('',#2637,#2638,#2639);
#2641=CIRCLE('',#2640,1.5);
#2642=EDGE_CURVE('P0_E817',#2363,#2346,#2641,.T.);
#2643=ORIENTED_EDGE('',*,*,#2642,.T.);
#2644=ORIENTED_EDGE('',*,*,#2371,.T.);
#2645=EDGE_LOOP('',(#2643,#2644));
#2646=FACE_BOUND('',#2645,.T.);
#2647=CARTESIAN_POINT('',(15.5,-15.5,0.));
#2648=DIRECTION('',(0.,0.,1.));
#2649=DIRECTION('',(1.,0.,0.));
#2650=AXIS2_PLACEMENT_3D('',#2647,#2648,#2649);
#2651=CIRCLE('',#2650,1.5);
#2652=EDGE_CURVE('P0_E797',#2279,#2262,#2651,.T.);
#2653=ORIENTED_EDGE('',*,*,#2652,.T.);
#2654=ORIENTED_EDGE('',*,*,#2287,.T.);
#2655=EDGE_LOOP('',(#2653,#2654));
#2656=FACE_BOUND('',#2655,.T.);
#2657=DIRECTION('',(-1.,0.,0.));
#2658=VECTOR('',#2657,1.);
#2659=CARTESIAN_POINT('',(-16.8,21.,0.));
#2660=LINE('',#2659,#2658);
#2661=EDGE_CURVE('P0_E898',#2388,#1921,#2660,.T.);
#2662=ORIENTED_EDGE('',*,*,#2661,.F.);
#2663=ORIENTED_EDGE('',*,*,#2389,.F.);
#2664=ORIENTED_EDGE('',*,*,#2437,.F.);
#2665=ORIENTED_EDGE('',*,*,#2468,.F.);
#2666=ORIENTED_EDGE('',*,*,#2499,.F.);
#2667=ORIENTED_EDGE('',*,*,#2530,.F.);
#2668=ORIENTED_EDGE('',*,*,#2561,.F.);
#2669=ORIENTED_EDGE('',*,*,#2592,.F.);
#2670=DIRECTION('',(-1.,0.,0.));
#2671=VECTOR('',#2670,1.);
#2672=CARTESIAN_POINT('',(-16.8,21.,0.));
#2673=LINE('',#2672,#2671);
#2674=EDGE_CURVE('P0_E867',#1976,#2591,#2673,.T.);
#2675=ORIENTED_EDGE('',*,*,#2674,.F.);
#2676=ORIENTED_EDGE('',*,*,#1985,.F.);
#2677=ORIENTED_EDGE('',*,*,#1906,.F.);
#2678=ORIENTED_EDGE('',*,*,#1930,.T.);
#2679=EDGE_LOOP('',(#2662,#2663,#2664,#2665,#2666,#2667,#2668,#2669,#2675,#2676,#2677,#2678));
#2680=FACE_BOUND('',#2679,.T.);
#2681=ADVANCED_FACE('P0_F1737',(#2626,#2636,#2646,#2656,#2680),#2616,.T.);
#2682=CARTESIAN_POINT('',(0.,0.,60.));
#2683=DIRECTION('',(0.,0.,-1.));
#2684=DIRECTION('',(0.,-1.,0.));
#2685=AXIS2_PLACEMENT_3D('',#2682,#2683,#2684);
#2686=PLANE('',#2685);
#2687=ORIENTED_EDGE('',*,*,#2167,.F.);
#2688=CARTESIAN_POINT('',(0.,0.,60.));
#2689=DIRECTION('',(0.,0.,1.));
#2690=DIRECTION('',(1.,0.,0.));
#2691=AXIS2_PLACEMENT_3D('',#2688,#2689,#2690);
#2692=CIRCLE('',#2691,11.);
#2693=EDGE_CURVE('P0_E746',#2142,#2159,#2692,.T.);
#2694=ORIENTED_EDGE('',*,*,#2693,.F.);
#2695=EDGE_LOOP('',(#2687,#2694));
#2696=FACE_BOUND('',#2695,.T.);
#2697=CARTESIAN_POINT('',(-15.5,-15.5,60.));
#2698=DIRECTION('',(0.,0.,1.));
#2699=DIRECTION('',(1.,0.,0.));
#2700=AXIS2_PLACEMENT_3D('',#2697,#2698,#2699);
#2701=CIRCLE('',#2700,1.5);
#2702=EDGE_CURVE('P0_E750',#2229,#2218,#2701,.T.);
#2703=ORIENTED_EDGE('',*,*,#2702,.F.);
#2704=ORIENTED_EDGE('',*,*,#2230,.F.);
#2705=EDGE_LOOP('',(#2703,#2704));
#2706=FACE_BOUND('',#2705,.T.);
#2707=CARTESIAN_POINT('',(15.5,-15.5,60.));
#2708=DIRECTION('',(0.,0.,1.));
#2709=DIRECTION('',(1.,0.,0.));
#2710=AXIS2_PLACEMENT_3D('',#2707,#2708,#2709);
#2711=CIRCLE('',#2710,1.5);
#2712=EDGE_CURVE('P0_E772',#2271,#2260,#2711,.T.);
#2713=ORIENTED_EDGE('',*,*,#2712,.F.);
#2714=ORIENTED_EDGE('',*,*,#2272,.F.);
#2715=EDGE_LOOP('',(#2713,#2714));
#2716=FACE_BOUND('',#2715,.T.);
#2717=CARTESIAN_POINT('',(15.5,15.5,60.));
#2718=DIRECTION('',(0.,0.,1.));
#2719=DIRECTION('',(1.,0.,0.));
#2720=AXIS2_PLACEMENT_3D('',#2717,#2718,#2719);
#2721=CIRCLE('',#2720,1.5);
#2722=EDGE_CURVE('P0_E783',#2313,#2302,#2721,.T.);
#2723=ORIENTED_EDGE('',*,*,#2722,.F.);
#2724=ORIENTED_EDGE('',*,*,#2314,.F.);
#2725=EDGE_LOOP('',(#2723,#2724));
#2726=FACE_BOUND('',#2725,.T.);
#2727=CARTESIAN_POINT('',(-15.5,15.5,60.));
#2728=DIRECTION('',(0.,0.,1.));
#2729=DIRECTION('',(1.,0.,0.));
#2730=AXIS2_PLACEMENT_3D('',#2727,#2728,#2729);
#2731=CIRCLE('',#2730,1.5);
#2732=EDGE_CURVE('P0_E819',#2355,#2344,#2731,.T.);
#2733=ORIENTED_EDGE('',*,*,#2732,.F.);
#2734=ORIENTED_EDGE('',*,*,#2356,.F.);
#2735=EDGE_LOOP('',(#2733,#2734));
#2736=FACE_BOUND('',#2735,.T.);
#2737=DIRECTION('',(-1.,0.,0.));
#2738=VECTOR('',#2737,1.);
#2739=CARTESIAN_POINT('',(-16.8,21.,60.));
#2740=LINE('',#2739,#2738);
#2741=EDGE_CURVE('P0_E893',#2396,#2600,#2740,.T.);
#2742=ORIENTED_EDGE('',*,*,#2741,.T.);
#2743=ORIENTED_EDGE('',*,*,#2601,.T.);
#2744=ORIENTED_EDGE('',*,*,#2570,.T.);
#2745=ORIENTED_EDGE('',*,*,#2539,.T.);
#2746=ORIENTED_EDGE('',*,*,#2508,.T.);
#2747=ORIENTED_EDGE('',*,*,#2477,.T.);
#2748=ORIENTED_EDGE('',*,*,#2446,.T.);
#2749=ORIENTED_EDGE('',*,*,#2405,.T.);
#2750=EDGE_LOOP('',(#2742,#2743,#2744,#2745,#2746,#2747,#2748,#2749));
#2751=FACE_BOUND('',#2750,.T.);
#2752=ADVANCED_FACE('P0_F1739',(#2696,#2706,#2716,#2726,#2736,#2751),#2686,.F.);
#2753=CARTESIAN_POINT('',(-16.8,21.,60.));
#2754=DIRECTION('',(0.,-1.,0.));
#2755=DIRECTION('',(0.,0.,-1.));
#2756=AXIS2_PLACEMENT_3D('',#2753,#2754,#2755);
#2757=PLANE('',#2756);
#2758=ORIENTED_EDGE('',*,*,#1977,.F.);
#2759=ORIENTED_EDGE('',*,*,#2674,.T.);
#2760=ORIENTED_EDGE('',*,*,#2607,.F.);
#2761=ORIENTED_EDGE('',*,*,#2741,.F.);
#2762=ORIENTED_EDGE('',*,*,#2397,.T.);
#2763=ORIENTED_EDGE('',*,*,#2661,.T.);
#2764=ORIENTED_EDGE('',*,*,#1924,.T.);
#2765=ORIENTED_EDGE('',*,*,#1953,.F.);
#2766=EDGE_LOOP('',(#2758,#2759,#2760,#2761,#2762,#2763,#2764,#2765));
#2767=FACE_BOUND('',#2766,.T.);
#2768=ADVANCED_FACE('P0_F1750',(#2767),#2757,.F.);
#2769=CARTESIAN_POINT('',(-15.5,15.5,60.));
#2770=DIRECTION('',(0.,0.,-1.));
#2771=DIRECTION('',(-1.,0.,0.));
#2772=AXIS2_PLACEMENT_3D('',#2769,#2770,#2771);
#2773=CYLINDRICAL_SURFACE('',#2772,1.5);
#2774=ORIENTED_EDGE('',*,*,#2732,.T.);
#2775=ORIENTED_EDGE('',*,*,#2347,.T.);
#2776=ORIENTED_EDGE('',*,*,#2642,.F.);
#2777=ORIENTED_EDGE('',*,*,#2364,.F.);
#2778=EDGE_LOOP('',(#2774,#2775,#2776,#2777));
#2779=FACE_BOUND('',#2778,.T.);
#2780=ADVANCED_FACE('P0_F1741',(#2779),#2773,.F.);
#2781=CARTESIAN_POINT('',(15.5,15.5,60.));
#2782=DIRECTION('',(0.,0.,-1.));
#2783=DIRECTION('',(-1.,0.,0.));
#2784=AXIS2_PLACEMENT_3D('',#2781,#2782,#2783);
#2785=CYLINDRICAL_SURFACE('',#2784,1.5);
#2786=ORIENTED_EDGE('',*,*,#2722,.T.);
#2787=ORIENTED_EDGE('',*,*,#2305,.T.);
#2788=ORIENTED_EDGE('',*,*,#2632,.F.);
#2789=ORIENTED_EDGE('',*,*,#2322,.F.);
#2790=EDGE_LOOP('',(#2786,#2787,#2788,#2789));
#2791=FACE_BOUND('',#2790,.T.);
#2792=ADVANCED_FACE('P0_F1746',(#2791),#2785,.F.);
#2793=CARTESIAN_POINT('',(15.5,-15.5,60.));
#2794=DIRECTION('',(0.,0.,-1.));
#2795=DIRECTION('',(-1.,0.,0.));
#2796=AXIS2_PLACEMENT_3D('',#2793,#2794,#2795);
#2797=CYLINDRICAL_SURFACE('',#2796,1.5);
#2798=ORIENTED_EDGE('',*,*,#2712,.T.);
#2799=ORIENTED_EDGE('',*,*,#2263,.T.);
#2800=ORIENTED_EDGE('',*,*,#2652,.F.);
#2801=ORIENTED_EDGE('',*,*,#2280,.F.);
#2802=EDGE_LOOP('',(#2798,#2799,#2800,#2801));
#2803=FACE_BOUND('',#2802,.T.);
#2804=ADVANCED_FACE('P0_F1765',(#2803),#2797,.F.);
#2805=CARTESIAN_POINT('',(-15.5,-15.5,60.));
#2806=DIRECTION('',(0.,0.,-1.));
#2807=DIRECTION('',(-1.,0.,0.));
#2808=AXIS2_PLACEMENT_3D('',#2805,#2806,#2807);
#2809=CYLINDRICAL_SURFACE('',#2808,1.5);
#2810=ORIENTED_EDGE('',*,*,#2702,.T.);
#2811=ORIENTED_EDGE('',*,*,#2221,.T.);
#2812=ORIENTED_EDGE('',*,*,#2622,.F.);
#2813=ORIENTED_EDGE('',*,*,#2238,.F.);
#2814=EDGE_LOOP('',(#2810,#2811,#2812,#2813));
#2815=FACE_BOUND('',#2814,.T.);
#2816=ADVANCED_FACE('P0_F1763',(#2815),#2809,.F.);
#2817=CARTESIAN_POINT('',(0.,0.,62.));
#2818=DIRECTION('',(0.,0.,-1.));
#2819=DIRECTION('',(-1.,0.,0.));
#2820=AXIS2_PLACEMENT_3D('',#2817,#2818,#2819);
#2821=CYLINDRICAL_SURFACE('',#2820,11.);
#2822=ORIENTED_EDGE('',*,*,#2203,.F.);
#2823=ORIENTED_EDGE('',*,*,#2143,.T.);
#2824=ORIENTED_EDGE('',*,*,#2693,.T.);
#2825=ORIENTED_EDGE('',*,*,#2160,.F.);
#2826=EDGE_LOOP('',(#2822,#2823,#2824,#2825));
#2827=FACE_BOUND('',#2826,.T.);
#2828=ADVANCED_FACE('P0_F1768',(#2827),#2821,.T.);
#2829=CARTESIAN_POINT('',(0.,0.,112.726812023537));
#2830=DIRECTION('',(0.,0.,-1.));
#2831=DIRECTION('',(-1.,0.,0.));
#2832=AXIS2_PLACEMENT_3D('',#2829,#2830,#2831);
#2833=CYLINDRICAL_SURFACE('',#2832,2.5);
#2834=DIRECTION('',(0.,0.,-1.));
#2835=VECTOR('',#2834,1.);
#2836=CARTESIAN_POINT('',(2.5,0.,112.726812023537));
#2837=LINE('',#2836,#2835);
#2838=CARTESIAN_POINT('',(2.5,0.,83.7));
#2839=VERTEX_POINT('',#2838);
#2840=EDGE_CURVE('P0_E686',#2839,#2184,#2837,.T.);
#2841=ORIENTED_EDGE('',*,*,#2840,.F.);
#2842=CARTESIAN_POINT('',(0.,0.,83.7));
#2843=DIRECTION('',(0.,0.,-1.));
#2844=DIRECTION('',(1.,0.,0.));
#2845=AXIS2_PLACEMENT_3D('',#2842,#2843,#2844);
#2846=CIRCLE('',#2845,2.5);
#2847=EDGE_CURVE('P0_E714',#2839,#2002,#2846,.T.);
#2848=ORIENTED_EDGE('',*,*,#2847,.T.);
#2849=ORIENTED_EDGE('',*,*,#2076,.T.);
#2850=ORIENTED_EDGE('',*,*,#2192,.T.);
#2851=EDGE_LOOP('',(#2841,#2848,#2849,#2850));
#2852=FACE_BOUND('',#2851,.T.);
#2853=ADVANCED_FACE('P0_F687',(#2852),#2833,.T.);
#2854=CARTESIAN_POINT('',(0.,0.,112.726812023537));
#2855=DIRECTION('',(0.,0.,-1.));
#2856=DIRECTION('',(-1.,0.,0.));
#2857=AXIS2_PLACEMENT_3D('',#2854,#2855,#2856);
#2858=CYLINDRICAL_SURFACE('',#2857,2.5);
#2859=CARTESIAN_POINT('',(0.,0.,83.7));
#2860=DIRECTION('',(0.,0.,-1.));
#2861=DIRECTION('',(1.,0.,0.));
#2862=AXIS2_PLACEMENT_3D('',#2859,#2860,#2861);
#2863=CIRCLE('',#2862,2.5);
#2864=EDGE_CURVE('P0_E715',#2108,#2839,#2863,.T.);
#2865=ORIENTED_EDGE('',*,*,#2864,.T.);
#2866=ORIENTED_EDGE('',*,*,#2840,.T.);
#2867=ORIENTED_EDGE('',*,*,#2185,.T.);
#2868=ORIENTED_EDGE('',*,*,#2117,.F.);
#2869=EDGE_LOOP('',(#2865,#2866,#2867,#2868));
#2870=FACE_BOUND('',#2869,.T.);
#2871=ADVANCED_FACE('P0_F709',(#2870),#2858,.T.);
#2872=CARTESIAN_POINT('',(0.,0.,84.));
#2873=DIRECTION('',(0.,0.,-1.));
#2874=DIRECTION('',(-1.,0.,0.));
#2875=AXIS2_PLACEMENT_3D('',#2872,#2873,#2874);
#2876=CONICAL_SURFACE('',#2875,2.2,0.785398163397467);
#2877=DIRECTION('',(0.707106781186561,0.,-0.707106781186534));
#2878=VECTOR('',#2877,1.);
#2879=CARTESIAN_POINT('',(2.2,0.,84.));
#2880=LINE('',#2879,#2878);
#2881=EDGE_CURVE('P0_E2214',#2052,#2839,#2880,.T.);
#2882=ORIENTED_EDGE('',*,*,#2881,.F.);
#2883=ORIENTED_EDGE('',*,*,#2053,.F.);
#2884=ORIENTED_EDGE('',*,*,#2003,.T.);
#2885=ORIENTED_EDGE('',*,*,#2847,.F.);
#2886=EDGE_LOOP('',(#2882,#2883,#2884,#2885));
#2887=FACE_BOUND('',#2886,.T.);
#2888=ADVANCED_FACE('P0_F1728',(#2887),#2876,.T.);
#2889=CARTESIAN_POINT('',(0.,0.,84.));
#2890=DIRECTION('',(0.,0.,-1.));
#2891=DIRECTION('',(-1.,0.,0.));
#2892=AXIS2_PLACEMENT_3D('',#2889,#2890,#2891);
#2893=CONICAL_SURFACE('',#2892,2.2,0.785398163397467);
#2894=ORIENTED_EDGE('',*,*,#2060,.F.);
#2895=ORIENTED_EDGE('',*,*,#2881,.T.);
#2896=ORIENTED_EDGE('',*,*,#2864,.F.);
#2897=ORIENTED_EDGE('',*,*,#2109,.F.);
#2898=EDGE_LOOP('',(#2894,#2895,#2896,#2897));
#2899=FACE_BOUND('',#2898,.T.);
#2900=ADVANCED_FACE('P0_F1717',(#2899),#2893,.T.);
#2901=CLOSED_SHELL('',(#98,#206,#342,#414,#445,#469,#493,#517,#541,#565,#589,#613,#630,#661,
#685,#709,#733,#757,#781,#805,#822,#858,#887,#916,#940,#964,#993,#1017,#1046,#1070,#1099,#1123,
#1152,#1176,#1200,#1222,#1258,#1282,#1306,#1330,#1359,#1388,#1412,#1436,#1460,#1484,#1508,#1530,
#1658,#1689,#1718,#1742,#1771,#1795,#1824,#1848,#1870,#1910,#1941,#1965,#1989,#2031,#2064,#2096,
#2129,#2171,#2207,#2249,#2291,#2333,#2375,#2415,#2456,#2487,#2518,#2549,#2580,#2611,#2681,#2752,
#2768,#2780,#2792,#2804,#2816,#2828,#2853,#2871,#2888,#2900));
#2902=MANIFOLD_SOLID_BREP('P0_B1',#2901);
#2903=CARTESIAN_POINT('',(0.,21.,0.));
#2904=DIRECTION('',(0.,1.,0.));
#2905=DIRECTION('',(1.,0.,0.));
#2906=AXIS2_PLACEMENT_3D('',#2903,#2904,#2905);
#2907=PLANE('',#2906);
#2908=DIRECTION('',(1.,0.,0.));
#2909=VECTOR('',#2908,1.);
#2910=CARTESIAN_POINT('',(0.,21.,3.));
#2911=LINE('',#2910,#2909);
#2912=CARTESIAN_POINT('',(-8.25,21.,3.));
#2913=VERTEX_POINT('',#2912);
#2914=CARTESIAN_POINT('',(8.25,21.,3.));
#2915=VERTEX_POINT('',#2914);
#2916=EDGE_CURVE('P1_E74',#2913,#2915,#2911,.T.);
#2917=ORIENTED_EDGE('',*,*,#2916,.T.);
#2918=DIRECTION('',(0.,0.,1.));
#2919=VECTOR('',#2918,1.);
#2920=CARTESIAN_POINT('',(8.25,21.,0.));
#2921=LINE('',#2920,#2919);
#2922=CARTESIAN_POINT('',(8.25,21.,9.5));
#2923=VERTEX_POINT('',#2922);
#2924=EDGE_CURVE('P1_E27',#2915,#2923,#2921,.T.);
#2925=ORIENTED_EDGE('',*,*,#2924,.T.);
#2926=DIRECTION('',(1.,0.,0.));
#2927=VECTOR('',#2926,1.);
#2928=CARTESIAN_POINT('',(0.,21.,9.5));
#2929=LINE('',#2928,#2927);
#2930=CARTESIAN_POINT('',(-8.25,21.,9.5));
#2931=VERTEX_POINT('',#2930);
#2932=EDGE_CURVE('P1_E80',#2931,#2923,#2929,.T.);
#2933=ORIENTED_EDGE('',*,*,#2932,.F.);
#2934=DIRECTION('',(0.,0.,1.));
#2935=VECTOR('',#2934,1.);
#2936=CARTESIAN_POINT('',(-8.25,21.,0.));
#2937=LINE('',#2936,#2935);
#2938=EDGE_CURVE('P1_E71',#2913,#2931,#2937,.T.);
#2939=ORIENTED_EDGE('',*,*,#2938,.F.);
#2940=EDGE_LOOP('',(#2917,#2925,#2933,#2939));
#2941=FACE_BOUND('',#2940,.T.);
#2942=ADVANCED_FACE('P1_F17',(#2941),#2907,.F.);
#2943=CARTESIAN_POINT('',(0.,26.5,0.));
#2944=DIRECTION('',(0.,1.,0.));
#2945=DIRECTION('',(1.,0.,0.));
#2946=AXIS2_PLACEMENT_3D('',#2943,#2944,#2945);
#2947=PLANE('',#2946);
#2948=DIRECTION('',(1.,0.,0.));
#2949=VECTOR('',#2948,1.);
#2950=CARTESIAN_POINT('',(0.,26.5,3.));
#2951=LINE('',#2950,#2949);
#2952=CARTESIAN_POINT('',(-8.25,26.5,3.));
#2953=VERTEX_POINT('',#2952);
#2954=CARTESIAN_POINT('',(8.25,26.5,3.));
#2955=VERTEX_POINT('',#2954);
#2956=EDGE_CURVE('P1_E94',#2953,#2955,#2951,.T.);
#2957=ORIENTED_EDGE('',*,*,#2956,.F.);
#2958=DIRECTION('',(0.,0.,1.));
#2959=VECTOR('',#2958,1.);
#2960=CARTESIAN_POINT('',(-8.25,26.5,0.));
#2961=LINE('',#2960,#2959);
#2962=CARTESIAN_POINT('',(-8.25,26.5,9.5));
#2963=VERTEX_POINT('',#2962);
#2964=EDGE_CURVE('P1_E90',#2953,#2963,#2961,.T.);
#2965=ORIENTED_EDGE('',*,*,#2964,.T.);
#2966=DIRECTION('',(1.,0.,0.));
#2967=VECTOR('',#2966,1.);
#2968=CARTESIAN_POINT('',(0.,26.5,9.5));
#2969=LINE('',#2968,#2967);
#2970=CARTESIAN_POINT('',(8.25,26.5,9.5));
#2971=VERTEX_POINT('',#2970);
#2972=EDGE_CURVE('P1_E20',#2963,#2971,#2969,.T.);
#2973=ORIENTED_EDGE('',*,*,#2972,.T.);
#2974=DIRECTION('',(0.,0.,1.));
#2975=VECTOR('',#2974,1.);
#2976=CARTESIAN_POINT('',(8.25,26.5,0.));
#2977=LINE('',#2976,#2975);
#2978=EDGE_CURVE('P1_E11',#2955,#2971,#2977,.T.);
#2979=ORIENTED_EDGE('',*,*,#2978,.F.);
#2980=EDGE_LOOP('',(#2957,#2965,#2973,#2979));
#2981=FACE_BOUND('',#2980,.T.);
#2982=ADVANCED_FACE('P1_F122',(#2981),#2947,.T.);
#2983=CARTESIAN_POINT('',(8.25,26.5,0.));
#2984=DIRECTION('',(1.,0.,0.));
#2985=DIRECTION('',(0.,1.,0.));
#2986=AXIS2_PLACEMENT_3D('',#2983,#2984,#2985);
#2987=PLANE('',#2986);
#2988=ORIENTED_EDGE('',*,*,#2924,.F.);
#2989=DIRECTION('',(0.,-1.,0.));
#2990=VECTOR('',#2989,1.);
#2991=CARTESIAN_POINT('',(8.25,26.5,3.));
#2992=LINE('',#2991,#2990);
#2993=EDGE_CURVE('P1_E83',#2955,#2915,#2992,.T.);
#2994=ORIENTED_EDGE('',*,*,#2993,.F.);
#2995=ORIENTED_EDGE('',*,*,#2978,.T.);
#2996=DIRECTION('',(0.,-1.,0.));
#2997=VECTOR('',#2996,1.);
#2998=CARTESIAN_POINT('',(8.25,26.5,9.5));
#2999=LINE('',#2998,#2997);
#3000=EDGE_CURVE('P1_E111',#2971,#2923,#2999,.T.);
#3001=ORIENTED_EDGE('',*,*,#3000,.T.);
#3002=EDGE_LOOP('',(#2988,#2994,#2995,#3001));
#3003=FACE_BOUND('',#3002,.T.);
#3004=ADVANCED_FACE('P1_F128',(#3003),#2987,.T.);
#3005=CARTESIAN_POINT('',(0.,26.5,9.5));
#3006=DIRECTION('',(0.,0.,-1.));
#3007=DIRECTION('',(-1.,0.,0.));
#3008=AXIS2_PLACEMENT_3D('',#3005,#3006,#3007);
#3009=PLANE('',#3008);
#3010=ORIENTED_EDGE('',*,*,#2932,.T.);
#3011=ORIENTED_EDGE('',*,*,#3000,.F.);
#3012=ORIENTED_EDGE('',*,*,#2972,.F.);
#3013=DIRECTION('',(0.,-1.,0.));
#3014=VECTOR('',#3013,1.);
#3015=CARTESIAN_POINT('',(-8.25,26.5,9.5));
#3016=LINE('',#3015,#3014);
#3017=EDGE_CURVE('P1_E85',#2963,#2931,#3016,.T.);
#3018=ORIENTED_EDGE('',*,*,#3017,.T.);
#3019=EDGE_LOOP('',(#3010,#3011,#3012,#3018));
#3020=FACE_BOUND('',#3019,.T.);
#3021=ADVANCED_FACE('P1_F130',(#3020),#3009,.F.);
#3022=CARTESIAN_POINT('',(-8.25,26.5,0.));
#3023=DIRECTION('',(1.,0.,0.));
#3024=DIRECTION('',(0.,0.,-1.));
#3025=AXIS2_PLACEMENT_3D('',#3022,#3023,#3024);
#3026=PLANE('',#3025);
#3027=ORIENTED_EDGE('',*,*,#2938,.T.);
#3028=ORIENTED_EDGE('',*,*,#3017,.F.);
#3029=ORIENTED_EDGE('',*,*,#2964,.F.);
#3030=DIRECTION('',(0.,-1.,0.));
#3031=VECTOR('',#3030,1.);
#3032=CARTESIAN_POINT('',(-8.25,26.5,3.));
#3033=LINE('',#3032,#3031);
#3034=EDGE_CURVE('P1_E88',#2953,#2913,#3033,.T.);
#3035=ORIENTED_EDGE('',*,*,#3034,.T.);
#3036=EDGE_LOOP('',(#3027,#3028,#3029,#3035));
#3037=FACE_BOUND('',#3036,.T.);
#3038=ADVANCED_FACE('P1_F87',(#3037),#3026,.F.);
#3039=CARTESIAN_POINT('',(0.,26.5,3.));
#3040=DIRECTION('',(0.,0.,-1.));
#3041=DIRECTION('',(-1.,0.,0.));
#3042=AXIS2_PLACEMENT_3D('',#3039,#3040,#3041);
#3043=PLANE('',#3042);
#3044=ORIENTED_EDGE('',*,*,#2916,.F.);
#3045=ORIENTED_EDGE('',*,*,#3034,.F.);
#3046=ORIENTED_EDGE('',*,*,#2956,.T.);
#3047=ORIENTED_EDGE('',*,*,#2993,.T.);
#3048=EDGE_LOOP('',(#3044,#3045,#3046,#3047));
#3049=FACE_BOUND('',#3048,.T.);
#3050=ADVANCED_FACE('P1_F100',(#3049),#3043,.T.);
#3051=CLOSED_SHELL('',(#2942,#2982,#3004,#3021,#3038,#3050));
#3052=MANIFOLD_SOLID_BREP('P1_B1',#3051);
#3053=ADVANCED_BREP_SHAPE_REPRESENTATION('',(#18,#2902,#3052),#14);
#3054=SHAPE_DEFINITION_REPRESENTATION(#9,#3053);
ENDSEC;
END-ISO-10303-21;
